VERSION 5.8 ;
BUSBITCHARS "[]" ;
DIVIDERCHAR "/" ;
UNITS
    DATABASE MICRONS 1000 ;
END UNITS

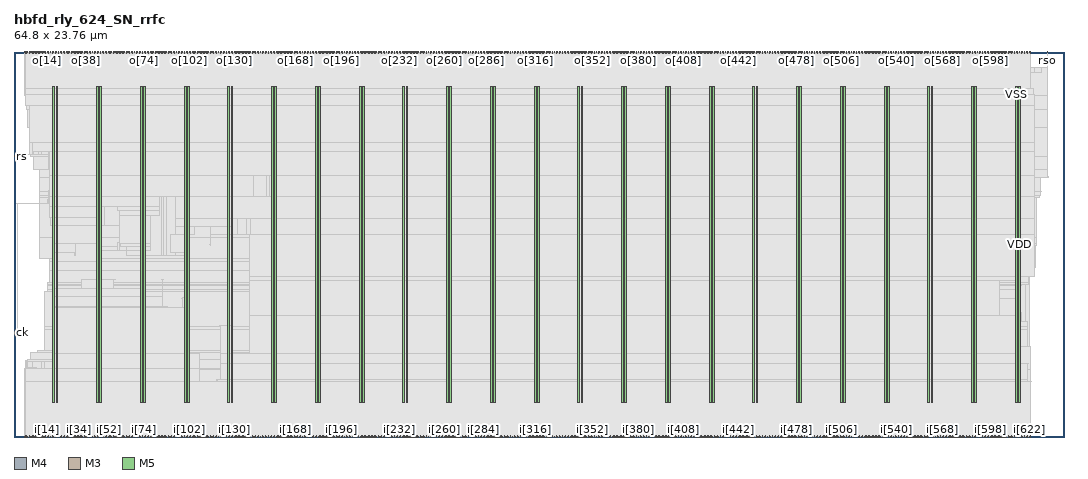
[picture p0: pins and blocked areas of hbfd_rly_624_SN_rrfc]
MACRO hbfd_rly_624_SN_rrfc
  FOREIGN hbfd_rly_624_SN_rrfc 0 0 ;
  CLASS BLOCK ;
  SIZE 64.8 BY 23.76 ;
  PIN ck
    DIRECTION INPUT ;
    USE SIGNAL ;
    PORT
      LAYER M4 ;
        RECT  0 6.432 0.084 6.456 ;
    END
  END ck
  PIN i[0]
    DIRECTION INPUT ;
    USE SIGNAL ;
    PORT
      LAYER M3 ;
        RECT  0.648 0 0.666 0.038 ;
    END
  END i[0]
  PIN i[100]
    DIRECTION INPUT ;
    USE SIGNAL ;
    PORT
      LAYER M3 ;
        RECT  10.62 0 10.638 0.038 ;
    END
  END i[100]
  PIN i[101]
    DIRECTION INPUT ;
    USE SIGNAL ;
    PORT
      LAYER M5 ;
        RECT  10.704 0 10.728 0.084 ;
    END
  END i[101]
  PIN i[102]
    DIRECTION INPUT ;
    USE SIGNAL ;
    PORT
      LAYER M3 ;
        RECT  10.8 0 10.818 0.038 ;
    END
  END i[102]
  PIN i[103]
    DIRECTION INPUT ;
    USE SIGNAL ;
    PORT
      LAYER M5 ;
        RECT  10.896 0 10.92 0.084 ;
    END
  END i[103]
  PIN i[104]
    DIRECTION INPUT ;
    USE SIGNAL ;
    PORT
      LAYER M3 ;
        RECT  11.016 0 11.034 0.038 ;
    END
  END i[104]
  PIN i[105]
    DIRECTION INPUT ;
    USE SIGNAL ;
    PORT
      LAYER M5 ;
        RECT  11.088 0 11.112 0.084 ;
    END
  END i[105]
  PIN i[106]
    DIRECTION INPUT ;
    USE SIGNAL ;
    PORT
      LAYER M3 ;
        RECT  11.196 0 11.214 0.038 ;
    END
  END i[106]
  PIN i[107]
    DIRECTION INPUT ;
    USE SIGNAL ;
    PORT
      LAYER M5 ;
        RECT  11.328 0 11.352 0.084 ;
    END
  END i[107]
  PIN i[108]
    DIRECTION INPUT ;
    USE SIGNAL ;
    PORT
      LAYER M3 ;
        RECT  11.412 0 11.43 0.038 ;
    END
  END i[108]
  PIN i[109]
    DIRECTION INPUT ;
    USE SIGNAL ;
    PORT
      LAYER M5 ;
        RECT  11.52 0 11.544 0.084 ;
    END
  END i[109]
  PIN i[10]
    DIRECTION INPUT ;
    USE SIGNAL ;
    PORT
      LAYER M3 ;
        RECT  1.656 0 1.674 0.038 ;
    END
  END i[10]
  PIN i[110]
    DIRECTION INPUT ;
    USE SIGNAL ;
    PORT
      LAYER M3 ;
        RECT  11.592 0 11.61 0.038 ;
    END
  END i[110]
  PIN i[111]
    DIRECTION INPUT ;
    USE SIGNAL ;
    PORT
      LAYER M5 ;
        RECT  11.712 0 11.736 0.084 ;
    END
  END i[111]
  PIN i[112]
    DIRECTION INPUT ;
    USE SIGNAL ;
    PORT
      LAYER M3 ;
        RECT  11.808 0 11.826 0.038 ;
    END
  END i[112]
  PIN i[113]
    DIRECTION INPUT ;
    USE SIGNAL ;
    PORT
      LAYER M5 ;
        RECT  11.904 0 11.928 0.084 ;
    END
  END i[113]
  PIN i[114]
    DIRECTION INPUT ;
    USE SIGNAL ;
    PORT
      LAYER M3 ;
        RECT  11.988 0 12.006 0.038 ;
    END
  END i[114]
  PIN i[115]
    DIRECTION INPUT ;
    USE SIGNAL ;
    PORT
      LAYER M5 ;
        RECT  12.096 0 12.12 0.084 ;
    END
  END i[115]
  PIN i[116]
    DIRECTION INPUT ;
    USE SIGNAL ;
    PORT
      LAYER M3 ;
        RECT  12.204 0 12.222 0.038 ;
    END
  END i[116]
  PIN i[117]
    DIRECTION INPUT ;
    USE SIGNAL ;
    PORT
      LAYER M5 ;
        RECT  12.288 0 12.312 0.084 ;
    END
  END i[117]
  PIN i[118]
    DIRECTION INPUT ;
    USE SIGNAL ;
    PORT
      LAYER M3 ;
        RECT  12.42 0 12.438 0.038 ;
    END
  END i[118]
  PIN i[119]
    DIRECTION INPUT ;
    USE SIGNAL ;
    PORT
      LAYER M5 ;
        RECT  12.48 0 12.504 0.084 ;
    END
  END i[119]
  PIN i[11]
    DIRECTION INPUT ;
    USE SIGNAL ;
    PORT
      LAYER M5 ;
        RECT  1.728 0 1.752 0.084 ;
    END
  END i[11]
  PIN i[120]
    DIRECTION INPUT ;
    USE SIGNAL ;
    PORT
      LAYER M3 ;
        RECT  12.6 0 12.618 0.038 ;
    END
  END i[120]
  PIN i[121]
    DIRECTION INPUT ;
    USE SIGNAL ;
    PORT
      LAYER M5 ;
        RECT  12.72 0 12.744 0.084 ;
    END
  END i[121]
  PIN i[122]
    DIRECTION INPUT ;
    USE SIGNAL ;
    PORT
      LAYER M3 ;
        RECT  12.816 0 12.834 0.038 ;
    END
  END i[122]
  PIN i[123]
    DIRECTION INPUT ;
    USE SIGNAL ;
    PORT
      LAYER M5 ;
        RECT  12.912 0 12.936 0.084 ;
    END
  END i[123]
  PIN i[124]
    DIRECTION INPUT ;
    USE SIGNAL ;
    PORT
      LAYER M3 ;
        RECT  12.996 0 13.014 0.038 ;
    END
  END i[124]
  PIN i[125]
    DIRECTION INPUT ;
    USE SIGNAL ;
    PORT
      LAYER M5 ;
        RECT  13.104 0 13.128 0.084 ;
    END
  END i[125]
  PIN i[126]
    DIRECTION INPUT ;
    USE SIGNAL ;
    PORT
      LAYER M3 ;
        RECT  13.212 0 13.23 0.038 ;
    END
  END i[126]
  PIN i[127]
    DIRECTION INPUT ;
    USE SIGNAL ;
    PORT
      LAYER M5 ;
        RECT  13.296 0 13.32 0.084 ;
    END
  END i[127]
  PIN i[128]
    DIRECTION INPUT ;
    USE SIGNAL ;
    PORT
      LAYER M3 ;
        RECT  13.392 0 13.41 0.038 ;
    END
  END i[128]
  PIN i[129]
    DIRECTION INPUT ;
    USE SIGNAL ;
    PORT
      LAYER M5 ;
        RECT  13.488 0 13.512 0.084 ;
    END
  END i[129]
  PIN i[12]
    DIRECTION INPUT ;
    USE SIGNAL ;
    PORT
      LAYER M3 ;
        RECT  1.836 0 1.854 0.038 ;
    END
  END i[12]
  PIN i[130]
    DIRECTION INPUT ;
    USE SIGNAL ;
    PORT
      LAYER M3 ;
        RECT  13.608 0 13.626 0.038 ;
    END
  END i[130]
  PIN i[131]
    DIRECTION INPUT ;
    USE SIGNAL ;
    PORT
      LAYER M5 ;
        RECT  13.68 0 13.704 0.084 ;
    END
  END i[131]
  PIN i[132]
    DIRECTION INPUT ;
    USE SIGNAL ;
    PORT
      LAYER M3 ;
        RECT  13.788 0 13.806 0.038 ;
    END
  END i[132]
  PIN i[133]
    DIRECTION INPUT ;
    USE SIGNAL ;
    PORT
      LAYER M5 ;
        RECT  13.872 0 13.896 0.084 ;
    END
  END i[133]
  PIN i[134]
    DIRECTION INPUT ;
    USE SIGNAL ;
    PORT
      LAYER M3 ;
        RECT  14.004 0 14.022 0.038 ;
    END
  END i[134]
  PIN i[135]
    DIRECTION INPUT ;
    USE SIGNAL ;
    PORT
      LAYER M5 ;
        RECT  14.112 0 14.136 0.084 ;
    END
  END i[135]
  PIN i[136]
    DIRECTION INPUT ;
    USE SIGNAL ;
    PORT
      LAYER M3 ;
        RECT  14.184 0 14.202 0.038 ;
    END
  END i[136]
  PIN i[137]
    DIRECTION INPUT ;
    USE SIGNAL ;
    PORT
      LAYER M5 ;
        RECT  14.304 0 14.328 0.084 ;
    END
  END i[137]
  PIN i[138]
    DIRECTION INPUT ;
    USE SIGNAL ;
    PORT
      LAYER M3 ;
        RECT  14.4 0 14.418 0.038 ;
    END
  END i[138]
  PIN i[139]
    DIRECTION INPUT ;
    USE SIGNAL ;
    PORT
      LAYER M5 ;
        RECT  14.496 0 14.52 0.084 ;
    END
  END i[139]
  PIN i[13]
    DIRECTION INPUT ;
    USE SIGNAL ;
    PORT
      LAYER M5 ;
        RECT  1.92 0 1.944 0.084 ;
    END
  END i[13]
  PIN i[140]
    DIRECTION INPUT ;
    USE SIGNAL ;
    PORT
      LAYER M3 ;
        RECT  14.58 0 14.598 0.038 ;
    END
  END i[140]
  PIN i[141]
    DIRECTION INPUT ;
    USE SIGNAL ;
    PORT
      LAYER M5 ;
        RECT  14.688 0 14.712 0.084 ;
    END
  END i[141]
  PIN i[142]
    DIRECTION INPUT ;
    USE SIGNAL ;
    PORT
      LAYER M3 ;
        RECT  14.796 0 14.814 0.038 ;
    END
  END i[142]
  PIN i[143]
    DIRECTION INPUT ;
    USE SIGNAL ;
    PORT
      LAYER M5 ;
        RECT  14.88 0 14.904 0.084 ;
    END
  END i[143]
  PIN i[144]
    DIRECTION INPUT ;
    USE SIGNAL ;
    PORT
      LAYER M3 ;
        RECT  15.012 0 15.03 0.038 ;
    END
  END i[144]
  PIN i[145]
    DIRECTION INPUT ;
    USE SIGNAL ;
    PORT
      LAYER M5 ;
        RECT  15.072 0 15.096 0.084 ;
    END
  END i[145]
  PIN i[146]
    DIRECTION INPUT ;
    USE SIGNAL ;
    PORT
      LAYER M3 ;
        RECT  15.192 0 15.21 0.038 ;
    END
  END i[146]
  PIN i[147]
    DIRECTION INPUT ;
    USE SIGNAL ;
    PORT
      LAYER M5 ;
        RECT  15.312 0 15.336 0.084 ;
    END
  END i[147]
  PIN i[148]
    DIRECTION INPUT ;
    USE SIGNAL ;
    PORT
      LAYER M3 ;
        RECT  15.408 0 15.426 0.038 ;
    END
  END i[148]
  PIN i[149]
    DIRECTION INPUT ;
    USE SIGNAL ;
    PORT
      LAYER M5 ;
        RECT  15.504 0 15.528 0.084 ;
    END
  END i[149]
  PIN i[14]
    DIRECTION INPUT ;
    USE SIGNAL ;
    PORT
      LAYER M3 ;
        RECT  2.052 0 2.07 0.038 ;
    END
  END i[14]
  PIN i[150]
    DIRECTION INPUT ;
    USE SIGNAL ;
    PORT
      LAYER M3 ;
        RECT  15.588 0 15.606 0.038 ;
    END
  END i[150]
  PIN i[151]
    DIRECTION INPUT ;
    USE SIGNAL ;
    PORT
      LAYER M5 ;
        RECT  15.696 0 15.72 0.084 ;
    END
  END i[151]
  PIN i[152]
    DIRECTION INPUT ;
    USE SIGNAL ;
    PORT
      LAYER M3 ;
        RECT  15.804 0 15.822 0.038 ;
    END
  END i[152]
  PIN i[153]
    DIRECTION INPUT ;
    USE SIGNAL ;
    PORT
      LAYER M5 ;
        RECT  15.888 0 15.912 0.084 ;
    END
  END i[153]
  PIN i[154]
    DIRECTION INPUT ;
    USE SIGNAL ;
    PORT
      LAYER M3 ;
        RECT  15.984 0 16.002 0.038 ;
    END
  END i[154]
  PIN i[155]
    DIRECTION INPUT ;
    USE SIGNAL ;
    PORT
      LAYER M5 ;
        RECT  16.08 0 16.104 0.084 ;
    END
  END i[155]
  PIN i[156]
    DIRECTION INPUT ;
    USE SIGNAL ;
    PORT
      LAYER M3 ;
        RECT  16.2 0 16.218 0.038 ;
    END
  END i[156]
  PIN i[157]
    DIRECTION INPUT ;
    USE SIGNAL ;
    PORT
      LAYER M5 ;
        RECT  16.272 0 16.296 0.084 ;
    END
  END i[157]
  PIN i[158]
    DIRECTION INPUT ;
    USE SIGNAL ;
    PORT
      LAYER M3 ;
        RECT  16.38 0 16.398 0.038 ;
    END
  END i[158]
  PIN i[159]
    DIRECTION INPUT ;
    USE SIGNAL ;
    PORT
      LAYER M5 ;
        RECT  16.464 0 16.488 0.084 ;
    END
  END i[159]
  PIN i[15]
    DIRECTION INPUT ;
    USE SIGNAL ;
    PORT
      LAYER M5 ;
        RECT  2.112 0 2.136 0.084 ;
    END
  END i[15]
  PIN i[160]
    DIRECTION INPUT ;
    USE SIGNAL ;
    PORT
      LAYER M3 ;
        RECT  16.596 0 16.614 0.038 ;
    END
  END i[160]
  PIN i[161]
    DIRECTION INPUT ;
    USE SIGNAL ;
    PORT
      LAYER M5 ;
        RECT  16.704 0 16.728 0.084 ;
    END
  END i[161]
  PIN i[162]
    DIRECTION INPUT ;
    USE SIGNAL ;
    PORT
      LAYER M3 ;
        RECT  16.776 0 16.794 0.038 ;
    END
  END i[162]
  PIN i[163]
    DIRECTION INPUT ;
    USE SIGNAL ;
    PORT
      LAYER M5 ;
        RECT  16.896 0 16.92 0.084 ;
    END
  END i[163]
  PIN i[164]
    DIRECTION INPUT ;
    USE SIGNAL ;
    PORT
      LAYER M3 ;
        RECT  16.992 0 17.01 0.038 ;
    END
  END i[164]
  PIN i[165]
    DIRECTION INPUT ;
    USE SIGNAL ;
    PORT
      LAYER M5 ;
        RECT  17.088 0 17.112 0.084 ;
    END
  END i[165]
  PIN i[166]
    DIRECTION INPUT ;
    USE SIGNAL ;
    PORT
      LAYER M3 ;
        RECT  17.172 0 17.19 0.038 ;
    END
  END i[166]
  PIN i[167]
    DIRECTION INPUT ;
    USE SIGNAL ;
    PORT
      LAYER M5 ;
        RECT  17.28 0 17.304 0.084 ;
    END
  END i[167]
  PIN i[168]
    DIRECTION INPUT ;
    USE SIGNAL ;
    PORT
      LAYER M3 ;
        RECT  17.388 0 17.406 0.038 ;
    END
  END i[168]
  PIN i[169]
    DIRECTION INPUT ;
    USE SIGNAL ;
    PORT
      LAYER M5 ;
        RECT  17.472 0 17.496 0.084 ;
    END
  END i[169]
  PIN i[16]
    DIRECTION INPUT ;
    USE SIGNAL ;
    PORT
      LAYER M3 ;
        RECT  2.232 0 2.25 0.038 ;
    END
  END i[16]
  PIN i[170]
    DIRECTION INPUT ;
    USE SIGNAL ;
    PORT
      LAYER M3 ;
        RECT  17.604 0 17.622 0.038 ;
    END
  END i[170]
  PIN i[171]
    DIRECTION INPUT ;
    USE SIGNAL ;
    PORT
      LAYER M5 ;
        RECT  17.664 0 17.688 0.084 ;
    END
  END i[171]
  PIN i[172]
    DIRECTION INPUT ;
    USE SIGNAL ;
    PORT
      LAYER M3 ;
        RECT  17.784 0 17.802 0.038 ;
    END
  END i[172]
  PIN i[173]
    DIRECTION INPUT ;
    USE SIGNAL ;
    PORT
      LAYER M5 ;
        RECT  17.904 0 17.928 0.084 ;
    END
  END i[173]
  PIN i[174]
    DIRECTION INPUT ;
    USE SIGNAL ;
    PORT
      LAYER M3 ;
        RECT  18 0 18.018 0.038 ;
    END
  END i[174]
  PIN i[175]
    DIRECTION INPUT ;
    USE SIGNAL ;
    PORT
      LAYER M5 ;
        RECT  18.096 0 18.12 0.084 ;
    END
  END i[175]
  PIN i[176]
    DIRECTION INPUT ;
    USE SIGNAL ;
    PORT
      LAYER M3 ;
        RECT  18.18 0 18.198 0.038 ;
    END
  END i[176]
  PIN i[177]
    DIRECTION INPUT ;
    USE SIGNAL ;
    PORT
      LAYER M5 ;
        RECT  18.288 0 18.312 0.084 ;
    END
  END i[177]
  PIN i[178]
    DIRECTION INPUT ;
    USE SIGNAL ;
    PORT
      LAYER M3 ;
        RECT  18.396 0 18.414 0.038 ;
    END
  END i[178]
  PIN i[179]
    DIRECTION INPUT ;
    USE SIGNAL ;
    PORT
      LAYER M5 ;
        RECT  18.48 0 18.504 0.084 ;
    END
  END i[179]
  PIN i[17]
    DIRECTION INPUT ;
    USE SIGNAL ;
    PORT
      LAYER M5 ;
        RECT  2.352 0 2.376 0.084 ;
    END
  END i[17]
  PIN i[180]
    DIRECTION INPUT ;
    USE SIGNAL ;
    PORT
      LAYER M3 ;
        RECT  18.576 0 18.594 0.038 ;
    END
  END i[180]
  PIN i[181]
    DIRECTION INPUT ;
    USE SIGNAL ;
    PORT
      LAYER M5 ;
        RECT  18.672 0 18.696 0.084 ;
    END
  END i[181]
  PIN i[182]
    DIRECTION INPUT ;
    USE SIGNAL ;
    PORT
      LAYER M3 ;
        RECT  18.792 0 18.81 0.038 ;
    END
  END i[182]
  PIN i[183]
    DIRECTION INPUT ;
    USE SIGNAL ;
    PORT
      LAYER M5 ;
        RECT  18.864 0 18.888 0.084 ;
    END
  END i[183]
  PIN i[184]
    DIRECTION INPUT ;
    USE SIGNAL ;
    PORT
      LAYER M3 ;
        RECT  18.972 0 18.99 0.038 ;
    END
  END i[184]
  PIN i[185]
    DIRECTION INPUT ;
    USE SIGNAL ;
    PORT
      LAYER M5 ;
        RECT  19.056 0 19.08 0.084 ;
    END
  END i[185]
  PIN i[186]
    DIRECTION INPUT ;
    USE SIGNAL ;
    PORT
      LAYER M3 ;
        RECT  19.188 0 19.206 0.038 ;
    END
  END i[186]
  PIN i[187]
    DIRECTION INPUT ;
    USE SIGNAL ;
    PORT
      LAYER M5 ;
        RECT  19.296 0 19.32 0.084 ;
    END
  END i[187]
  PIN i[188]
    DIRECTION INPUT ;
    USE SIGNAL ;
    PORT
      LAYER M3 ;
        RECT  19.368 0 19.386 0.038 ;
    END
  END i[188]
  PIN i[189]
    DIRECTION INPUT ;
    USE SIGNAL ;
    PORT
      LAYER M5 ;
        RECT  19.488 0 19.512 0.084 ;
    END
  END i[189]
  PIN i[18]
    DIRECTION INPUT ;
    USE SIGNAL ;
    PORT
      LAYER M3 ;
        RECT  2.448 0 2.466 0.038 ;
    END
  END i[18]
  PIN i[190]
    DIRECTION INPUT ;
    USE SIGNAL ;
    PORT
      LAYER M3 ;
        RECT  19.584 0 19.602 0.038 ;
    END
  END i[190]
  PIN i[191]
    DIRECTION INPUT ;
    USE SIGNAL ;
    PORT
      LAYER M5 ;
        RECT  19.68 0 19.704 0.084 ;
    END
  END i[191]
  PIN i[192]
    DIRECTION INPUT ;
    USE SIGNAL ;
    PORT
      LAYER M3 ;
        RECT  19.764 0 19.782 0.038 ;
    END
  END i[192]
  PIN i[193]
    DIRECTION INPUT ;
    USE SIGNAL ;
    PORT
      LAYER M5 ;
        RECT  19.872 0 19.896 0.084 ;
    END
  END i[193]
  PIN i[194]
    DIRECTION INPUT ;
    USE SIGNAL ;
    PORT
      LAYER M3 ;
        RECT  19.98 0 19.998 0.038 ;
    END
  END i[194]
  PIN i[195]
    DIRECTION INPUT ;
    USE SIGNAL ;
    PORT
      LAYER M5 ;
        RECT  20.064 0 20.088 0.084 ;
    END
  END i[195]
  PIN i[196]
    DIRECTION INPUT ;
    USE SIGNAL ;
    PORT
      LAYER M3 ;
        RECT  20.196 0 20.214 0.038 ;
    END
  END i[196]
  PIN i[197]
    DIRECTION INPUT ;
    USE SIGNAL ;
    PORT
      LAYER M5 ;
        RECT  20.256 0 20.28 0.084 ;
    END
  END i[197]
  PIN i[198]
    DIRECTION INPUT ;
    USE SIGNAL ;
    PORT
      LAYER M3 ;
        RECT  20.376 0 20.394 0.038 ;
    END
  END i[198]
  PIN i[199]
    DIRECTION INPUT ;
    USE SIGNAL ;
    PORT
      LAYER M5 ;
        RECT  20.496 0 20.52 0.084 ;
    END
  END i[199]
  PIN i[19]
    DIRECTION INPUT ;
    USE SIGNAL ;
    PORT
      LAYER M5 ;
        RECT  2.544 0 2.568 0.084 ;
    END
  END i[19]
  PIN i[1]
    DIRECTION INPUT ;
    USE SIGNAL ;
    PORT
      LAYER M5 ;
        RECT  0.72 0 0.744 0.084 ;
    END
  END i[1]
  PIN i[200]
    DIRECTION INPUT ;
    USE SIGNAL ;
    PORT
      LAYER M3 ;
        RECT  20.592 0 20.61 0.038 ;
    END
  END i[200]
  PIN i[201]
    DIRECTION INPUT ;
    USE SIGNAL ;
    PORT
      LAYER M5 ;
        RECT  20.688 0 20.712 0.084 ;
    END
  END i[201]
  PIN i[202]
    DIRECTION INPUT ;
    USE SIGNAL ;
    PORT
      LAYER M3 ;
        RECT  20.772 0 20.79 0.038 ;
    END
  END i[202]
  PIN i[203]
    DIRECTION INPUT ;
    USE SIGNAL ;
    PORT
      LAYER M5 ;
        RECT  20.88 0 20.904 0.084 ;
    END
  END i[203]
  PIN i[204]
    DIRECTION INPUT ;
    USE SIGNAL ;
    PORT
      LAYER M3 ;
        RECT  20.988 0 21.006 0.038 ;
    END
  END i[204]
  PIN i[205]
    DIRECTION INPUT ;
    USE SIGNAL ;
    PORT
      LAYER M5 ;
        RECT  21.072 0 21.096 0.084 ;
    END
  END i[205]
  PIN i[206]
    DIRECTION INPUT ;
    USE SIGNAL ;
    PORT
      LAYER M3 ;
        RECT  21.168 0 21.186 0.038 ;
    END
  END i[206]
  PIN i[207]
    DIRECTION INPUT ;
    USE SIGNAL ;
    PORT
      LAYER M5 ;
        RECT  21.264 0 21.288 0.084 ;
    END
  END i[207]
  PIN i[208]
    DIRECTION INPUT ;
    USE SIGNAL ;
    PORT
      LAYER M3 ;
        RECT  21.384 0 21.402 0.038 ;
    END
  END i[208]
  PIN i[209]
    DIRECTION INPUT ;
    USE SIGNAL ;
    PORT
      LAYER M5 ;
        RECT  21.456 0 21.48 0.084 ;
    END
  END i[209]
  PIN i[20]
    DIRECTION INPUT ;
    USE SIGNAL ;
    PORT
      LAYER M3 ;
        RECT  2.628 0 2.646 0.038 ;
    END
  END i[20]
  PIN i[210]
    DIRECTION INPUT ;
    USE SIGNAL ;
    PORT
      LAYER M3 ;
        RECT  21.564 0 21.582 0.038 ;
    END
  END i[210]
  PIN i[211]
    DIRECTION INPUT ;
    USE SIGNAL ;
    PORT
      LAYER M5 ;
        RECT  21.648 0 21.672 0.084 ;
    END
  END i[211]
  PIN i[212]
    DIRECTION INPUT ;
    USE SIGNAL ;
    PORT
      LAYER M3 ;
        RECT  21.78 0 21.798 0.038 ;
    END
  END i[212]
  PIN i[213]
    DIRECTION INPUT ;
    USE SIGNAL ;
    PORT
      LAYER M5 ;
        RECT  21.888 0 21.912 0.084 ;
    END
  END i[213]
  PIN i[214]
    DIRECTION INPUT ;
    USE SIGNAL ;
    PORT
      LAYER M3 ;
        RECT  21.96 0 21.978 0.038 ;
    END
  END i[214]
  PIN i[215]
    DIRECTION INPUT ;
    USE SIGNAL ;
    PORT
      LAYER M5 ;
        RECT  22.08 0 22.104 0.084 ;
    END
  END i[215]
  PIN i[216]
    DIRECTION INPUT ;
    USE SIGNAL ;
    PORT
      LAYER M3 ;
        RECT  22.176 0 22.194 0.038 ;
    END
  END i[216]
  PIN i[217]
    DIRECTION INPUT ;
    USE SIGNAL ;
    PORT
      LAYER M5 ;
        RECT  22.272 0 22.296 0.084 ;
    END
  END i[217]
  PIN i[218]
    DIRECTION INPUT ;
    USE SIGNAL ;
    PORT
      LAYER M3 ;
        RECT  22.356 0 22.374 0.038 ;
    END
  END i[218]
  PIN i[219]
    DIRECTION INPUT ;
    USE SIGNAL ;
    PORT
      LAYER M5 ;
        RECT  22.464 0 22.488 0.084 ;
    END
  END i[219]
  PIN i[21]
    DIRECTION INPUT ;
    USE SIGNAL ;
    PORT
      LAYER M5 ;
        RECT  2.736 0 2.76 0.084 ;
    END
  END i[21]
  PIN i[220]
    DIRECTION INPUT ;
    USE SIGNAL ;
    PORT
      LAYER M3 ;
        RECT  22.572 0 22.59 0.038 ;
    END
  END i[220]
  PIN i[221]
    DIRECTION INPUT ;
    USE SIGNAL ;
    PORT
      LAYER M5 ;
        RECT  22.656 0 22.68 0.084 ;
    END
  END i[221]
  PIN i[222]
    DIRECTION INPUT ;
    USE SIGNAL ;
    PORT
      LAYER M3 ;
        RECT  22.788 0 22.806 0.038 ;
    END
  END i[222]
  PIN i[223]
    DIRECTION INPUT ;
    USE SIGNAL ;
    PORT
      LAYER M5 ;
        RECT  22.848 0 22.872 0.084 ;
    END
  END i[223]
  PIN i[224]
    DIRECTION INPUT ;
    USE SIGNAL ;
    PORT
      LAYER M3 ;
        RECT  22.968 0 22.986 0.038 ;
    END
  END i[224]
  PIN i[225]
    DIRECTION INPUT ;
    USE SIGNAL ;
    PORT
      LAYER M5 ;
        RECT  23.088 0 23.112 0.084 ;
    END
  END i[225]
  PIN i[226]
    DIRECTION INPUT ;
    USE SIGNAL ;
    PORT
      LAYER M3 ;
        RECT  23.184 0 23.202 0.038 ;
    END
  END i[226]
  PIN i[227]
    DIRECTION INPUT ;
    USE SIGNAL ;
    PORT
      LAYER M5 ;
        RECT  23.28 0 23.304 0.084 ;
    END
  END i[227]
  PIN i[228]
    DIRECTION INPUT ;
    USE SIGNAL ;
    PORT
      LAYER M3 ;
        RECT  23.364 0 23.382 0.038 ;
    END
  END i[228]
  PIN i[229]
    DIRECTION INPUT ;
    USE SIGNAL ;
    PORT
      LAYER M5 ;
        RECT  23.472 0 23.496 0.084 ;
    END
  END i[229]
  PIN i[22]
    DIRECTION INPUT ;
    USE SIGNAL ;
    PORT
      LAYER M3 ;
        RECT  2.844 0 2.862 0.038 ;
    END
  END i[22]
  PIN i[230]
    DIRECTION INPUT ;
    USE SIGNAL ;
    PORT
      LAYER M3 ;
        RECT  23.58 0 23.598 0.038 ;
    END
  END i[230]
  PIN i[231]
    DIRECTION INPUT ;
    USE SIGNAL ;
    PORT
      LAYER M5 ;
        RECT  23.664 0 23.688 0.084 ;
    END
  END i[231]
  PIN i[232]
    DIRECTION INPUT ;
    USE SIGNAL ;
    PORT
      LAYER M3 ;
        RECT  23.76 0 23.778 0.038 ;
    END
  END i[232]
  PIN i[233]
    DIRECTION INPUT ;
    USE SIGNAL ;
    PORT
      LAYER M5 ;
        RECT  23.856 0 23.88 0.084 ;
    END
  END i[233]
  PIN i[234]
    DIRECTION INPUT ;
    USE SIGNAL ;
    PORT
      LAYER M3 ;
        RECT  23.976 0 23.994 0.038 ;
    END
  END i[234]
  PIN i[235]
    DIRECTION INPUT ;
    USE SIGNAL ;
    PORT
      LAYER M5 ;
        RECT  24.048 0 24.072 0.084 ;
    END
  END i[235]
  PIN i[236]
    DIRECTION INPUT ;
    USE SIGNAL ;
    PORT
      LAYER M3 ;
        RECT  24.156 0 24.174 0.038 ;
    END
  END i[236]
  PIN i[237]
    DIRECTION INPUT ;
    USE SIGNAL ;
    PORT
      LAYER M5 ;
        RECT  24.24 0 24.264 0.084 ;
    END
  END i[237]
  PIN i[238]
    DIRECTION INPUT ;
    USE SIGNAL ;
    PORT
      LAYER M3 ;
        RECT  24.372 0 24.39 0.038 ;
    END
  END i[238]
  PIN i[239]
    DIRECTION INPUT ;
    USE SIGNAL ;
    PORT
      LAYER M5 ;
        RECT  24.48 0 24.504 0.084 ;
    END
  END i[239]
  PIN i[23]
    DIRECTION INPUT ;
    USE SIGNAL ;
    PORT
      LAYER M5 ;
        RECT  2.928 0 2.952 0.084 ;
    END
  END i[23]
  PIN i[240]
    DIRECTION INPUT ;
    USE SIGNAL ;
    PORT
      LAYER M3 ;
        RECT  24.552 0 24.57 0.038 ;
    END
  END i[240]
  PIN i[241]
    DIRECTION INPUT ;
    USE SIGNAL ;
    PORT
      LAYER M5 ;
        RECT  24.672 0 24.696 0.084 ;
    END
  END i[241]
  PIN i[242]
    DIRECTION INPUT ;
    USE SIGNAL ;
    PORT
      LAYER M3 ;
        RECT  24.768 0 24.786 0.038 ;
    END
  END i[242]
  PIN i[243]
    DIRECTION INPUT ;
    USE SIGNAL ;
    PORT
      LAYER M5 ;
        RECT  24.864 0 24.888 0.084 ;
    END
  END i[243]
  PIN i[244]
    DIRECTION INPUT ;
    USE SIGNAL ;
    PORT
      LAYER M3 ;
        RECT  24.948 0 24.966 0.038 ;
    END
  END i[244]
  PIN i[245]
    DIRECTION INPUT ;
    USE SIGNAL ;
    PORT
      LAYER M5 ;
        RECT  25.056 0 25.08 0.084 ;
    END
  END i[245]
  PIN i[246]
    DIRECTION INPUT ;
    USE SIGNAL ;
    PORT
      LAYER M3 ;
        RECT  25.164 0 25.182 0.038 ;
    END
  END i[246]
  PIN i[247]
    DIRECTION INPUT ;
    USE SIGNAL ;
    PORT
      LAYER M5 ;
        RECT  25.248 0 25.272 0.084 ;
    END
  END i[247]
  PIN i[248]
    DIRECTION INPUT ;
    USE SIGNAL ;
    PORT
      LAYER M3 ;
        RECT  25.344 0 25.362 0.038 ;
    END
  END i[248]
  PIN i[249]
    DIRECTION INPUT ;
    USE SIGNAL ;
    PORT
      LAYER M5 ;
        RECT  25.44 0 25.464 0.084 ;
    END
  END i[249]
  PIN i[24]
    DIRECTION INPUT ;
    USE SIGNAL ;
    PORT
      LAYER M3 ;
        RECT  3.024 0 3.042 0.038 ;
    END
  END i[24]
  PIN i[250]
    DIRECTION INPUT ;
    USE SIGNAL ;
    PORT
      LAYER M3 ;
        RECT  25.56 0 25.578 0.038 ;
    END
  END i[250]
  PIN i[251]
    DIRECTION INPUT ;
    USE SIGNAL ;
    PORT
      LAYER M5 ;
        RECT  25.68 0 25.704 0.084 ;
    END
  END i[251]
  PIN i[252]
    DIRECTION INPUT ;
    USE SIGNAL ;
    PORT
      LAYER M3 ;
        RECT  25.776 0 25.794 0.038 ;
    END
  END i[252]
  PIN i[253]
    DIRECTION INPUT ;
    USE SIGNAL ;
    PORT
      LAYER M5 ;
        RECT  25.872 0 25.896 0.084 ;
    END
  END i[253]
  PIN i[254]
    DIRECTION INPUT ;
    USE SIGNAL ;
    PORT
      LAYER M3 ;
        RECT  25.956 0 25.974 0.038 ;
    END
  END i[254]
  PIN i[255]
    DIRECTION INPUT ;
    USE SIGNAL ;
    PORT
      LAYER M5 ;
        RECT  26.064 0 26.088 0.084 ;
    END
  END i[255]
  PIN i[256]
    DIRECTION INPUT ;
    USE SIGNAL ;
    PORT
      LAYER M3 ;
        RECT  26.172 0 26.19 0.038 ;
    END
  END i[256]
  PIN i[257]
    DIRECTION INPUT ;
    USE SIGNAL ;
    PORT
      LAYER M5 ;
        RECT  26.256 0 26.28 0.084 ;
    END
  END i[257]
  PIN i[258]
    DIRECTION INPUT ;
    USE SIGNAL ;
    PORT
      LAYER M3 ;
        RECT  26.352 0 26.37 0.038 ;
    END
  END i[258]
  PIN i[259]
    DIRECTION INPUT ;
    USE SIGNAL ;
    PORT
      LAYER M5 ;
        RECT  26.448 0 26.472 0.084 ;
    END
  END i[259]
  PIN i[25]
    DIRECTION INPUT ;
    USE SIGNAL ;
    PORT
      LAYER M5 ;
        RECT  3.12 0 3.144 0.084 ;
    END
  END i[25]
  PIN i[260]
    DIRECTION INPUT ;
    USE SIGNAL ;
    PORT
      LAYER M3 ;
        RECT  26.568 0 26.586 0.038 ;
    END
  END i[260]
  PIN i[261]
    DIRECTION INPUT ;
    USE SIGNAL ;
    PORT
      LAYER M5 ;
        RECT  26.64 0 26.664 0.084 ;
    END
  END i[261]
  PIN i[262]
    DIRECTION INPUT ;
    USE SIGNAL ;
    PORT
      LAYER M3 ;
        RECT  26.748 0 26.766 0.038 ;
    END
  END i[262]
  PIN i[263]
    DIRECTION INPUT ;
    USE SIGNAL ;
    PORT
      LAYER M5 ;
        RECT  26.832 0 26.856 0.084 ;
    END
  END i[263]
  PIN i[264]
    DIRECTION INPUT ;
    USE SIGNAL ;
    PORT
      LAYER M3 ;
        RECT  26.964 0 26.982 0.038 ;
    END
  END i[264]
  PIN i[265]
    DIRECTION INPUT ;
    USE SIGNAL ;
    PORT
      LAYER M5 ;
        RECT  27.072 0 27.096 0.084 ;
    END
  END i[265]
  PIN i[266]
    DIRECTION INPUT ;
    USE SIGNAL ;
    PORT
      LAYER M3 ;
        RECT  27.144 0 27.162 0.038 ;
    END
  END i[266]
  PIN i[267]
    DIRECTION INPUT ;
    USE SIGNAL ;
    PORT
      LAYER M5 ;
        RECT  27.264 0 27.288 0.084 ;
    END
  END i[267]
  PIN i[268]
    DIRECTION INPUT ;
    USE SIGNAL ;
    PORT
      LAYER M3 ;
        RECT  27.36 0 27.378 0.038 ;
    END
  END i[268]
  PIN i[269]
    DIRECTION INPUT ;
    USE SIGNAL ;
    PORT
      LAYER M5 ;
        RECT  27.456 0 27.48 0.084 ;
    END
  END i[269]
  PIN i[26]
    DIRECTION INPUT ;
    USE SIGNAL ;
    PORT
      LAYER M3 ;
        RECT  3.24 0 3.258 0.038 ;
    END
  END i[26]
  PIN i[270]
    DIRECTION INPUT ;
    USE SIGNAL ;
    PORT
      LAYER M3 ;
        RECT  27.54 0 27.558 0.038 ;
    END
  END i[270]
  PIN i[271]
    DIRECTION INPUT ;
    USE SIGNAL ;
    PORT
      LAYER M5 ;
        RECT  27.648 0 27.672 0.084 ;
    END
  END i[271]
  PIN i[272]
    DIRECTION INPUT ;
    USE SIGNAL ;
    PORT
      LAYER M3 ;
        RECT  27.756 0 27.774 0.038 ;
    END
  END i[272]
  PIN i[273]
    DIRECTION INPUT ;
    USE SIGNAL ;
    PORT
      LAYER M5 ;
        RECT  27.84 0 27.864 0.084 ;
    END
  END i[273]
  PIN i[274]
    DIRECTION INPUT ;
    USE SIGNAL ;
    PORT
      LAYER M3 ;
        RECT  27.936 0 27.954 0.038 ;
    END
  END i[274]
  PIN i[275]
    DIRECTION INPUT ;
    USE SIGNAL ;
    PORT
      LAYER M5 ;
        RECT  28.032 0 28.056 0.084 ;
    END
  END i[275]
  PIN i[276]
    DIRECTION INPUT ;
    USE SIGNAL ;
    PORT
      LAYER M3 ;
        RECT  28.152 0 28.17 0.038 ;
    END
  END i[276]
  PIN i[277]
    DIRECTION INPUT ;
    USE SIGNAL ;
    PORT
      LAYER M5 ;
        RECT  28.272 0 28.296 0.084 ;
    END
  END i[277]
  PIN i[278]
    DIRECTION INPUT ;
    USE SIGNAL ;
    PORT
      LAYER M3 ;
        RECT  28.368 0 28.386 0.038 ;
    END
  END i[278]
  PIN i[279]
    DIRECTION INPUT ;
    USE SIGNAL ;
    PORT
      LAYER M5 ;
        RECT  28.464 0 28.488 0.084 ;
    END
  END i[279]
  PIN i[27]
    DIRECTION INPUT ;
    USE SIGNAL ;
    PORT
      LAYER M5 ;
        RECT  3.312 0 3.336 0.084 ;
    END
  END i[27]
  PIN i[280]
    DIRECTION INPUT ;
    USE SIGNAL ;
    PORT
      LAYER M3 ;
        RECT  28.548 0 28.566 0.038 ;
    END
  END i[280]
  PIN i[281]
    DIRECTION INPUT ;
    USE SIGNAL ;
    PORT
      LAYER M5 ;
        RECT  28.656 0 28.68 0.084 ;
    END
  END i[281]
  PIN i[282]
    DIRECTION INPUT ;
    USE SIGNAL ;
    PORT
      LAYER M3 ;
        RECT  28.764 0 28.782 0.038 ;
    END
  END i[282]
  PIN i[283]
    DIRECTION INPUT ;
    USE SIGNAL ;
    PORT
      LAYER M5 ;
        RECT  28.848 0 28.872 0.084 ;
    END
  END i[283]
  PIN i[284]
    DIRECTION INPUT ;
    USE SIGNAL ;
    PORT
      LAYER M3 ;
        RECT  28.944 0 28.962 0.038 ;
    END
  END i[284]
  PIN i[285]
    DIRECTION INPUT ;
    USE SIGNAL ;
    PORT
      LAYER M5 ;
        RECT  29.04 0 29.064 0.084 ;
    END
  END i[285]
  PIN i[286]
    DIRECTION INPUT ;
    USE SIGNAL ;
    PORT
      LAYER M3 ;
        RECT  29.16 0 29.178 0.038 ;
    END
  END i[286]
  PIN i[287]
    DIRECTION INPUT ;
    USE SIGNAL ;
    PORT
      LAYER M5 ;
        RECT  29.232 0 29.256 0.084 ;
    END
  END i[287]
  PIN i[288]
    DIRECTION INPUT ;
    USE SIGNAL ;
    PORT
      LAYER M3 ;
        RECT  29.34 0 29.358 0.038 ;
    END
  END i[288]
  PIN i[289]
    DIRECTION INPUT ;
    USE SIGNAL ;
    PORT
      LAYER M5 ;
        RECT  29.424 0 29.448 0.084 ;
    END
  END i[289]
  PIN i[28]
    DIRECTION INPUT ;
    USE SIGNAL ;
    PORT
      LAYER M3 ;
        RECT  3.42 0 3.438 0.038 ;
    END
  END i[28]
  PIN i[290]
    DIRECTION INPUT ;
    USE SIGNAL ;
    PORT
      LAYER M3 ;
        RECT  29.556 0 29.574 0.038 ;
    END
  END i[290]
  PIN i[291]
    DIRECTION INPUT ;
    USE SIGNAL ;
    PORT
      LAYER M5 ;
        RECT  29.664 0 29.688 0.084 ;
    END
  END i[291]
  PIN i[292]
    DIRECTION INPUT ;
    USE SIGNAL ;
    PORT
      LAYER M3 ;
        RECT  29.736 0 29.754 0.038 ;
    END
  END i[292]
  PIN i[293]
    DIRECTION INPUT ;
    USE SIGNAL ;
    PORT
      LAYER M5 ;
        RECT  29.856 0 29.88 0.084 ;
    END
  END i[293]
  PIN i[294]
    DIRECTION INPUT ;
    USE SIGNAL ;
    PORT
      LAYER M3 ;
        RECT  29.952 0 29.97 0.038 ;
    END
  END i[294]
  PIN i[295]
    DIRECTION INPUT ;
    USE SIGNAL ;
    PORT
      LAYER M5 ;
        RECT  30.048 0 30.072 0.084 ;
    END
  END i[295]
  PIN i[296]
    DIRECTION INPUT ;
    USE SIGNAL ;
    PORT
      LAYER M3 ;
        RECT  30.132 0 30.15 0.038 ;
    END
  END i[296]
  PIN i[297]
    DIRECTION INPUT ;
    USE SIGNAL ;
    PORT
      LAYER M5 ;
        RECT  30.24 0 30.264 0.084 ;
    END
  END i[297]
  PIN i[298]
    DIRECTION INPUT ;
    USE SIGNAL ;
    PORT
      LAYER M3 ;
        RECT  30.348 0 30.366 0.038 ;
    END
  END i[298]
  PIN i[299]
    DIRECTION INPUT ;
    USE SIGNAL ;
    PORT
      LAYER M5 ;
        RECT  30.432 0 30.456 0.084 ;
    END
  END i[299]
  PIN i[29]
    DIRECTION INPUT ;
    USE SIGNAL ;
    PORT
      LAYER M5 ;
        RECT  3.552 0 3.576 0.084 ;
    END
  END i[29]
  PIN i[2]
    DIRECTION INPUT ;
    USE SIGNAL ;
    PORT
      LAYER M3 ;
        RECT  0.828 0 0.846 0.038 ;
    END
  END i[2]
  PIN i[300]
    DIRECTION INPUT ;
    USE SIGNAL ;
    PORT
      LAYER M3 ;
        RECT  30.528 0 30.546 0.038 ;
    END
  END i[300]
  PIN i[301]
    DIRECTION INPUT ;
    USE SIGNAL ;
    PORT
      LAYER M5 ;
        RECT  30.624 0 30.648 0.084 ;
    END
  END i[301]
  PIN i[302]
    DIRECTION INPUT ;
    USE SIGNAL ;
    PORT
      LAYER M3 ;
        RECT  30.744 0 30.762 0.038 ;
    END
  END i[302]
  PIN i[303]
    DIRECTION INPUT ;
    USE SIGNAL ;
    PORT
      LAYER M5 ;
        RECT  30.864 0 30.888 0.084 ;
    END
  END i[303]
  PIN i[304]
    DIRECTION INPUT ;
    USE SIGNAL ;
    PORT
      LAYER M3 ;
        RECT  30.96 0 30.978 0.038 ;
    END
  END i[304]
  PIN i[305]
    DIRECTION INPUT ;
    USE SIGNAL ;
    PORT
      LAYER M5 ;
        RECT  31.056 0 31.08 0.084 ;
    END
  END i[305]
  PIN i[306]
    DIRECTION INPUT ;
    USE SIGNAL ;
    PORT
      LAYER M3 ;
        RECT  31.14 0 31.158 0.038 ;
    END
  END i[306]
  PIN i[307]
    DIRECTION INPUT ;
    USE SIGNAL ;
    PORT
      LAYER M5 ;
        RECT  31.248 0 31.272 0.084 ;
    END
  END i[307]
  PIN i[308]
    DIRECTION INPUT ;
    USE SIGNAL ;
    PORT
      LAYER M3 ;
        RECT  31.356 0 31.374 0.038 ;
    END
  END i[308]
  PIN i[309]
    DIRECTION INPUT ;
    USE SIGNAL ;
    PORT
      LAYER M5 ;
        RECT  31.44 0 31.464 0.084 ;
    END
  END i[309]
  PIN i[30]
    DIRECTION INPUT ;
    USE SIGNAL ;
    PORT
      LAYER M3 ;
        RECT  3.636 0 3.654 0.038 ;
    END
  END i[30]
  PIN i[310]
    DIRECTION INPUT ;
    USE SIGNAL ;
    PORT
      LAYER M3 ;
        RECT  31.536 0 31.554 0.038 ;
    END
  END i[310]
  PIN i[311]
    DIRECTION INPUT ;
    USE SIGNAL ;
    PORT
      LAYER M5 ;
        RECT  31.632 0 31.656 0.084 ;
    END
  END i[311]
  PIN i[312]
    DIRECTION INPUT ;
    USE SIGNAL ;
    PORT
      LAYER M3 ;
        RECT  31.752 0 31.77 0.038 ;
    END
  END i[312]
  PIN i[313]
    DIRECTION INPUT ;
    USE SIGNAL ;
    PORT
      LAYER M5 ;
        RECT  31.824 0 31.848 0.084 ;
    END
  END i[313]
  PIN i[314]
    DIRECTION INPUT ;
    USE SIGNAL ;
    PORT
      LAYER M3 ;
        RECT  31.932 0 31.95 0.038 ;
    END
  END i[314]
  PIN i[315]
    DIRECTION INPUT ;
    USE SIGNAL ;
    PORT
      LAYER M5 ;
        RECT  32.016 0 32.04 0.084 ;
    END
  END i[315]
  PIN i[316]
    DIRECTION INPUT ;
    USE SIGNAL ;
    PORT
      LAYER M3 ;
        RECT  32.148 0 32.166 0.038 ;
    END
  END i[316]
  PIN i[317]
    DIRECTION INPUT ;
    USE SIGNAL ;
    PORT
      LAYER M5 ;
        RECT  32.256 0 32.28 0.084 ;
    END
  END i[317]
  PIN i[318]
    DIRECTION INPUT ;
    USE SIGNAL ;
    PORT
      LAYER M3 ;
        RECT  32.328 0 32.346 0.038 ;
    END
  END i[318]
  PIN i[319]
    DIRECTION INPUT ;
    USE SIGNAL ;
    PORT
      LAYER M5 ;
        RECT  32.448 0 32.472 0.084 ;
    END
  END i[319]
  PIN i[31]
    DIRECTION INPUT ;
    USE SIGNAL ;
    PORT
      LAYER M5 ;
        RECT  3.744 0 3.768 0.084 ;
    END
  END i[31]
  PIN i[320]
    DIRECTION INPUT ;
    USE SIGNAL ;
    PORT
      LAYER M3 ;
        RECT  32.544 0 32.562 0.038 ;
    END
  END i[320]
  PIN i[321]
    DIRECTION INPUT ;
    USE SIGNAL ;
    PORT
      LAYER M5 ;
        RECT  32.64 0 32.664 0.084 ;
    END
  END i[321]
  PIN i[322]
    DIRECTION INPUT ;
    USE SIGNAL ;
    PORT
      LAYER M3 ;
        RECT  32.724 0 32.742 0.038 ;
    END
  END i[322]
  PIN i[323]
    DIRECTION INPUT ;
    USE SIGNAL ;
    PORT
      LAYER M5 ;
        RECT  32.832 0 32.856 0.084 ;
    END
  END i[323]
  PIN i[324]
    DIRECTION INPUT ;
    USE SIGNAL ;
    PORT
      LAYER M3 ;
        RECT  32.94 0 32.958 0.038 ;
    END
  END i[324]
  PIN i[325]
    DIRECTION INPUT ;
    USE SIGNAL ;
    PORT
      LAYER M5 ;
        RECT  33.024 0 33.048 0.084 ;
    END
  END i[325]
  PIN i[326]
    DIRECTION INPUT ;
    USE SIGNAL ;
    PORT
      LAYER M3 ;
        RECT  33.12 0 33.138 0.038 ;
    END
  END i[326]
  PIN i[327]
    DIRECTION INPUT ;
    USE SIGNAL ;
    PORT
      LAYER M5 ;
        RECT  33.216 0 33.24 0.084 ;
    END
  END i[327]
  PIN i[328]
    DIRECTION INPUT ;
    USE SIGNAL ;
    PORT
      LAYER M3 ;
        RECT  33.336 0 33.354 0.038 ;
    END
  END i[328]
  PIN i[329]
    DIRECTION INPUT ;
    USE SIGNAL ;
    PORT
      LAYER M5 ;
        RECT  33.456 0 33.48 0.084 ;
    END
  END i[329]
  PIN i[32]
    DIRECTION INPUT ;
    USE SIGNAL ;
    PORT
      LAYER M3 ;
        RECT  3.816 0 3.834 0.038 ;
    END
  END i[32]
  PIN i[330]
    DIRECTION INPUT ;
    USE SIGNAL ;
    PORT
      LAYER M3 ;
        RECT  33.552 0 33.57 0.038 ;
    END
  END i[330]
  PIN i[331]
    DIRECTION INPUT ;
    USE SIGNAL ;
    PORT
      LAYER M5 ;
        RECT  33.648 0 33.672 0.084 ;
    END
  END i[331]
  PIN i[332]
    DIRECTION INPUT ;
    USE SIGNAL ;
    PORT
      LAYER M3 ;
        RECT  33.732 0 33.75 0.038 ;
    END
  END i[332]
  PIN i[333]
    DIRECTION INPUT ;
    USE SIGNAL ;
    PORT
      LAYER M5 ;
        RECT  33.84 0 33.864 0.084 ;
    END
  END i[333]
  PIN i[334]
    DIRECTION INPUT ;
    USE SIGNAL ;
    PORT
      LAYER M3 ;
        RECT  33.948 0 33.966 0.038 ;
    END
  END i[334]
  PIN i[335]
    DIRECTION INPUT ;
    USE SIGNAL ;
    PORT
      LAYER M5 ;
        RECT  34.032 0 34.056 0.084 ;
    END
  END i[335]
  PIN i[336]
    DIRECTION INPUT ;
    USE SIGNAL ;
    PORT
      LAYER M3 ;
        RECT  34.128 0 34.146 0.038 ;
    END
  END i[336]
  PIN i[337]
    DIRECTION INPUT ;
    USE SIGNAL ;
    PORT
      LAYER M5 ;
        RECT  34.224 0 34.248 0.084 ;
    END
  END i[337]
  PIN i[338]
    DIRECTION INPUT ;
    USE SIGNAL ;
    PORT
      LAYER M3 ;
        RECT  34.344 0 34.362 0.038 ;
    END
  END i[338]
  PIN i[339]
    DIRECTION INPUT ;
    USE SIGNAL ;
    PORT
      LAYER M5 ;
        RECT  34.416 0 34.44 0.084 ;
    END
  END i[339]
  PIN i[33]
    DIRECTION INPUT ;
    USE SIGNAL ;
    PORT
      LAYER M5 ;
        RECT  3.936 0 3.96 0.084 ;
    END
  END i[33]
  PIN i[340]
    DIRECTION INPUT ;
    USE SIGNAL ;
    PORT
      LAYER M3 ;
        RECT  34.524 0 34.542 0.038 ;
    END
  END i[340]
  PIN i[341]
    DIRECTION INPUT ;
    USE SIGNAL ;
    PORT
      LAYER M5 ;
        RECT  34.608 0 34.632 0.084 ;
    END
  END i[341]
  PIN i[342]
    DIRECTION INPUT ;
    USE SIGNAL ;
    PORT
      LAYER M3 ;
        RECT  34.74 0 34.758 0.038 ;
    END
  END i[342]
  PIN i[343]
    DIRECTION INPUT ;
    USE SIGNAL ;
    PORT
      LAYER M5 ;
        RECT  34.848 0 34.872 0.084 ;
    END
  END i[343]
  PIN i[344]
    DIRECTION INPUT ;
    USE SIGNAL ;
    PORT
      LAYER M3 ;
        RECT  34.92 0 34.938 0.038 ;
    END
  END i[344]
  PIN i[345]
    DIRECTION INPUT ;
    USE SIGNAL ;
    PORT
      LAYER M5 ;
        RECT  35.04 0 35.064 0.084 ;
    END
  END i[345]
  PIN i[346]
    DIRECTION INPUT ;
    USE SIGNAL ;
    PORT
      LAYER M3 ;
        RECT  35.136 0 35.154 0.038 ;
    END
  END i[346]
  PIN i[347]
    DIRECTION INPUT ;
    USE SIGNAL ;
    PORT
      LAYER M5 ;
        RECT  35.232 0 35.256 0.084 ;
    END
  END i[347]
  PIN i[348]
    DIRECTION INPUT ;
    USE SIGNAL ;
    PORT
      LAYER M3 ;
        RECT  35.316 0 35.334 0.038 ;
    END
  END i[348]
  PIN i[349]
    DIRECTION INPUT ;
    USE SIGNAL ;
    PORT
      LAYER M5 ;
        RECT  35.424 0 35.448 0.084 ;
    END
  END i[349]
  PIN i[34]
    DIRECTION INPUT ;
    USE SIGNAL ;
    PORT
      LAYER M3 ;
        RECT  4.032 0 4.05 0.038 ;
    END
  END i[34]
  PIN i[350]
    DIRECTION INPUT ;
    USE SIGNAL ;
    PORT
      LAYER M3 ;
        RECT  35.532 0 35.55 0.038 ;
    END
  END i[350]
  PIN i[351]
    DIRECTION INPUT ;
    USE SIGNAL ;
    PORT
      LAYER M5 ;
        RECT  35.616 0 35.64 0.084 ;
    END
  END i[351]
  PIN i[352]
    DIRECTION INPUT ;
    USE SIGNAL ;
    PORT
      LAYER M3 ;
        RECT  35.712 0 35.73 0.038 ;
    END
  END i[352]
  PIN i[353]
    DIRECTION INPUT ;
    USE SIGNAL ;
    PORT
      LAYER M5 ;
        RECT  35.808 0 35.832 0.084 ;
    END
  END i[353]
  PIN i[354]
    DIRECTION INPUT ;
    USE SIGNAL ;
    PORT
      LAYER M3 ;
        RECT  35.928 0 35.946 0.038 ;
    END
  END i[354]
  PIN i[355]
    DIRECTION INPUT ;
    USE SIGNAL ;
    PORT
      LAYER M5 ;
        RECT  36.048 0 36.072 0.084 ;
    END
  END i[355]
  PIN i[356]
    DIRECTION INPUT ;
    USE SIGNAL ;
    PORT
      LAYER M3 ;
        RECT  36.144 0 36.162 0.038 ;
    END
  END i[356]
  PIN i[357]
    DIRECTION INPUT ;
    USE SIGNAL ;
    PORT
      LAYER M5 ;
        RECT  36.24 0 36.264 0.084 ;
    END
  END i[357]
  PIN i[358]
    DIRECTION INPUT ;
    USE SIGNAL ;
    PORT
      LAYER M3 ;
        RECT  36.324 0 36.342 0.038 ;
    END
  END i[358]
  PIN i[359]
    DIRECTION INPUT ;
    USE SIGNAL ;
    PORT
      LAYER M5 ;
        RECT  36.432 0 36.456 0.084 ;
    END
  END i[359]
  PIN i[35]
    DIRECTION INPUT ;
    USE SIGNAL ;
    PORT
      LAYER M5 ;
        RECT  4.128 0 4.152 0.084 ;
    END
  END i[35]
  PIN i[360]
    DIRECTION INPUT ;
    USE SIGNAL ;
    PORT
      LAYER M3 ;
        RECT  36.54 0 36.558 0.038 ;
    END
  END i[360]
  PIN i[361]
    DIRECTION INPUT ;
    USE SIGNAL ;
    PORT
      LAYER M5 ;
        RECT  36.624 0 36.648 0.084 ;
    END
  END i[361]
  PIN i[362]
    DIRECTION INPUT ;
    USE SIGNAL ;
    PORT
      LAYER M3 ;
        RECT  36.72 0 36.738 0.038 ;
    END
  END i[362]
  PIN i[363]
    DIRECTION INPUT ;
    USE SIGNAL ;
    PORT
      LAYER M5 ;
        RECT  36.816 0 36.84 0.084 ;
    END
  END i[363]
  PIN i[364]
    DIRECTION INPUT ;
    USE SIGNAL ;
    PORT
      LAYER M3 ;
        RECT  36.936 0 36.954 0.038 ;
    END
  END i[364]
  PIN i[365]
    DIRECTION INPUT ;
    USE SIGNAL ;
    PORT
      LAYER M5 ;
        RECT  37.008 0 37.032 0.084 ;
    END
  END i[365]
  PIN i[366]
    DIRECTION INPUT ;
    USE SIGNAL ;
    PORT
      LAYER M3 ;
        RECT  37.116 0 37.134 0.038 ;
    END
  END i[366]
  PIN i[367]
    DIRECTION INPUT ;
    USE SIGNAL ;
    PORT
      LAYER M5 ;
        RECT  37.2 0 37.224 0.084 ;
    END
  END i[367]
  PIN i[368]
    DIRECTION INPUT ;
    USE SIGNAL ;
    PORT
      LAYER M3 ;
        RECT  37.332 0 37.35 0.038 ;
    END
  END i[368]
  PIN i[369]
    DIRECTION INPUT ;
    USE SIGNAL ;
    PORT
      LAYER M5 ;
        RECT  37.44 0 37.464 0.084 ;
    END
  END i[369]
  PIN i[36]
    DIRECTION INPUT ;
    USE SIGNAL ;
    PORT
      LAYER M3 ;
        RECT  4.212 0 4.23 0.038 ;
    END
  END i[36]
  PIN i[370]
    DIRECTION INPUT ;
    USE SIGNAL ;
    PORT
      LAYER M3 ;
        RECT  37.512 0 37.53 0.038 ;
    END
  END i[370]
  PIN i[371]
    DIRECTION INPUT ;
    USE SIGNAL ;
    PORT
      LAYER M5 ;
        RECT  37.632 0 37.656 0.084 ;
    END
  END i[371]
  PIN i[372]
    DIRECTION INPUT ;
    USE SIGNAL ;
    PORT
      LAYER M3 ;
        RECT  37.728 0 37.746 0.038 ;
    END
  END i[372]
  PIN i[373]
    DIRECTION INPUT ;
    USE SIGNAL ;
    PORT
      LAYER M5 ;
        RECT  37.824 0 37.848 0.084 ;
    END
  END i[373]
  PIN i[374]
    DIRECTION INPUT ;
    USE SIGNAL ;
    PORT
      LAYER M3 ;
        RECT  37.908 0 37.926 0.038 ;
    END
  END i[374]
  PIN i[375]
    DIRECTION INPUT ;
    USE SIGNAL ;
    PORT
      LAYER M5 ;
        RECT  38.016 0 38.04 0.084 ;
    END
  END i[375]
  PIN i[376]
    DIRECTION INPUT ;
    USE SIGNAL ;
    PORT
      LAYER M3 ;
        RECT  38.124 0 38.142 0.038 ;
    END
  END i[376]
  PIN i[377]
    DIRECTION INPUT ;
    USE SIGNAL ;
    PORT
      LAYER M5 ;
        RECT  38.208 0 38.232 0.084 ;
    END
  END i[377]
  PIN i[378]
    DIRECTION INPUT ;
    USE SIGNAL ;
    PORT
      LAYER M3 ;
        RECT  38.304 0 38.322 0.038 ;
    END
  END i[378]
  PIN i[379]
    DIRECTION INPUT ;
    USE SIGNAL ;
    PORT
      LAYER M5 ;
        RECT  38.4 0 38.424 0.084 ;
    END
  END i[379]
  PIN i[37]
    DIRECTION INPUT ;
    USE SIGNAL ;
    PORT
      LAYER M5 ;
        RECT  4.32 0 4.344 0.084 ;
    END
  END i[37]
  PIN i[380]
    DIRECTION INPUT ;
    USE SIGNAL ;
    PORT
      LAYER M3 ;
        RECT  38.52 0 38.538 0.038 ;
    END
  END i[380]
  PIN i[381]
    DIRECTION INPUT ;
    USE SIGNAL ;
    PORT
      LAYER M5 ;
        RECT  38.64 0 38.664 0.084 ;
    END
  END i[381]
  PIN i[382]
    DIRECTION INPUT ;
    USE SIGNAL ;
    PORT
      LAYER M3 ;
        RECT  38.736 0 38.754 0.038 ;
    END
  END i[382]
  PIN i[383]
    DIRECTION INPUT ;
    USE SIGNAL ;
    PORT
      LAYER M5 ;
        RECT  38.832 0 38.856 0.084 ;
    END
  END i[383]
  PIN i[384]
    DIRECTION INPUT ;
    USE SIGNAL ;
    PORT
      LAYER M3 ;
        RECT  38.916 0 38.934 0.038 ;
    END
  END i[384]
  PIN i[385]
    DIRECTION INPUT ;
    USE SIGNAL ;
    PORT
      LAYER M5 ;
        RECT  39.024 0 39.048 0.084 ;
    END
  END i[385]
  PIN i[386]
    DIRECTION INPUT ;
    USE SIGNAL ;
    PORT
      LAYER M3 ;
        RECT  39.132 0 39.15 0.038 ;
    END
  END i[386]
  PIN i[387]
    DIRECTION INPUT ;
    USE SIGNAL ;
    PORT
      LAYER M5 ;
        RECT  39.216 0 39.24 0.084 ;
    END
  END i[387]
  PIN i[388]
    DIRECTION INPUT ;
    USE SIGNAL ;
    PORT
      LAYER M3 ;
        RECT  39.312 0 39.33 0.038 ;
    END
  END i[388]
  PIN i[389]
    DIRECTION INPUT ;
    USE SIGNAL ;
    PORT
      LAYER M5 ;
        RECT  39.408 0 39.432 0.084 ;
    END
  END i[389]
  PIN i[38]
    DIRECTION INPUT ;
    USE SIGNAL ;
    PORT
      LAYER M3 ;
        RECT  4.428 0 4.446 0.038 ;
    END
  END i[38]
  PIN i[390]
    DIRECTION INPUT ;
    USE SIGNAL ;
    PORT
      LAYER M3 ;
        RECT  39.528 0 39.546 0.038 ;
    END
  END i[390]
  PIN i[391]
    DIRECTION INPUT ;
    USE SIGNAL ;
    PORT
      LAYER M5 ;
        RECT  39.6 0 39.624 0.084 ;
    END
  END i[391]
  PIN i[392]
    DIRECTION INPUT ;
    USE SIGNAL ;
    PORT
      LAYER M3 ;
        RECT  39.708 0 39.726 0.038 ;
    END
  END i[392]
  PIN i[393]
    DIRECTION INPUT ;
    USE SIGNAL ;
    PORT
      LAYER M5 ;
        RECT  39.792 0 39.816 0.084 ;
    END
  END i[393]
  PIN i[394]
    DIRECTION INPUT ;
    USE SIGNAL ;
    PORT
      LAYER M3 ;
        RECT  39.924 0 39.942 0.038 ;
    END
  END i[394]
  PIN i[395]
    DIRECTION INPUT ;
    USE SIGNAL ;
    PORT
      LAYER M5 ;
        RECT  40.032 0 40.056 0.084 ;
    END
  END i[395]
  PIN i[396]
    DIRECTION INPUT ;
    USE SIGNAL ;
    PORT
      LAYER M3 ;
        RECT  40.104 0 40.122 0.038 ;
    END
  END i[396]
  PIN i[397]
    DIRECTION INPUT ;
    USE SIGNAL ;
    PORT
      LAYER M5 ;
        RECT  40.224 0 40.248 0.084 ;
    END
  END i[397]
  PIN i[398]
    DIRECTION INPUT ;
    USE SIGNAL ;
    PORT
      LAYER M3 ;
        RECT  40.32 0 40.338 0.038 ;
    END
  END i[398]
  PIN i[399]
    DIRECTION INPUT ;
    USE SIGNAL ;
    PORT
      LAYER M5 ;
        RECT  40.416 0 40.44 0.084 ;
    END
  END i[399]
  PIN i[39]
    DIRECTION INPUT ;
    USE SIGNAL ;
    PORT
      LAYER M5 ;
        RECT  4.512 0 4.536 0.084 ;
    END
  END i[39]
  PIN i[3]
    DIRECTION INPUT ;
    USE SIGNAL ;
    PORT
      LAYER M5 ;
        RECT  0.96 0 0.984 0.084 ;
    END
  END i[3]
  PIN i[400]
    DIRECTION INPUT ;
    USE SIGNAL ;
    PORT
      LAYER M3 ;
        RECT  40.5 0 40.518 0.038 ;
    END
  END i[400]
  PIN i[401]
    DIRECTION INPUT ;
    USE SIGNAL ;
    PORT
      LAYER M5 ;
        RECT  40.608 0 40.632 0.084 ;
    END
  END i[401]
  PIN i[402]
    DIRECTION INPUT ;
    USE SIGNAL ;
    PORT
      LAYER M3 ;
        RECT  40.716 0 40.734 0.038 ;
    END
  END i[402]
  PIN i[403]
    DIRECTION INPUT ;
    USE SIGNAL ;
    PORT
      LAYER M5 ;
        RECT  40.8 0 40.824 0.084 ;
    END
  END i[403]
  PIN i[404]
    DIRECTION INPUT ;
    USE SIGNAL ;
    PORT
      LAYER M3 ;
        RECT  40.896 0 40.914 0.038 ;
    END
  END i[404]
  PIN i[405]
    DIRECTION INPUT ;
    USE SIGNAL ;
    PORT
      LAYER M5 ;
        RECT  40.992 0 41.016 0.084 ;
    END
  END i[405]
  PIN i[406]
    DIRECTION INPUT ;
    USE SIGNAL ;
    PORT
      LAYER M3 ;
        RECT  41.112 0 41.13 0.038 ;
    END
  END i[406]
  PIN i[407]
    DIRECTION INPUT ;
    USE SIGNAL ;
    PORT
      LAYER M5 ;
        RECT  41.184 0 41.208 0.084 ;
    END
  END i[407]
  PIN i[408]
    DIRECTION INPUT ;
    USE SIGNAL ;
    PORT
      LAYER M3 ;
        RECT  41.328 0 41.346 0.038 ;
    END
  END i[408]
  PIN i[409]
    DIRECTION INPUT ;
    USE SIGNAL ;
    PORT
      LAYER M5 ;
        RECT  41.424 0 41.448 0.084 ;
    END
  END i[409]
  PIN i[40]
    DIRECTION INPUT ;
    USE SIGNAL ;
    PORT
      LAYER M3 ;
        RECT  4.644 0 4.662 0.038 ;
    END
  END i[40]
  PIN i[410]
    DIRECTION INPUT ;
    USE SIGNAL ;
    PORT
      LAYER M3 ;
        RECT  41.508 0 41.526 0.038 ;
    END
  END i[410]
  PIN i[411]
    DIRECTION INPUT ;
    USE SIGNAL ;
    PORT
      LAYER M5 ;
        RECT  41.616 0 41.64 0.084 ;
    END
  END i[411]
  PIN i[412]
    DIRECTION INPUT ;
    USE SIGNAL ;
    PORT
      LAYER M3 ;
        RECT  41.724 0 41.742 0.038 ;
    END
  END i[412]
  PIN i[413]
    DIRECTION INPUT ;
    USE SIGNAL ;
    PORT
      LAYER M5 ;
        RECT  41.808 0 41.832 0.084 ;
    END
  END i[413]
  PIN i[414]
    DIRECTION INPUT ;
    USE SIGNAL ;
    PORT
      LAYER M3 ;
        RECT  41.904 0 41.922 0.038 ;
    END
  END i[414]
  PIN i[415]
    DIRECTION INPUT ;
    USE SIGNAL ;
    PORT
      LAYER M5 ;
        RECT  42 0 42.024 0.084 ;
    END
  END i[415]
  PIN i[416]
    DIRECTION INPUT ;
    USE SIGNAL ;
    PORT
      LAYER M3 ;
        RECT  42.12 0 42.138 0.038 ;
    END
  END i[416]
  PIN i[417]
    DIRECTION INPUT ;
    USE SIGNAL ;
    PORT
      LAYER M5 ;
        RECT  42.192 0 42.216 0.084 ;
    END
  END i[417]
  PIN i[418]
    DIRECTION INPUT ;
    USE SIGNAL ;
    PORT
      LAYER M3 ;
        RECT  42.3 0 42.318 0.038 ;
    END
  END i[418]
  PIN i[419]
    DIRECTION INPUT ;
    USE SIGNAL ;
    PORT
      LAYER M5 ;
        RECT  42.384 0 42.408 0.084 ;
    END
  END i[419]
  PIN i[41]
    DIRECTION INPUT ;
    USE SIGNAL ;
    PORT
      LAYER M5 ;
        RECT  4.704 0 4.728 0.084 ;
    END
  END i[41]
  PIN i[420]
    DIRECTION INPUT ;
    USE SIGNAL ;
    PORT
      LAYER M3 ;
        RECT  42.516 0 42.534 0.038 ;
    END
  END i[420]
  PIN i[421]
    DIRECTION INPUT ;
    USE SIGNAL ;
    PORT
      LAYER M5 ;
        RECT  42.624 0 42.648 0.084 ;
    END
  END i[421]
  PIN i[422]
    DIRECTION INPUT ;
    USE SIGNAL ;
    PORT
      LAYER M3 ;
        RECT  42.696 0 42.714 0.038 ;
    END
  END i[422]
  PIN i[423]
    DIRECTION INPUT ;
    USE SIGNAL ;
    PORT
      LAYER M5 ;
        RECT  42.816 0 42.84 0.084 ;
    END
  END i[423]
  PIN i[424]
    DIRECTION INPUT ;
    USE SIGNAL ;
    PORT
      LAYER M3 ;
        RECT  42.912 0 42.93 0.038 ;
    END
  END i[424]
  PIN i[425]
    DIRECTION INPUT ;
    USE SIGNAL ;
    PORT
      LAYER M5 ;
        RECT  43.008 0 43.032 0.084 ;
    END
  END i[425]
  PIN i[426]
    DIRECTION INPUT ;
    USE SIGNAL ;
    PORT
      LAYER M3 ;
        RECT  43.092 0 43.11 0.038 ;
    END
  END i[426]
  PIN i[427]
    DIRECTION INPUT ;
    USE SIGNAL ;
    PORT
      LAYER M5 ;
        RECT  43.2 0 43.224 0.084 ;
    END
  END i[427]
  PIN i[428]
    DIRECTION INPUT ;
    USE SIGNAL ;
    PORT
      LAYER M3 ;
        RECT  43.308 0 43.326 0.038 ;
    END
  END i[428]
  PIN i[429]
    DIRECTION INPUT ;
    USE SIGNAL ;
    PORT
      LAYER M5 ;
        RECT  43.392 0 43.416 0.084 ;
    END
  END i[429]
  PIN i[42]
    DIRECTION INPUT ;
    USE SIGNAL ;
    PORT
      LAYER M3 ;
        RECT  4.824 0 4.842 0.038 ;
    END
  END i[42]
  PIN i[430]
    DIRECTION INPUT ;
    USE SIGNAL ;
    PORT
      LAYER M3 ;
        RECT  43.488 0 43.506 0.038 ;
    END
  END i[430]
  PIN i[431]
    DIRECTION INPUT ;
    USE SIGNAL ;
    PORT
      LAYER M5 ;
        RECT  43.584 0 43.608 0.084 ;
    END
  END i[431]
  PIN i[432]
    DIRECTION INPUT ;
    USE SIGNAL ;
    PORT
      LAYER M3 ;
        RECT  43.704 0 43.722 0.038 ;
    END
  END i[432]
  PIN i[433]
    DIRECTION INPUT ;
    USE SIGNAL ;
    PORT
      LAYER M5 ;
        RECT  43.776 0 43.8 0.084 ;
    END
  END i[433]
  PIN i[434]
    DIRECTION INPUT ;
    USE SIGNAL ;
    PORT
      LAYER M3 ;
        RECT  43.92 0 43.938 0.038 ;
    END
  END i[434]
  PIN i[435]
    DIRECTION INPUT ;
    USE SIGNAL ;
    PORT
      LAYER M5 ;
        RECT  44.016 0 44.04 0.084 ;
    END
  END i[435]
  PIN i[436]
    DIRECTION INPUT ;
    USE SIGNAL ;
    PORT
      LAYER M3 ;
        RECT  44.1 0 44.118 0.038 ;
    END
  END i[436]
  PIN i[437]
    DIRECTION INPUT ;
    USE SIGNAL ;
    PORT
      LAYER M5 ;
        RECT  44.208 0 44.232 0.084 ;
    END
  END i[437]
  PIN i[438]
    DIRECTION INPUT ;
    USE SIGNAL ;
    PORT
      LAYER M3 ;
        RECT  44.316 0 44.334 0.038 ;
    END
  END i[438]
  PIN i[439]
    DIRECTION INPUT ;
    USE SIGNAL ;
    PORT
      LAYER M5 ;
        RECT  44.4 0 44.424 0.084 ;
    END
  END i[439]
  PIN i[43]
    DIRECTION INPUT ;
    USE SIGNAL ;
    PORT
      LAYER M5 ;
        RECT  4.944 0 4.968 0.084 ;
    END
  END i[43]
  PIN i[440]
    DIRECTION INPUT ;
    USE SIGNAL ;
    PORT
      LAYER M3 ;
        RECT  44.496 0 44.514 0.038 ;
    END
  END i[440]
  PIN i[441]
    DIRECTION INPUT ;
    USE SIGNAL ;
    PORT
      LAYER M5 ;
        RECT  44.592 0 44.616 0.084 ;
    END
  END i[441]
  PIN i[442]
    DIRECTION INPUT ;
    USE SIGNAL ;
    PORT
      LAYER M3 ;
        RECT  44.712 0 44.73 0.038 ;
    END
  END i[442]
  PIN i[443]
    DIRECTION INPUT ;
    USE SIGNAL ;
    PORT
      LAYER M5 ;
        RECT  44.784 0 44.808 0.084 ;
    END
  END i[443]
  PIN i[444]
    DIRECTION INPUT ;
    USE SIGNAL ;
    PORT
      LAYER M3 ;
        RECT  44.892 0 44.91 0.038 ;
    END
  END i[444]
  PIN i[445]
    DIRECTION INPUT ;
    USE SIGNAL ;
    PORT
      LAYER M5 ;
        RECT  44.976 0 45 0.084 ;
    END
  END i[445]
  PIN i[446]
    DIRECTION INPUT ;
    USE SIGNAL ;
    PORT
      LAYER M3 ;
        RECT  45.108 0 45.126 0.038 ;
    END
  END i[446]
  PIN i[447]
    DIRECTION INPUT ;
    USE SIGNAL ;
    PORT
      LAYER M5 ;
        RECT  45.216 0 45.24 0.084 ;
    END
  END i[447]
  PIN i[448]
    DIRECTION INPUT ;
    USE SIGNAL ;
    PORT
      LAYER M3 ;
        RECT  45.288 0 45.306 0.038 ;
    END
  END i[448]
  PIN i[449]
    DIRECTION INPUT ;
    USE SIGNAL ;
    PORT
      LAYER M5 ;
        RECT  45.408 0 45.432 0.084 ;
    END
  END i[449]
  PIN i[44]
    DIRECTION INPUT ;
    USE SIGNAL ;
    PORT
      LAYER M3 ;
        RECT  5.04 0 5.058 0.038 ;
    END
  END i[44]
  PIN i[450]
    DIRECTION INPUT ;
    USE SIGNAL ;
    PORT
      LAYER M3 ;
        RECT  45.504 0 45.522 0.038 ;
    END
  END i[450]
  PIN i[451]
    DIRECTION INPUT ;
    USE SIGNAL ;
    PORT
      LAYER M5 ;
        RECT  45.6 0 45.624 0.084 ;
    END
  END i[451]
  PIN i[452]
    DIRECTION INPUT ;
    USE SIGNAL ;
    PORT
      LAYER M3 ;
        RECT  45.684 0 45.702 0.038 ;
    END
  END i[452]
  PIN i[453]
    DIRECTION INPUT ;
    USE SIGNAL ;
    PORT
      LAYER M5 ;
        RECT  45.792 0 45.816 0.084 ;
    END
  END i[453]
  PIN i[454]
    DIRECTION INPUT ;
    USE SIGNAL ;
    PORT
      LAYER M3 ;
        RECT  45.9 0 45.918 0.038 ;
    END
  END i[454]
  PIN i[455]
    DIRECTION INPUT ;
    USE SIGNAL ;
    PORT
      LAYER M5 ;
        RECT  45.984 0 46.008 0.084 ;
    END
  END i[455]
  PIN i[456]
    DIRECTION INPUT ;
    USE SIGNAL ;
    PORT
      LAYER M3 ;
        RECT  46.08 0 46.098 0.038 ;
    END
  END i[456]
  PIN i[457]
    DIRECTION INPUT ;
    USE SIGNAL ;
    PORT
      LAYER M5 ;
        RECT  46.176 0 46.2 0.084 ;
    END
  END i[457]
  PIN i[458]
    DIRECTION INPUT ;
    USE SIGNAL ;
    PORT
      LAYER M3 ;
        RECT  46.296 0 46.314 0.038 ;
    END
  END i[458]
  PIN i[459]
    DIRECTION INPUT ;
    USE SIGNAL ;
    PORT
      LAYER M5 ;
        RECT  46.368 0 46.392 0.084 ;
    END
  END i[459]
  PIN i[45]
    DIRECTION INPUT ;
    USE SIGNAL ;
    PORT
      LAYER M5 ;
        RECT  5.136 0 5.16 0.084 ;
    END
  END i[45]
  PIN i[460]
    DIRECTION INPUT ;
    USE SIGNAL ;
    PORT
      LAYER M3 ;
        RECT  46.476 0 46.494 0.038 ;
    END
  END i[460]
  PIN i[461]
    DIRECTION INPUT ;
    USE SIGNAL ;
    PORT
      LAYER M5 ;
        RECT  46.608 0 46.632 0.084 ;
    END
  END i[461]
  PIN i[462]
    DIRECTION INPUT ;
    USE SIGNAL ;
    PORT
      LAYER M3 ;
        RECT  46.692 0 46.71 0.038 ;
    END
  END i[462]
  PIN i[463]
    DIRECTION INPUT ;
    USE SIGNAL ;
    PORT
      LAYER M5 ;
        RECT  46.8 0 46.824 0.084 ;
    END
  END i[463]
  PIN i[464]
    DIRECTION INPUT ;
    USE SIGNAL ;
    PORT
      LAYER M3 ;
        RECT  46.908 0 46.926 0.038 ;
    END
  END i[464]
  PIN i[465]
    DIRECTION INPUT ;
    USE SIGNAL ;
    PORT
      LAYER M5 ;
        RECT  46.992 0 47.016 0.084 ;
    END
  END i[465]
  PIN i[466]
    DIRECTION INPUT ;
    USE SIGNAL ;
    PORT
      LAYER M3 ;
        RECT  47.088 0 47.106 0.038 ;
    END
  END i[466]
  PIN i[467]
    DIRECTION INPUT ;
    USE SIGNAL ;
    PORT
      LAYER M5 ;
        RECT  47.184 0 47.208 0.084 ;
    END
  END i[467]
  PIN i[468]
    DIRECTION INPUT ;
    USE SIGNAL ;
    PORT
      LAYER M3 ;
        RECT  47.304 0 47.322 0.038 ;
    END
  END i[468]
  PIN i[469]
    DIRECTION INPUT ;
    USE SIGNAL ;
    PORT
      LAYER M5 ;
        RECT  47.376 0 47.4 0.084 ;
    END
  END i[469]
  PIN i[46]
    DIRECTION INPUT ;
    USE SIGNAL ;
    PORT
      LAYER M3 ;
        RECT  5.22 0 5.238 0.038 ;
    END
  END i[46]
  PIN i[470]
    DIRECTION INPUT ;
    USE SIGNAL ;
    PORT
      LAYER M3 ;
        RECT  47.484 0 47.502 0.038 ;
    END
  END i[470]
  PIN i[471]
    DIRECTION INPUT ;
    USE SIGNAL ;
    PORT
      LAYER M5 ;
        RECT  47.568 0 47.592 0.084 ;
    END
  END i[471]
  PIN i[472]
    DIRECTION INPUT ;
    USE SIGNAL ;
    PORT
      LAYER M3 ;
        RECT  47.7 0 47.718 0.038 ;
    END
  END i[472]
  PIN i[473]
    DIRECTION INPUT ;
    USE SIGNAL ;
    PORT
      LAYER M5 ;
        RECT  47.808 0 47.832 0.084 ;
    END
  END i[473]
  PIN i[474]
    DIRECTION INPUT ;
    USE SIGNAL ;
    PORT
      LAYER M3 ;
        RECT  47.88 0 47.898 0.038 ;
    END
  END i[474]
  PIN i[475]
    DIRECTION INPUT ;
    USE SIGNAL ;
    PORT
      LAYER M5 ;
        RECT  48 0 48.024 0.084 ;
    END
  END i[475]
  PIN i[476]
    DIRECTION INPUT ;
    USE SIGNAL ;
    PORT
      LAYER M3 ;
        RECT  48.096 0 48.114 0.038 ;
    END
  END i[476]
  PIN i[477]
    DIRECTION INPUT ;
    USE SIGNAL ;
    PORT
      LAYER M5 ;
        RECT  48.192 0 48.216 0.084 ;
    END
  END i[477]
  PIN i[478]
    DIRECTION INPUT ;
    USE SIGNAL ;
    PORT
      LAYER M3 ;
        RECT  48.276 0 48.294 0.038 ;
    END
  END i[478]
  PIN i[479]
    DIRECTION INPUT ;
    USE SIGNAL ;
    PORT
      LAYER M5 ;
        RECT  48.384 0 48.408 0.084 ;
    END
  END i[479]
  PIN i[47]
    DIRECTION INPUT ;
    USE SIGNAL ;
    PORT
      LAYER M5 ;
        RECT  5.328 0 5.352 0.084 ;
    END
  END i[47]
  PIN i[480]
    DIRECTION INPUT ;
    USE SIGNAL ;
    PORT
      LAYER M3 ;
        RECT  48.492 0 48.51 0.038 ;
    END
  END i[480]
  PIN i[481]
    DIRECTION INPUT ;
    USE SIGNAL ;
    PORT
      LAYER M5 ;
        RECT  48.576 0 48.6 0.084 ;
    END
  END i[481]
  PIN i[482]
    DIRECTION INPUT ;
    USE SIGNAL ;
    PORT
      LAYER M3 ;
        RECT  48.672 0 48.69 0.038 ;
    END
  END i[482]
  PIN i[483]
    DIRECTION INPUT ;
    USE SIGNAL ;
    PORT
      LAYER M5 ;
        RECT  48.768 0 48.792 0.084 ;
    END
  END i[483]
  PIN i[484]
    DIRECTION INPUT ;
    USE SIGNAL ;
    PORT
      LAYER M3 ;
        RECT  48.888 0 48.906 0.038 ;
    END
  END i[484]
  PIN i[485]
    DIRECTION INPUT ;
    USE SIGNAL ;
    PORT
      LAYER M5 ;
        RECT  48.96 0 48.984 0.084 ;
    END
  END i[485]
  PIN i[486]
    DIRECTION INPUT ;
    USE SIGNAL ;
    PORT
      LAYER M3 ;
        RECT  49.068 0 49.086 0.038 ;
    END
  END i[486]
  PIN i[487]
    DIRECTION INPUT ;
    USE SIGNAL ;
    PORT
      LAYER M5 ;
        RECT  49.2 0 49.224 0.084 ;
    END
  END i[487]
  PIN i[488]
    DIRECTION INPUT ;
    USE SIGNAL ;
    PORT
      LAYER M3 ;
        RECT  49.284 0 49.302 0.038 ;
    END
  END i[488]
  PIN i[489]
    DIRECTION INPUT ;
    USE SIGNAL ;
    PORT
      LAYER M5 ;
        RECT  49.392 0 49.416 0.084 ;
    END
  END i[489]
  PIN i[48]
    DIRECTION INPUT ;
    USE SIGNAL ;
    PORT
      LAYER M3 ;
        RECT  5.436 0 5.454 0.038 ;
    END
  END i[48]
  PIN i[490]
    DIRECTION INPUT ;
    USE SIGNAL ;
    PORT
      LAYER M3 ;
        RECT  49.5 0 49.518 0.038 ;
    END
  END i[490]
  PIN i[491]
    DIRECTION INPUT ;
    USE SIGNAL ;
    PORT
      LAYER M5 ;
        RECT  49.584 0 49.608 0.084 ;
    END
  END i[491]
  PIN i[492]
    DIRECTION INPUT ;
    USE SIGNAL ;
    PORT
      LAYER M3 ;
        RECT  49.68 0 49.698 0.038 ;
    END
  END i[492]
  PIN i[493]
    DIRECTION INPUT ;
    USE SIGNAL ;
    PORT
      LAYER M5 ;
        RECT  49.776 0 49.8 0.084 ;
    END
  END i[493]
  PIN i[494]
    DIRECTION INPUT ;
    USE SIGNAL ;
    PORT
      LAYER M3 ;
        RECT  49.896 0 49.914 0.038 ;
    END
  END i[494]
  PIN i[495]
    DIRECTION INPUT ;
    USE SIGNAL ;
    PORT
      LAYER M5 ;
        RECT  49.968 0 49.992 0.084 ;
    END
  END i[495]
  PIN i[496]
    DIRECTION INPUT ;
    USE SIGNAL ;
    PORT
      LAYER M3 ;
        RECT  50.076 0 50.094 0.038 ;
    END
  END i[496]
  PIN i[497]
    DIRECTION INPUT ;
    USE SIGNAL ;
    PORT
      LAYER M5 ;
        RECT  50.16 0 50.184 0.084 ;
    END
  END i[497]
  PIN i[498]
    DIRECTION INPUT ;
    USE SIGNAL ;
    PORT
      LAYER M3 ;
        RECT  50.292 0 50.31 0.038 ;
    END
  END i[498]
  PIN i[499]
    DIRECTION INPUT ;
    USE SIGNAL ;
    PORT
      LAYER M5 ;
        RECT  50.4 0 50.424 0.084 ;
    END
  END i[499]
  PIN i[49]
    DIRECTION INPUT ;
    USE SIGNAL ;
    PORT
      LAYER M5 ;
        RECT  5.52 0 5.544 0.084 ;
    END
  END i[49]
  PIN i[4]
    DIRECTION INPUT ;
    USE SIGNAL ;
    PORT
      LAYER M3 ;
        RECT  1.044 0 1.062 0.038 ;
    END
  END i[4]
  PIN i[500]
    DIRECTION INPUT ;
    USE SIGNAL ;
    PORT
      LAYER M3 ;
        RECT  50.472 0 50.49 0.038 ;
    END
  END i[500]
  PIN i[501]
    DIRECTION INPUT ;
    USE SIGNAL ;
    PORT
      LAYER M5 ;
        RECT  50.592 0 50.616 0.084 ;
    END
  END i[501]
  PIN i[502]
    DIRECTION INPUT ;
    USE SIGNAL ;
    PORT
      LAYER M3 ;
        RECT  50.688 0 50.706 0.038 ;
    END
  END i[502]
  PIN i[503]
    DIRECTION INPUT ;
    USE SIGNAL ;
    PORT
      LAYER M5 ;
        RECT  50.784 0 50.808 0.084 ;
    END
  END i[503]
  PIN i[504]
    DIRECTION INPUT ;
    USE SIGNAL ;
    PORT
      LAYER M3 ;
        RECT  50.868 0 50.886 0.038 ;
    END
  END i[504]
  PIN i[505]
    DIRECTION INPUT ;
    USE SIGNAL ;
    PORT
      LAYER M5 ;
        RECT  50.976 0 51 0.084 ;
    END
  END i[505]
  PIN i[506]
    DIRECTION INPUT ;
    USE SIGNAL ;
    PORT
      LAYER M3 ;
        RECT  51.084 0 51.102 0.038 ;
    END
  END i[506]
  PIN i[507]
    DIRECTION INPUT ;
    USE SIGNAL ;
    PORT
      LAYER M5 ;
        RECT  51.168 0 51.192 0.084 ;
    END
  END i[507]
  PIN i[508]
    DIRECTION INPUT ;
    USE SIGNAL ;
    PORT
      LAYER M3 ;
        RECT  51.264 0 51.282 0.038 ;
    END
  END i[508]
  PIN i[509]
    DIRECTION INPUT ;
    USE SIGNAL ;
    PORT
      LAYER M5 ;
        RECT  51.36 0 51.384 0.084 ;
    END
  END i[509]
  PIN i[50]
    DIRECTION INPUT ;
    USE SIGNAL ;
    PORT
      LAYER M3 ;
        RECT  5.616 0 5.634 0.038 ;
    END
  END i[50]
  PIN i[510]
    DIRECTION INPUT ;
    USE SIGNAL ;
    PORT
      LAYER M3 ;
        RECT  51.48 0 51.498 0.038 ;
    END
  END i[510]
  PIN i[511]
    DIRECTION INPUT ;
    USE SIGNAL ;
    PORT
      LAYER M5 ;
        RECT  51.552 0 51.576 0.084 ;
    END
  END i[511]
  PIN i[512]
    DIRECTION INPUT ;
    USE SIGNAL ;
    PORT
      LAYER M3 ;
        RECT  51.66 0 51.678 0.038 ;
    END
  END i[512]
  PIN i[513]
    DIRECTION INPUT ;
    USE SIGNAL ;
    PORT
      LAYER M5 ;
        RECT  51.792 0 51.816 0.084 ;
    END
  END i[513]
  PIN i[514]
    DIRECTION INPUT ;
    USE SIGNAL ;
    PORT
      LAYER M3 ;
        RECT  51.876 0 51.894 0.038 ;
    END
  END i[514]
  PIN i[515]
    DIRECTION INPUT ;
    USE SIGNAL ;
    PORT
      LAYER M5 ;
        RECT  51.984 0 52.008 0.084 ;
    END
  END i[515]
  PIN i[516]
    DIRECTION INPUT ;
    USE SIGNAL ;
    PORT
      LAYER M3 ;
        RECT  52.092 0 52.11 0.038 ;
    END
  END i[516]
  PIN i[517]
    DIRECTION INPUT ;
    USE SIGNAL ;
    PORT
      LAYER M5 ;
        RECT  52.176 0 52.2 0.084 ;
    END
  END i[517]
  PIN i[518]
    DIRECTION INPUT ;
    USE SIGNAL ;
    PORT
      LAYER M3 ;
        RECT  52.272 0 52.29 0.038 ;
    END
  END i[518]
  PIN i[519]
    DIRECTION INPUT ;
    USE SIGNAL ;
    PORT
      LAYER M5 ;
        RECT  52.368 0 52.392 0.084 ;
    END
  END i[519]
  PIN i[51]
    DIRECTION INPUT ;
    USE SIGNAL ;
    PORT
      LAYER M5 ;
        RECT  5.712 0 5.736 0.084 ;
    END
  END i[51]
  PIN i[520]
    DIRECTION INPUT ;
    USE SIGNAL ;
    PORT
      LAYER M3 ;
        RECT  52.488 0 52.506 0.038 ;
    END
  END i[520]
  PIN i[521]
    DIRECTION INPUT ;
    USE SIGNAL ;
    PORT
      LAYER M5 ;
        RECT  52.56 0 52.584 0.084 ;
    END
  END i[521]
  PIN i[522]
    DIRECTION INPUT ;
    USE SIGNAL ;
    PORT
      LAYER M3 ;
        RECT  52.668 0 52.686 0.038 ;
    END
  END i[522]
  PIN i[523]
    DIRECTION INPUT ;
    USE SIGNAL ;
    PORT
      LAYER M5 ;
        RECT  52.752 0 52.776 0.084 ;
    END
  END i[523]
  PIN i[524]
    DIRECTION INPUT ;
    USE SIGNAL ;
    PORT
      LAYER M3 ;
        RECT  52.884 0 52.902 0.038 ;
    END
  END i[524]
  PIN i[525]
    DIRECTION INPUT ;
    USE SIGNAL ;
    PORT
      LAYER M5 ;
        RECT  52.992 0 53.016 0.084 ;
    END
  END i[525]
  PIN i[526]
    DIRECTION INPUT ;
    USE SIGNAL ;
    PORT
      LAYER M3 ;
        RECT  53.064 0 53.082 0.038 ;
    END
  END i[526]
  PIN i[527]
    DIRECTION INPUT ;
    USE SIGNAL ;
    PORT
      LAYER M5 ;
        RECT  53.184 0 53.208 0.084 ;
    END
  END i[527]
  PIN i[528]
    DIRECTION INPUT ;
    USE SIGNAL ;
    PORT
      LAYER M3 ;
        RECT  53.28 0 53.298 0.038 ;
    END
  END i[528]
  PIN i[529]
    DIRECTION INPUT ;
    USE SIGNAL ;
    PORT
      LAYER M5 ;
        RECT  53.376 0 53.4 0.084 ;
    END
  END i[529]
  PIN i[52]
    DIRECTION INPUT ;
    USE SIGNAL ;
    PORT
      LAYER M3 ;
        RECT  5.832 0 5.85 0.038 ;
    END
  END i[52]
  PIN i[530]
    DIRECTION INPUT ;
    USE SIGNAL ;
    PORT
      LAYER M3 ;
        RECT  53.46 0 53.478 0.038 ;
    END
  END i[530]
  PIN i[531]
    DIRECTION INPUT ;
    USE SIGNAL ;
    PORT
      LAYER M5 ;
        RECT  53.568 0 53.592 0.084 ;
    END
  END i[531]
  PIN i[532]
    DIRECTION INPUT ;
    USE SIGNAL ;
    PORT
      LAYER M3 ;
        RECT  53.676 0 53.694 0.038 ;
    END
  END i[532]
  PIN i[533]
    DIRECTION INPUT ;
    USE SIGNAL ;
    PORT
      LAYER M5 ;
        RECT  53.76 0 53.784 0.084 ;
    END
  END i[533]
  PIN i[534]
    DIRECTION INPUT ;
    USE SIGNAL ;
    PORT
      LAYER M3 ;
        RECT  53.856 0 53.874 0.038 ;
    END
  END i[534]
  PIN i[535]
    DIRECTION INPUT ;
    USE SIGNAL ;
    PORT
      LAYER M5 ;
        RECT  53.952 0 53.976 0.084 ;
    END
  END i[535]
  PIN i[536]
    DIRECTION INPUT ;
    USE SIGNAL ;
    PORT
      LAYER M3 ;
        RECT  54.072 0 54.09 0.038 ;
    END
  END i[536]
  PIN i[537]
    DIRECTION INPUT ;
    USE SIGNAL ;
    PORT
      LAYER M5 ;
        RECT  54.144 0 54.168 0.084 ;
    END
  END i[537]
  PIN i[538]
    DIRECTION INPUT ;
    USE SIGNAL ;
    PORT
      LAYER M3 ;
        RECT  54.252 0 54.27 0.038 ;
    END
  END i[538]
  PIN i[539]
    DIRECTION INPUT ;
    USE SIGNAL ;
    PORT
      LAYER M5 ;
        RECT  54.384 0 54.408 0.084 ;
    END
  END i[539]
  PIN i[53]
    DIRECTION INPUT ;
    USE SIGNAL ;
    PORT
      LAYER M5 ;
        RECT  5.904 0 5.928 0.084 ;
    END
  END i[53]
  PIN i[540]
    DIRECTION INPUT ;
    USE SIGNAL ;
    PORT
      LAYER M3 ;
        RECT  54.468 0 54.486 0.038 ;
    END
  END i[540]
  PIN i[541]
    DIRECTION INPUT ;
    USE SIGNAL ;
    PORT
      LAYER M5 ;
        RECT  54.576 0 54.6 0.084 ;
    END
  END i[541]
  PIN i[542]
    DIRECTION INPUT ;
    USE SIGNAL ;
    PORT
      LAYER M3 ;
        RECT  54.684 0 54.702 0.038 ;
    END
  END i[542]
  PIN i[543]
    DIRECTION INPUT ;
    USE SIGNAL ;
    PORT
      LAYER M5 ;
        RECT  54.768 0 54.792 0.084 ;
    END
  END i[543]
  PIN i[544]
    DIRECTION INPUT ;
    USE SIGNAL ;
    PORT
      LAYER M3 ;
        RECT  54.864 0 54.882 0.038 ;
    END
  END i[544]
  PIN i[545]
    DIRECTION INPUT ;
    USE SIGNAL ;
    PORT
      LAYER M5 ;
        RECT  54.96 0 54.984 0.084 ;
    END
  END i[545]
  PIN i[546]
    DIRECTION INPUT ;
    USE SIGNAL ;
    PORT
      LAYER M3 ;
        RECT  55.08 0 55.098 0.038 ;
    END
  END i[546]
  PIN i[547]
    DIRECTION INPUT ;
    USE SIGNAL ;
    PORT
      LAYER M5 ;
        RECT  55.152 0 55.176 0.084 ;
    END
  END i[547]
  PIN i[548]
    DIRECTION INPUT ;
    USE SIGNAL ;
    PORT
      LAYER M3 ;
        RECT  55.26 0 55.278 0.038 ;
    END
  END i[548]
  PIN i[549]
    DIRECTION INPUT ;
    USE SIGNAL ;
    PORT
      LAYER M5 ;
        RECT  55.344 0 55.368 0.084 ;
    END
  END i[549]
  PIN i[54]
    DIRECTION INPUT ;
    USE SIGNAL ;
    PORT
      LAYER M3 ;
        RECT  6.012 0 6.03 0.038 ;
    END
  END i[54]
  PIN i[550]
    DIRECTION INPUT ;
    USE SIGNAL ;
    PORT
      LAYER M3 ;
        RECT  55.476 0 55.494 0.038 ;
    END
  END i[550]
  PIN i[551]
    DIRECTION INPUT ;
    USE SIGNAL ;
    PORT
      LAYER M5 ;
        RECT  55.584 0 55.608 0.084 ;
    END
  END i[551]
  PIN i[552]
    DIRECTION INPUT ;
    USE SIGNAL ;
    PORT
      LAYER M3 ;
        RECT  55.656 0 55.674 0.038 ;
    END
  END i[552]
  PIN i[553]
    DIRECTION INPUT ;
    USE SIGNAL ;
    PORT
      LAYER M5 ;
        RECT  55.776 0 55.8 0.084 ;
    END
  END i[553]
  PIN i[554]
    DIRECTION INPUT ;
    USE SIGNAL ;
    PORT
      LAYER M3 ;
        RECT  55.872 0 55.89 0.038 ;
    END
  END i[554]
  PIN i[555]
    DIRECTION INPUT ;
    USE SIGNAL ;
    PORT
      LAYER M5 ;
        RECT  55.968 0 55.992 0.084 ;
    END
  END i[555]
  PIN i[556]
    DIRECTION INPUT ;
    USE SIGNAL ;
    PORT
      LAYER M3 ;
        RECT  56.052 0 56.07 0.038 ;
    END
  END i[556]
  PIN i[557]
    DIRECTION INPUT ;
    USE SIGNAL ;
    PORT
      LAYER M5 ;
        RECT  56.16 0 56.184 0.084 ;
    END
  END i[557]
  PIN i[558]
    DIRECTION INPUT ;
    USE SIGNAL ;
    PORT
      LAYER M3 ;
        RECT  56.268 0 56.286 0.038 ;
    END
  END i[558]
  PIN i[559]
    DIRECTION INPUT ;
    USE SIGNAL ;
    PORT
      LAYER M5 ;
        RECT  56.352 0 56.376 0.084 ;
    END
  END i[559]
  PIN i[55]
    DIRECTION INPUT ;
    USE SIGNAL ;
    PORT
      LAYER M5 ;
        RECT  6.144 0 6.168 0.084 ;
    END
  END i[55]
  PIN i[560]
    DIRECTION INPUT ;
    USE SIGNAL ;
    PORT
      LAYER M3 ;
        RECT  56.448 0 56.466 0.038 ;
    END
  END i[560]
  PIN i[561]
    DIRECTION INPUT ;
    USE SIGNAL ;
    PORT
      LAYER M5 ;
        RECT  56.544 0 56.568 0.084 ;
    END
  END i[561]
  PIN i[562]
    DIRECTION INPUT ;
    USE SIGNAL ;
    PORT
      LAYER M3 ;
        RECT  56.664 0 56.682 0.038 ;
    END
  END i[562]
  PIN i[563]
    DIRECTION INPUT ;
    USE SIGNAL ;
    PORT
      LAYER M5 ;
        RECT  56.736 0 56.76 0.084 ;
    END
  END i[563]
  PIN i[564]
    DIRECTION INPUT ;
    USE SIGNAL ;
    PORT
      LAYER M3 ;
        RECT  56.844 0 56.862 0.038 ;
    END
  END i[564]
  PIN i[565]
    DIRECTION INPUT ;
    USE SIGNAL ;
    PORT
      LAYER M5 ;
        RECT  56.976 0 57 0.084 ;
    END
  END i[565]
  PIN i[566]
    DIRECTION INPUT ;
    USE SIGNAL ;
    PORT
      LAYER M3 ;
        RECT  57.06 0 57.078 0.038 ;
    END
  END i[566]
  PIN i[567]
    DIRECTION INPUT ;
    USE SIGNAL ;
    PORT
      LAYER M5 ;
        RECT  57.168 0 57.192 0.084 ;
    END
  END i[567]
  PIN i[568]
    DIRECTION INPUT ;
    USE SIGNAL ;
    PORT
      LAYER M3 ;
        RECT  57.276 0 57.294 0.038 ;
    END
  END i[568]
  PIN i[569]
    DIRECTION INPUT ;
    USE SIGNAL ;
    PORT
      LAYER M5 ;
        RECT  57.36 0 57.384 0.084 ;
    END
  END i[569]
  PIN i[56]
    DIRECTION INPUT ;
    USE SIGNAL ;
    PORT
      LAYER M3 ;
        RECT  6.228 0 6.246 0.038 ;
    END
  END i[56]
  PIN i[570]
    DIRECTION INPUT ;
    USE SIGNAL ;
    PORT
      LAYER M3 ;
        RECT  57.456 0 57.474 0.038 ;
    END
  END i[570]
  PIN i[571]
    DIRECTION INPUT ;
    USE SIGNAL ;
    PORT
      LAYER M5 ;
        RECT  57.552 0 57.576 0.084 ;
    END
  END i[571]
  PIN i[572]
    DIRECTION INPUT ;
    USE SIGNAL ;
    PORT
      LAYER M3 ;
        RECT  57.672 0 57.69 0.038 ;
    END
  END i[572]
  PIN i[573]
    DIRECTION INPUT ;
    USE SIGNAL ;
    PORT
      LAYER M5 ;
        RECT  57.744 0 57.768 0.084 ;
    END
  END i[573]
  PIN i[574]
    DIRECTION INPUT ;
    USE SIGNAL ;
    PORT
      LAYER M3 ;
        RECT  57.852 0 57.87 0.038 ;
    END
  END i[574]
  PIN i[575]
    DIRECTION INPUT ;
    USE SIGNAL ;
    PORT
      LAYER M5 ;
        RECT  57.936 0 57.96 0.084 ;
    END
  END i[575]
  PIN i[576]
    DIRECTION INPUT ;
    USE SIGNAL ;
    PORT
      LAYER M3 ;
        RECT  58.068 0 58.086 0.038 ;
    END
  END i[576]
  PIN i[577]
    DIRECTION INPUT ;
    USE SIGNAL ;
    PORT
      LAYER M5 ;
        RECT  58.176 0 58.2 0.084 ;
    END
  END i[577]
  PIN i[578]
    DIRECTION INPUT ;
    USE SIGNAL ;
    PORT
      LAYER M3 ;
        RECT  58.248 0 58.266 0.038 ;
    END
  END i[578]
  PIN i[579]
    DIRECTION INPUT ;
    USE SIGNAL ;
    PORT
      LAYER M5 ;
        RECT  58.368 0 58.392 0.084 ;
    END
  END i[579]
  PIN i[57]
    DIRECTION INPUT ;
    USE SIGNAL ;
    PORT
      LAYER M5 ;
        RECT  6.336 0 6.36 0.084 ;
    END
  END i[57]
  PIN i[580]
    DIRECTION INPUT ;
    USE SIGNAL ;
    PORT
      LAYER M3 ;
        RECT  58.464 0 58.482 0.038 ;
    END
  END i[580]
  PIN i[581]
    DIRECTION INPUT ;
    USE SIGNAL ;
    PORT
      LAYER M5 ;
        RECT  58.56 0 58.584 0.084 ;
    END
  END i[581]
  PIN i[582]
    DIRECTION INPUT ;
    USE SIGNAL ;
    PORT
      LAYER M3 ;
        RECT  58.644 0 58.662 0.038 ;
    END
  END i[582]
  PIN i[583]
    DIRECTION INPUT ;
    USE SIGNAL ;
    PORT
      LAYER M5 ;
        RECT  58.752 0 58.776 0.084 ;
    END
  END i[583]
  PIN i[584]
    DIRECTION INPUT ;
    USE SIGNAL ;
    PORT
      LAYER M3 ;
        RECT  58.86 0 58.878 0.038 ;
    END
  END i[584]
  PIN i[585]
    DIRECTION INPUT ;
    USE SIGNAL ;
    PORT
      LAYER M5 ;
        RECT  58.944 0 58.968 0.084 ;
    END
  END i[585]
  PIN i[586]
    DIRECTION INPUT ;
    USE SIGNAL ;
    PORT
      LAYER M3 ;
        RECT  59.04 0 59.058 0.038 ;
    END
  END i[586]
  PIN i[587]
    DIRECTION INPUT ;
    USE SIGNAL ;
    PORT
      LAYER M5 ;
        RECT  59.136 0 59.16 0.084 ;
    END
  END i[587]
  PIN i[588]
    DIRECTION INPUT ;
    USE SIGNAL ;
    PORT
      LAYER M3 ;
        RECT  59.256 0 59.274 0.038 ;
    END
  END i[588]
  PIN i[589]
    DIRECTION INPUT ;
    USE SIGNAL ;
    PORT
      LAYER M5 ;
        RECT  59.328 0 59.352 0.084 ;
    END
  END i[589]
  PIN i[58]
    DIRECTION INPUT ;
    USE SIGNAL ;
    PORT
      LAYER M3 ;
        RECT  6.408 0 6.426 0.038 ;
    END
  END i[58]
  PIN i[590]
    DIRECTION INPUT ;
    USE SIGNAL ;
    PORT
      LAYER M3 ;
        RECT  59.436 0 59.454 0.038 ;
    END
  END i[590]
  PIN i[591]
    DIRECTION INPUT ;
    USE SIGNAL ;
    PORT
      LAYER M5 ;
        RECT  59.568 0 59.592 0.084 ;
    END
  END i[591]
  PIN i[592]
    DIRECTION INPUT ;
    USE SIGNAL ;
    PORT
      LAYER M3 ;
        RECT  59.652 0 59.67 0.038 ;
    END
  END i[592]
  PIN i[593]
    DIRECTION INPUT ;
    USE SIGNAL ;
    PORT
      LAYER M5 ;
        RECT  59.76 0 59.784 0.084 ;
    END
  END i[593]
  PIN i[594]
    DIRECTION INPUT ;
    USE SIGNAL ;
    PORT
      LAYER M3 ;
        RECT  59.868 0 59.886 0.038 ;
    END
  END i[594]
  PIN i[595]
    DIRECTION INPUT ;
    USE SIGNAL ;
    PORT
      LAYER M5 ;
        RECT  59.952 0 59.976 0.084 ;
    END
  END i[595]
  PIN i[596]
    DIRECTION INPUT ;
    USE SIGNAL ;
    PORT
      LAYER M3 ;
        RECT  60.048 0 60.066 0.038 ;
    END
  END i[596]
  PIN i[597]
    DIRECTION INPUT ;
    USE SIGNAL ;
    PORT
      LAYER M5 ;
        RECT  60.144 0 60.168 0.084 ;
    END
  END i[597]
  PIN i[598]
    DIRECTION INPUT ;
    USE SIGNAL ;
    PORT
      LAYER M3 ;
        RECT  60.264 0 60.282 0.038 ;
    END
  END i[598]
  PIN i[599]
    DIRECTION INPUT ;
    USE SIGNAL ;
    PORT
      LAYER M5 ;
        RECT  60.336 0 60.36 0.084 ;
    END
  END i[599]
  PIN i[59]
    DIRECTION INPUT ;
    USE SIGNAL ;
    PORT
      LAYER M5 ;
        RECT  6.528 0 6.552 0.084 ;
    END
  END i[59]
  PIN i[5]
    DIRECTION INPUT ;
    USE SIGNAL ;
    PORT
      LAYER M5 ;
        RECT  1.152 0 1.176 0.084 ;
    END
  END i[5]
  PIN i[600]
    DIRECTION INPUT ;
    USE SIGNAL ;
    PORT
      LAYER M3 ;
        RECT  60.444 0 60.462 0.038 ;
    END
  END i[600]
  PIN i[601]
    DIRECTION INPUT ;
    USE SIGNAL ;
    PORT
      LAYER M5 ;
        RECT  60.528 0 60.552 0.084 ;
    END
  END i[601]
  PIN i[602]
    DIRECTION INPUT ;
    USE SIGNAL ;
    PORT
      LAYER M3 ;
        RECT  60.66 0 60.678 0.038 ;
    END
  END i[602]
  PIN i[603]
    DIRECTION INPUT ;
    USE SIGNAL ;
    PORT
      LAYER M5 ;
        RECT  60.768 0 60.792 0.084 ;
    END
  END i[603]
  PIN i[604]
    DIRECTION INPUT ;
    USE SIGNAL ;
    PORT
      LAYER M3 ;
        RECT  60.84 0 60.858 0.038 ;
    END
  END i[604]
  PIN i[605]
    DIRECTION INPUT ;
    USE SIGNAL ;
    PORT
      LAYER M5 ;
        RECT  60.96 0 60.984 0.084 ;
    END
  END i[605]
  PIN i[606]
    DIRECTION INPUT ;
    USE SIGNAL ;
    PORT
      LAYER M3 ;
        RECT  61.056 0 61.074 0.038 ;
    END
  END i[606]
  PIN i[607]
    DIRECTION INPUT ;
    USE SIGNAL ;
    PORT
      LAYER M5 ;
        RECT  61.152 0 61.176 0.084 ;
    END
  END i[607]
  PIN i[608]
    DIRECTION INPUT ;
    USE SIGNAL ;
    PORT
      LAYER M3 ;
        RECT  61.236 0 61.254 0.038 ;
    END
  END i[608]
  PIN i[609]
    DIRECTION INPUT ;
    USE SIGNAL ;
    PORT
      LAYER M5 ;
        RECT  61.344 0 61.368 0.084 ;
    END
  END i[609]
  PIN i[60]
    DIRECTION INPUT ;
    USE SIGNAL ;
    PORT
      LAYER M3 ;
        RECT  6.624 0 6.642 0.038 ;
    END
  END i[60]
  PIN i[610]
    DIRECTION INPUT ;
    USE SIGNAL ;
    PORT
      LAYER M3 ;
        RECT  61.452 0 61.47 0.038 ;
    END
  END i[610]
  PIN i[611]
    DIRECTION INPUT ;
    USE SIGNAL ;
    PORT
      LAYER M5 ;
        RECT  61.536 0 61.56 0.084 ;
    END
  END i[611]
  PIN i[612]
    DIRECTION INPUT ;
    USE SIGNAL ;
    PORT
      LAYER M3 ;
        RECT  61.632 0 61.65 0.038 ;
    END
  END i[612]
  PIN i[613]
    DIRECTION INPUT ;
    USE SIGNAL ;
    PORT
      LAYER M5 ;
        RECT  61.728 0 61.752 0.084 ;
    END
  END i[613]
  PIN i[614]
    DIRECTION INPUT ;
    USE SIGNAL ;
    PORT
      LAYER M3 ;
        RECT  61.848 0 61.866 0.038 ;
    END
  END i[614]
  PIN i[615]
    DIRECTION INPUT ;
    USE SIGNAL ;
    PORT
      LAYER M5 ;
        RECT  61.92 0 61.944 0.084 ;
    END
  END i[615]
  PIN i[616]
    DIRECTION INPUT ;
    USE SIGNAL ;
    PORT
      LAYER M3 ;
        RECT  62.028 0 62.046 0.038 ;
    END
  END i[616]
  PIN i[617]
    DIRECTION INPUT ;
    USE SIGNAL ;
    PORT
      LAYER M5 ;
        RECT  62.16 0 62.184 0.084 ;
    END
  END i[617]
  PIN i[618]
    DIRECTION INPUT ;
    USE SIGNAL ;
    PORT
      LAYER M3 ;
        RECT  62.244 0 62.262 0.038 ;
    END
  END i[618]
  PIN i[619]
    DIRECTION INPUT ;
    USE SIGNAL ;
    PORT
      LAYER M5 ;
        RECT  62.352 0 62.376 0.084 ;
    END
  END i[619]
  PIN i[61]
    DIRECTION INPUT ;
    USE SIGNAL ;
    PORT
      LAYER M5 ;
        RECT  6.72 0 6.744 0.084 ;
    END
  END i[61]
  PIN i[620]
    DIRECTION INPUT ;
    USE SIGNAL ;
    PORT
      LAYER M3 ;
        RECT  62.46 0 62.478 0.038 ;
    END
  END i[620]
  PIN i[621]
    DIRECTION INPUT ;
    USE SIGNAL ;
    PORT
      LAYER M5 ;
        RECT  62.544 0 62.568 0.084 ;
    END
  END i[621]
  PIN i[622]
    DIRECTION INPUT ;
    USE SIGNAL ;
    PORT
      LAYER M3 ;
        RECT  62.64 0 62.658 0.038 ;
    END
  END i[622]
  PIN i[623]
    DIRECTION INPUT ;
    USE SIGNAL ;
    PORT
      LAYER M5 ;
        RECT  62.736 0 62.76 0.084 ;
    END
  END i[623]
  PIN i[62]
    DIRECTION INPUT ;
    USE SIGNAL ;
    PORT
      LAYER M3 ;
        RECT  6.804 0 6.822 0.038 ;
    END
  END i[62]
  PIN i[63]
    DIRECTION INPUT ;
    USE SIGNAL ;
    PORT
      LAYER M5 ;
        RECT  6.912 0 6.936 0.084 ;
    END
  END i[63]
  PIN i[64]
    DIRECTION INPUT ;
    USE SIGNAL ;
    PORT
      LAYER M3 ;
        RECT  7.02 0 7.038 0.038 ;
    END
  END i[64]
  PIN i[65]
    DIRECTION INPUT ;
    USE SIGNAL ;
    PORT
      LAYER M5 ;
        RECT  7.104 0 7.128 0.084 ;
    END
  END i[65]
  PIN i[66]
    DIRECTION INPUT ;
    USE SIGNAL ;
    PORT
      LAYER M3 ;
        RECT  7.236 0 7.254 0.038 ;
    END
  END i[66]
  PIN i[67]
    DIRECTION INPUT ;
    USE SIGNAL ;
    PORT
      LAYER M5 ;
        RECT  7.296 0 7.32 0.084 ;
    END
  END i[67]
  PIN i[68]
    DIRECTION INPUT ;
    USE SIGNAL ;
    PORT
      LAYER M3 ;
        RECT  7.416 0 7.434 0.038 ;
    END
  END i[68]
  PIN i[69]
    DIRECTION INPUT ;
    USE SIGNAL ;
    PORT
      LAYER M5 ;
        RECT  7.536 0 7.56 0.084 ;
    END
  END i[69]
  PIN i[6]
    DIRECTION INPUT ;
    USE SIGNAL ;
    PORT
      LAYER M3 ;
        RECT  1.224 0 1.242 0.038 ;
    END
  END i[6]
  PIN i[70]
    DIRECTION INPUT ;
    USE SIGNAL ;
    PORT
      LAYER M3 ;
        RECT  7.632 0 7.65 0.038 ;
    END
  END i[70]
  PIN i[71]
    DIRECTION INPUT ;
    USE SIGNAL ;
    PORT
      LAYER M5 ;
        RECT  7.728 0 7.752 0.084 ;
    END
  END i[71]
  PIN i[72]
    DIRECTION INPUT ;
    USE SIGNAL ;
    PORT
      LAYER M3 ;
        RECT  7.812 0 7.83 0.038 ;
    END
  END i[72]
  PIN i[73]
    DIRECTION INPUT ;
    USE SIGNAL ;
    PORT
      LAYER M5 ;
        RECT  7.92 0 7.944 0.084 ;
    END
  END i[73]
  PIN i[74]
    DIRECTION INPUT ;
    USE SIGNAL ;
    PORT
      LAYER M3 ;
        RECT  8.028 0 8.046 0.038 ;
    END
  END i[74]
  PIN i[75]
    DIRECTION INPUT ;
    USE SIGNAL ;
    PORT
      LAYER M5 ;
        RECT  8.112 0 8.136 0.084 ;
    END
  END i[75]
  PIN i[76]
    DIRECTION INPUT ;
    USE SIGNAL ;
    PORT
      LAYER M3 ;
        RECT  8.208 0 8.226 0.038 ;
    END
  END i[76]
  PIN i[77]
    DIRECTION INPUT ;
    USE SIGNAL ;
    PORT
      LAYER M5 ;
        RECT  8.304 0 8.328 0.084 ;
    END
  END i[77]
  PIN i[78]
    DIRECTION INPUT ;
    USE SIGNAL ;
    PORT
      LAYER M3 ;
        RECT  8.424 0 8.442 0.038 ;
    END
  END i[78]
  PIN i[79]
    DIRECTION INPUT ;
    USE SIGNAL ;
    PORT
      LAYER M5 ;
        RECT  8.496 0 8.52 0.084 ;
    END
  END i[79]
  PIN i[7]
    DIRECTION INPUT ;
    USE SIGNAL ;
    PORT
      LAYER M5 ;
        RECT  1.344 0 1.368 0.084 ;
    END
  END i[7]
  PIN i[80]
    DIRECTION INPUT ;
    USE SIGNAL ;
    PORT
      LAYER M3 ;
        RECT  8.604 0 8.622 0.038 ;
    END
  END i[80]
  PIN i[81]
    DIRECTION INPUT ;
    USE SIGNAL ;
    PORT
      LAYER M5 ;
        RECT  8.736 0 8.76 0.084 ;
    END
  END i[81]
  PIN i[82]
    DIRECTION INPUT ;
    USE SIGNAL ;
    PORT
      LAYER M3 ;
        RECT  8.82 0 8.838 0.038 ;
    END
  END i[82]
  PIN i[83]
    DIRECTION INPUT ;
    USE SIGNAL ;
    PORT
      LAYER M5 ;
        RECT  8.928 0 8.952 0.084 ;
    END
  END i[83]
  PIN i[84]
    DIRECTION INPUT ;
    USE SIGNAL ;
    PORT
      LAYER M3 ;
        RECT  9 0 9.018 0.038 ;
    END
  END i[84]
  PIN i[85]
    DIRECTION INPUT ;
    USE SIGNAL ;
    PORT
      LAYER M5 ;
        RECT  9.12 0 9.144 0.084 ;
    END
  END i[85]
  PIN i[86]
    DIRECTION INPUT ;
    USE SIGNAL ;
    PORT
      LAYER M3 ;
        RECT  9.216 0 9.234 0.038 ;
    END
  END i[86]
  PIN i[87]
    DIRECTION INPUT ;
    USE SIGNAL ;
    PORT
      LAYER M5 ;
        RECT  9.312 0 9.336 0.084 ;
    END
  END i[87]
  PIN i[88]
    DIRECTION INPUT ;
    USE SIGNAL ;
    PORT
      LAYER M3 ;
        RECT  9.396 0 9.414 0.038 ;
    END
  END i[88]
  PIN i[89]
    DIRECTION INPUT ;
    USE SIGNAL ;
    PORT
      LAYER M5 ;
        RECT  9.504 0 9.528 0.084 ;
    END
  END i[89]
  PIN i[8]
    DIRECTION INPUT ;
    USE SIGNAL ;
    PORT
      LAYER M3 ;
        RECT  1.44 0 1.458 0.038 ;
    END
  END i[8]
  PIN i[90]
    DIRECTION INPUT ;
    USE SIGNAL ;
    PORT
      LAYER M3 ;
        RECT  9.612 0 9.63 0.038 ;
    END
  END i[90]
  PIN i[91]
    DIRECTION INPUT ;
    USE SIGNAL ;
    PORT
      LAYER M5 ;
        RECT  9.696 0 9.72 0.084 ;
    END
  END i[91]
  PIN i[92]
    DIRECTION INPUT ;
    USE SIGNAL ;
    PORT
      LAYER M3 ;
        RECT  9.828 0 9.846 0.038 ;
    END
  END i[92]
  PIN i[93]
    DIRECTION INPUT ;
    USE SIGNAL ;
    PORT
      LAYER M5 ;
        RECT  9.888 0 9.912 0.084 ;
    END
  END i[93]
  PIN i[94]
    DIRECTION INPUT ;
    USE SIGNAL ;
    PORT
      LAYER M3 ;
        RECT  10.008 0 10.026 0.038 ;
    END
  END i[94]
  PIN i[95]
    DIRECTION INPUT ;
    USE SIGNAL ;
    PORT
      LAYER M5 ;
        RECT  10.128 0 10.152 0.084 ;
    END
  END i[95]
  PIN i[96]
    DIRECTION INPUT ;
    USE SIGNAL ;
    PORT
      LAYER M3 ;
        RECT  10.224 0 10.242 0.038 ;
    END
  END i[96]
  PIN i[97]
    DIRECTION INPUT ;
    USE SIGNAL ;
    PORT
      LAYER M5 ;
        RECT  10.32 0 10.344 0.084 ;
    END
  END i[97]
  PIN i[98]
    DIRECTION INPUT ;
    USE SIGNAL ;
    PORT
      LAYER M3 ;
        RECT  10.404 0 10.422 0.038 ;
    END
  END i[98]
  PIN i[99]
    DIRECTION INPUT ;
    USE SIGNAL ;
    PORT
      LAYER M5 ;
        RECT  10.512 0 10.536 0.084 ;
    END
  END i[99]
  PIN i[9]
    DIRECTION INPUT ;
    USE SIGNAL ;
    PORT
      LAYER M5 ;
        RECT  1.536 0 1.56 0.084 ;
    END
  END i[9]
  PIN o[0]
    DIRECTION OUTPUT ;
    USE SIGNAL ;
    PORT
      LAYER M3 ;
        RECT  0.648 23.722 0.666 23.76 ;
    END
  END o[0]
  PIN o[100]
    DIRECTION OUTPUT ;
    USE SIGNAL ;
    PORT
      LAYER M3 ;
        RECT  10.62 23.722 10.638 23.76 ;
    END
  END o[100]
  PIN o[101]
    DIRECTION OUTPUT ;
    USE SIGNAL ;
    PORT
      LAYER M5 ;
        RECT  10.704 23.676 10.728 23.76 ;
    END
  END o[101]
  PIN o[102]
    DIRECTION OUTPUT ;
    USE SIGNAL ;
    PORT
      LAYER M3 ;
        RECT  10.8 23.722 10.818 23.76 ;
    END
  END o[102]
  PIN o[103]
    DIRECTION OUTPUT ;
    USE SIGNAL ;
    PORT
      LAYER M5 ;
        RECT  10.896 23.676 10.92 23.76 ;
    END
  END o[103]
  PIN o[104]
    DIRECTION OUTPUT ;
    USE SIGNAL ;
    PORT
      LAYER M3 ;
        RECT  11.016 23.722 11.034 23.76 ;
    END
  END o[104]
  PIN o[105]
    DIRECTION OUTPUT ;
    USE SIGNAL ;
    PORT
      LAYER M5 ;
        RECT  11.088 23.676 11.112 23.76 ;
    END
  END o[105]
  PIN o[106]
    DIRECTION OUTPUT ;
    USE SIGNAL ;
    PORT
      LAYER M3 ;
        RECT  11.196 23.722 11.214 23.76 ;
    END
  END o[106]
  PIN o[107]
    DIRECTION OUTPUT ;
    USE SIGNAL ;
    PORT
      LAYER M5 ;
        RECT  11.328 23.676 11.352 23.76 ;
    END
  END o[107]
  PIN o[108]
    DIRECTION OUTPUT ;
    USE SIGNAL ;
    PORT
      LAYER M3 ;
        RECT  11.412 23.722 11.43 23.76 ;
    END
  END o[108]
  PIN o[109]
    DIRECTION OUTPUT ;
    USE SIGNAL ;
    PORT
      LAYER M5 ;
        RECT  11.52 23.676 11.544 23.76 ;
    END
  END o[109]
  PIN o[10]
    DIRECTION OUTPUT ;
    USE SIGNAL ;
    PORT
      LAYER M3 ;
        RECT  1.656 23.722 1.674 23.76 ;
    END
  END o[10]
  PIN o[110]
    DIRECTION OUTPUT ;
    USE SIGNAL ;
    PORT
      LAYER M3 ;
        RECT  11.592 23.722 11.61 23.76 ;
    END
  END o[110]
  PIN o[111]
    DIRECTION OUTPUT ;
    USE SIGNAL ;
    PORT
      LAYER M5 ;
        RECT  11.712 23.676 11.736 23.76 ;
    END
  END o[111]
  PIN o[112]
    DIRECTION OUTPUT ;
    USE SIGNAL ;
    PORT
      LAYER M3 ;
        RECT  11.808 23.722 11.826 23.76 ;
    END
  END o[112]
  PIN o[113]
    DIRECTION OUTPUT ;
    USE SIGNAL ;
    PORT
      LAYER M5 ;
        RECT  11.904 23.676 11.928 23.76 ;
    END
  END o[113]
  PIN o[114]
    DIRECTION OUTPUT ;
    USE SIGNAL ;
    PORT
      LAYER M3 ;
        RECT  11.988 23.722 12.006 23.76 ;
    END
  END o[114]
  PIN o[115]
    DIRECTION OUTPUT ;
    USE SIGNAL ;
    PORT
      LAYER M5 ;
        RECT  12.096 23.676 12.12 23.76 ;
    END
  END o[115]
  PIN o[116]
    DIRECTION OUTPUT ;
    USE SIGNAL ;
    PORT
      LAYER M3 ;
        RECT  12.204 23.722 12.222 23.76 ;
    END
  END o[116]
  PIN o[117]
    DIRECTION OUTPUT ;
    USE SIGNAL ;
    PORT
      LAYER M5 ;
        RECT  12.288 23.676 12.312 23.76 ;
    END
  END o[117]
  PIN o[118]
    DIRECTION OUTPUT ;
    USE SIGNAL ;
    PORT
      LAYER M3 ;
        RECT  12.42 23.722 12.438 23.76 ;
    END
  END o[118]
  PIN o[119]
    DIRECTION OUTPUT ;
    USE SIGNAL ;
    PORT
      LAYER M5 ;
        RECT  12.48 23.676 12.504 23.76 ;
    END
  END o[119]
  PIN o[11]
    DIRECTION OUTPUT ;
    USE SIGNAL ;
    PORT
      LAYER M5 ;
        RECT  1.728 23.676 1.752 23.76 ;
    END
  END o[11]
  PIN o[120]
    DIRECTION OUTPUT ;
    USE SIGNAL ;
    PORT
      LAYER M3 ;
        RECT  12.6 23.722 12.618 23.76 ;
    END
  END o[120]
  PIN o[121]
    DIRECTION OUTPUT ;
    USE SIGNAL ;
    PORT
      LAYER M5 ;
        RECT  12.72 23.676 12.744 23.76 ;
    END
  END o[121]
  PIN o[122]
    DIRECTION OUTPUT ;
    USE SIGNAL ;
    PORT
      LAYER M3 ;
        RECT  12.816 23.722 12.834 23.76 ;
    END
  END o[122]
  PIN o[123]
    DIRECTION OUTPUT ;
    USE SIGNAL ;
    PORT
      LAYER M5 ;
        RECT  12.912 23.676 12.936 23.76 ;
    END
  END o[123]
  PIN o[124]
    DIRECTION OUTPUT ;
    USE SIGNAL ;
    PORT
      LAYER M3 ;
        RECT  12.996 23.722 13.014 23.76 ;
    END
  END o[124]
  PIN o[125]
    DIRECTION OUTPUT ;
    USE SIGNAL ;
    PORT
      LAYER M5 ;
        RECT  13.104 23.676 13.128 23.76 ;
    END
  END o[125]
  PIN o[126]
    DIRECTION OUTPUT ;
    USE SIGNAL ;
    PORT
      LAYER M3 ;
        RECT  13.212 23.722 13.23 23.76 ;
    END
  END o[126]
  PIN o[127]
    DIRECTION OUTPUT ;
    USE SIGNAL ;
    PORT
      LAYER M5 ;
        RECT  13.296 23.676 13.32 23.76 ;
    END
  END o[127]
  PIN o[128]
    DIRECTION OUTPUT ;
    USE SIGNAL ;
    PORT
      LAYER M3 ;
        RECT  13.392 23.722 13.41 23.76 ;
    END
  END o[128]
  PIN o[129]
    DIRECTION OUTPUT ;
    USE SIGNAL ;
    PORT
      LAYER M5 ;
        RECT  13.488 23.676 13.512 23.76 ;
    END
  END o[129]
  PIN o[12]
    DIRECTION OUTPUT ;
    USE SIGNAL ;
    PORT
      LAYER M3 ;
        RECT  1.836 23.722 1.854 23.76 ;
    END
  END o[12]
  PIN o[130]
    DIRECTION OUTPUT ;
    USE SIGNAL ;
    PORT
      LAYER M3 ;
        RECT  13.608 23.722 13.626 23.76 ;
    END
  END o[130]
  PIN o[131]
    DIRECTION OUTPUT ;
    USE SIGNAL ;
    PORT
      LAYER M5 ;
        RECT  13.68 23.676 13.704 23.76 ;
    END
  END o[131]
  PIN o[132]
    DIRECTION OUTPUT ;
    USE SIGNAL ;
    PORT
      LAYER M3 ;
        RECT  13.788 23.722 13.806 23.76 ;
    END
  END o[132]
  PIN o[133]
    DIRECTION OUTPUT ;
    USE SIGNAL ;
    PORT
      LAYER M5 ;
        RECT  13.872 23.676 13.896 23.76 ;
    END
  END o[133]
  PIN o[134]
    DIRECTION OUTPUT ;
    USE SIGNAL ;
    PORT
      LAYER M3 ;
        RECT  14.004 23.722 14.022 23.76 ;
    END
  END o[134]
  PIN o[135]
    DIRECTION OUTPUT ;
    USE SIGNAL ;
    PORT
      LAYER M5 ;
        RECT  14.112 23.676 14.136 23.76 ;
    END
  END o[135]
  PIN o[136]
    DIRECTION OUTPUT ;
    USE SIGNAL ;
    PORT
      LAYER M3 ;
        RECT  14.184 23.722 14.202 23.76 ;
    END
  END o[136]
  PIN o[137]
    DIRECTION OUTPUT ;
    USE SIGNAL ;
    PORT
      LAYER M5 ;
        RECT  14.304 23.676 14.328 23.76 ;
    END
  END o[137]
  PIN o[138]
    DIRECTION OUTPUT ;
    USE SIGNAL ;
    PORT
      LAYER M3 ;
        RECT  14.4 23.722 14.418 23.76 ;
    END
  END o[138]
  PIN o[139]
    DIRECTION OUTPUT ;
    USE SIGNAL ;
    PORT
      LAYER M5 ;
        RECT  14.496 23.676 14.52 23.76 ;
    END
  END o[139]
  PIN o[13]
    DIRECTION OUTPUT ;
    USE SIGNAL ;
    PORT
      LAYER M5 ;
        RECT  1.92 23.676 1.944 23.76 ;
    END
  END o[13]
  PIN o[140]
    DIRECTION OUTPUT ;
    USE SIGNAL ;
    PORT
      LAYER M3 ;
        RECT  14.58 23.722 14.598 23.76 ;
    END
  END o[140]
  PIN o[141]
    DIRECTION OUTPUT ;
    USE SIGNAL ;
    PORT
      LAYER M5 ;
        RECT  14.688 23.676 14.712 23.76 ;
    END
  END o[141]
  PIN o[142]
    DIRECTION OUTPUT ;
    USE SIGNAL ;
    PORT
      LAYER M3 ;
        RECT  14.796 23.722 14.814 23.76 ;
    END
  END o[142]
  PIN o[143]
    DIRECTION OUTPUT ;
    USE SIGNAL ;
    PORT
      LAYER M5 ;
        RECT  14.88 23.676 14.904 23.76 ;
    END
  END o[143]
  PIN o[144]
    DIRECTION OUTPUT ;
    USE SIGNAL ;
    PORT
      LAYER M3 ;
        RECT  15.012 23.722 15.03 23.76 ;
    END
  END o[144]
  PIN o[145]
    DIRECTION OUTPUT ;
    USE SIGNAL ;
    PORT
      LAYER M5 ;
        RECT  15.072 23.676 15.096 23.76 ;
    END
  END o[145]
  PIN o[146]
    DIRECTION OUTPUT ;
    USE SIGNAL ;
    PORT
      LAYER M3 ;
        RECT  15.192 23.722 15.21 23.76 ;
    END
  END o[146]
  PIN o[147]
    DIRECTION OUTPUT ;
    USE SIGNAL ;
    PORT
      LAYER M5 ;
        RECT  15.312 23.676 15.336 23.76 ;
    END
  END o[147]
  PIN o[148]
    DIRECTION OUTPUT ;
    USE SIGNAL ;
    PORT
      LAYER M3 ;
        RECT  15.408 23.722 15.426 23.76 ;
    END
  END o[148]
  PIN o[149]
    DIRECTION OUTPUT ;
    USE SIGNAL ;
    PORT
      LAYER M5 ;
        RECT  15.504 23.676 15.528 23.76 ;
    END
  END o[149]
  PIN o[14]
    DIRECTION OUTPUT ;
    USE SIGNAL ;
    PORT
      LAYER M3 ;
        RECT  2.052 23.722 2.07 23.76 ;
    END
  END o[14]
  PIN o[150]
    DIRECTION OUTPUT ;
    USE SIGNAL ;
    PORT
      LAYER M3 ;
        RECT  15.588 23.722 15.606 23.76 ;
    END
  END o[150]
  PIN o[151]
    DIRECTION OUTPUT ;
    USE SIGNAL ;
    PORT
      LAYER M5 ;
        RECT  15.696 23.676 15.72 23.76 ;
    END
  END o[151]
  PIN o[152]
    DIRECTION OUTPUT ;
    USE SIGNAL ;
    PORT
      LAYER M3 ;
        RECT  15.804 23.722 15.822 23.76 ;
    END
  END o[152]
  PIN o[153]
    DIRECTION OUTPUT ;
    USE SIGNAL ;
    PORT
      LAYER M5 ;
        RECT  15.888 23.676 15.912 23.76 ;
    END
  END o[153]
  PIN o[154]
    DIRECTION OUTPUT ;
    USE SIGNAL ;
    PORT
      LAYER M3 ;
        RECT  15.984 23.722 16.002 23.76 ;
    END
  END o[154]
  PIN o[155]
    DIRECTION OUTPUT ;
    USE SIGNAL ;
    PORT
      LAYER M5 ;
        RECT  16.08 23.676 16.104 23.76 ;
    END
  END o[155]
  PIN o[156]
    DIRECTION OUTPUT ;
    USE SIGNAL ;
    PORT
      LAYER M3 ;
        RECT  16.2 23.722 16.218 23.76 ;
    END
  END o[156]
  PIN o[157]
    DIRECTION OUTPUT ;
    USE SIGNAL ;
    PORT
      LAYER M5 ;
        RECT  16.272 23.676 16.296 23.76 ;
    END
  END o[157]
  PIN o[158]
    DIRECTION OUTPUT ;
    USE SIGNAL ;
    PORT
      LAYER M3 ;
        RECT  16.38 23.722 16.398 23.76 ;
    END
  END o[158]
  PIN o[159]
    DIRECTION OUTPUT ;
    USE SIGNAL ;
    PORT
      LAYER M5 ;
        RECT  16.464 23.676 16.488 23.76 ;
    END
  END o[159]
  PIN o[15]
    DIRECTION OUTPUT ;
    USE SIGNAL ;
    PORT
      LAYER M5 ;
        RECT  2.112 23.676 2.136 23.76 ;
    END
  END o[15]
  PIN o[160]
    DIRECTION OUTPUT ;
    USE SIGNAL ;
    PORT
      LAYER M3 ;
        RECT  16.596 23.722 16.614 23.76 ;
    END
  END o[160]
  PIN o[161]
    DIRECTION OUTPUT ;
    USE SIGNAL ;
    PORT
      LAYER M5 ;
        RECT  16.704 23.676 16.728 23.76 ;
    END
  END o[161]
  PIN o[162]
    DIRECTION OUTPUT ;
    USE SIGNAL ;
    PORT
      LAYER M3 ;
        RECT  16.776 23.722 16.794 23.76 ;
    END
  END o[162]
  PIN o[163]
    DIRECTION OUTPUT ;
    USE SIGNAL ;
    PORT
      LAYER M5 ;
        RECT  16.896 23.676 16.92 23.76 ;
    END
  END o[163]
  PIN o[164]
    DIRECTION OUTPUT ;
    USE SIGNAL ;
    PORT
      LAYER M3 ;
        RECT  16.992 23.722 17.01 23.76 ;
    END
  END o[164]
  PIN o[165]
    DIRECTION OUTPUT ;
    USE SIGNAL ;
    PORT
      LAYER M5 ;
        RECT  17.088 23.676 17.112 23.76 ;
    END
  END o[165]
  PIN o[166]
    DIRECTION OUTPUT ;
    USE SIGNAL ;
    PORT
      LAYER M3 ;
        RECT  17.172 23.722 17.19 23.76 ;
    END
  END o[166]
  PIN o[167]
    DIRECTION OUTPUT ;
    USE SIGNAL ;
    PORT
      LAYER M5 ;
        RECT  17.28 23.676 17.304 23.76 ;
    END
  END o[167]
  PIN o[168]
    DIRECTION OUTPUT ;
    USE SIGNAL ;
    PORT
      LAYER M3 ;
        RECT  17.388 23.722 17.406 23.76 ;
    END
  END o[168]
  PIN o[169]
    DIRECTION OUTPUT ;
    USE SIGNAL ;
    PORT
      LAYER M5 ;
        RECT  17.472 23.676 17.496 23.76 ;
    END
  END o[169]
  PIN o[16]
    DIRECTION OUTPUT ;
    USE SIGNAL ;
    PORT
      LAYER M3 ;
        RECT  2.232 23.722 2.25 23.76 ;
    END
  END o[16]
  PIN o[170]
    DIRECTION OUTPUT ;
    USE SIGNAL ;
    PORT
      LAYER M3 ;
        RECT  17.604 23.722 17.622 23.76 ;
    END
  END o[170]
  PIN o[171]
    DIRECTION OUTPUT ;
    USE SIGNAL ;
    PORT
      LAYER M5 ;
        RECT  17.664 23.676 17.688 23.76 ;
    END
  END o[171]
  PIN o[172]
    DIRECTION OUTPUT ;
    USE SIGNAL ;
    PORT
      LAYER M3 ;
        RECT  17.784 23.722 17.802 23.76 ;
    END
  END o[172]
  PIN o[173]
    DIRECTION OUTPUT ;
    USE SIGNAL ;
    PORT
      LAYER M5 ;
        RECT  17.904 23.676 17.928 23.76 ;
    END
  END o[173]
  PIN o[174]
    DIRECTION OUTPUT ;
    USE SIGNAL ;
    PORT
      LAYER M3 ;
        RECT  18 23.722 18.018 23.76 ;
    END
  END o[174]
  PIN o[175]
    DIRECTION OUTPUT ;
    USE SIGNAL ;
    PORT
      LAYER M5 ;
        RECT  18.096 23.676 18.12 23.76 ;
    END
  END o[175]
  PIN o[176]
    DIRECTION OUTPUT ;
    USE SIGNAL ;
    PORT
      LAYER M3 ;
        RECT  18.18 23.722 18.198 23.76 ;
    END
  END o[176]
  PIN o[177]
    DIRECTION OUTPUT ;
    USE SIGNAL ;
    PORT
      LAYER M5 ;
        RECT  18.288 23.676 18.312 23.76 ;
    END
  END o[177]
  PIN o[178]
    DIRECTION OUTPUT ;
    USE SIGNAL ;
    PORT
      LAYER M3 ;
        RECT  18.396 23.722 18.414 23.76 ;
    END
  END o[178]
  PIN o[179]
    DIRECTION OUTPUT ;
    USE SIGNAL ;
    PORT
      LAYER M5 ;
        RECT  18.48 23.676 18.504 23.76 ;
    END
  END o[179]
  PIN o[17]
    DIRECTION OUTPUT ;
    USE SIGNAL ;
    PORT
      LAYER M5 ;
        RECT  2.352 23.676 2.376 23.76 ;
    END
  END o[17]
  PIN o[180]
    DIRECTION OUTPUT ;
    USE SIGNAL ;
    PORT
      LAYER M3 ;
        RECT  18.576 23.722 18.594 23.76 ;
    END
  END o[180]
  PIN o[181]
    DIRECTION OUTPUT ;
    USE SIGNAL ;
    PORT
      LAYER M5 ;
        RECT  18.672 23.676 18.696 23.76 ;
    END
  END o[181]
  PIN o[182]
    DIRECTION OUTPUT ;
    USE SIGNAL ;
    PORT
      LAYER M3 ;
        RECT  18.792 23.722 18.81 23.76 ;
    END
  END o[182]
  PIN o[183]
    DIRECTION OUTPUT ;
    USE SIGNAL ;
    PORT
      LAYER M5 ;
        RECT  18.864 23.676 18.888 23.76 ;
    END
  END o[183]
  PIN o[184]
    DIRECTION OUTPUT ;
    USE SIGNAL ;
    PORT
      LAYER M3 ;
        RECT  18.972 23.722 18.99 23.76 ;
    END
  END o[184]
  PIN o[185]
    DIRECTION OUTPUT ;
    USE SIGNAL ;
    PORT
      LAYER M5 ;
        RECT  19.056 23.676 19.08 23.76 ;
    END
  END o[185]
  PIN o[186]
    DIRECTION OUTPUT ;
    USE SIGNAL ;
    PORT
      LAYER M3 ;
        RECT  19.188 23.722 19.206 23.76 ;
    END
  END o[186]
  PIN o[187]
    DIRECTION OUTPUT ;
    USE SIGNAL ;
    PORT
      LAYER M5 ;
        RECT  19.296 23.676 19.32 23.76 ;
    END
  END o[187]
  PIN o[188]
    DIRECTION OUTPUT ;
    USE SIGNAL ;
    PORT
      LAYER M3 ;
        RECT  19.368 23.722 19.386 23.76 ;
    END
  END o[188]
  PIN o[189]
    DIRECTION OUTPUT ;
    USE SIGNAL ;
    PORT
      LAYER M5 ;
        RECT  19.488 23.676 19.512 23.76 ;
    END
  END o[189]
  PIN o[18]
    DIRECTION OUTPUT ;
    USE SIGNAL ;
    PORT
      LAYER M3 ;
        RECT  2.448 23.722 2.466 23.76 ;
    END
  END o[18]
  PIN o[190]
    DIRECTION OUTPUT ;
    USE SIGNAL ;
    PORT
      LAYER M3 ;
        RECT  19.584 23.722 19.602 23.76 ;
    END
  END o[190]
  PIN o[191]
    DIRECTION OUTPUT ;
    USE SIGNAL ;
    PORT
      LAYER M5 ;
        RECT  19.68 23.676 19.704 23.76 ;
    END
  END o[191]
  PIN o[192]
    DIRECTION OUTPUT ;
    USE SIGNAL ;
    PORT
      LAYER M3 ;
        RECT  19.764 23.722 19.782 23.76 ;
    END
  END o[192]
  PIN o[193]
    DIRECTION OUTPUT ;
    USE SIGNAL ;
    PORT
      LAYER M5 ;
        RECT  19.872 23.676 19.896 23.76 ;
    END
  END o[193]
  PIN o[194]
    DIRECTION OUTPUT ;
    USE SIGNAL ;
    PORT
      LAYER M3 ;
        RECT  19.98 23.722 19.998 23.76 ;
    END
  END o[194]
  PIN o[195]
    DIRECTION OUTPUT ;
    USE SIGNAL ;
    PORT
      LAYER M5 ;
        RECT  20.064 23.676 20.088 23.76 ;
    END
  END o[195]
  PIN o[196]
    DIRECTION OUTPUT ;
    USE SIGNAL ;
    PORT
      LAYER M3 ;
        RECT  20.196 23.722 20.214 23.76 ;
    END
  END o[196]
  PIN o[197]
    DIRECTION OUTPUT ;
    USE SIGNAL ;
    PORT
      LAYER M5 ;
        RECT  20.256 23.676 20.28 23.76 ;
    END
  END o[197]
  PIN o[198]
    DIRECTION OUTPUT ;
    USE SIGNAL ;
    PORT
      LAYER M3 ;
        RECT  20.376 23.722 20.394 23.76 ;
    END
  END o[198]
  PIN o[199]
    DIRECTION OUTPUT ;
    USE SIGNAL ;
    PORT
      LAYER M5 ;
        RECT  20.496 23.676 20.52 23.76 ;
    END
  END o[199]
  PIN o[19]
    DIRECTION OUTPUT ;
    USE SIGNAL ;
    PORT
      LAYER M5 ;
        RECT  2.544 23.676 2.568 23.76 ;
    END
  END o[19]
  PIN o[1]
    DIRECTION OUTPUT ;
    USE SIGNAL ;
    PORT
      LAYER M5 ;
        RECT  0.72 23.676 0.744 23.76 ;
    END
  END o[1]
  PIN o[200]
    DIRECTION OUTPUT ;
    USE SIGNAL ;
    PORT
      LAYER M3 ;
        RECT  20.592 23.722 20.61 23.76 ;
    END
  END o[200]
  PIN o[201]
    DIRECTION OUTPUT ;
    USE SIGNAL ;
    PORT
      LAYER M5 ;
        RECT  20.688 23.676 20.712 23.76 ;
    END
  END o[201]
  PIN o[202]
    DIRECTION OUTPUT ;
    USE SIGNAL ;
    PORT
      LAYER M3 ;
        RECT  20.772 23.722 20.79 23.76 ;
    END
  END o[202]
  PIN o[203]
    DIRECTION OUTPUT ;
    USE SIGNAL ;
    PORT
      LAYER M5 ;
        RECT  20.88 23.676 20.904 23.76 ;
    END
  END o[203]
  PIN o[204]
    DIRECTION OUTPUT ;
    USE SIGNAL ;
    PORT
      LAYER M3 ;
        RECT  20.988 23.722 21.006 23.76 ;
    END
  END o[204]
  PIN o[205]
    DIRECTION OUTPUT ;
    USE SIGNAL ;
    PORT
      LAYER M5 ;
        RECT  21.072 23.676 21.096 23.76 ;
    END
  END o[205]
  PIN o[206]
    DIRECTION OUTPUT ;
    USE SIGNAL ;
    PORT
      LAYER M3 ;
        RECT  21.168 23.722 21.186 23.76 ;
    END
  END o[206]
  PIN o[207]
    DIRECTION OUTPUT ;
    USE SIGNAL ;
    PORT
      LAYER M5 ;
        RECT  21.264 23.676 21.288 23.76 ;
    END
  END o[207]
  PIN o[208]
    DIRECTION OUTPUT ;
    USE SIGNAL ;
    PORT
      LAYER M3 ;
        RECT  21.384 23.722 21.402 23.76 ;
    END
  END o[208]
  PIN o[209]
    DIRECTION OUTPUT ;
    USE SIGNAL ;
    PORT
      LAYER M5 ;
        RECT  21.456 23.676 21.48 23.76 ;
    END
  END o[209]
  PIN o[20]
    DIRECTION OUTPUT ;
    USE SIGNAL ;
    PORT
      LAYER M3 ;
        RECT  2.628 23.722 2.646 23.76 ;
    END
  END o[20]
  PIN o[210]
    DIRECTION OUTPUT ;
    USE SIGNAL ;
    PORT
      LAYER M3 ;
        RECT  21.564 23.722 21.582 23.76 ;
    END
  END o[210]
  PIN o[211]
    DIRECTION OUTPUT ;
    USE SIGNAL ;
    PORT
      LAYER M5 ;
        RECT  21.648 23.676 21.672 23.76 ;
    END
  END o[211]
  PIN o[212]
    DIRECTION OUTPUT ;
    USE SIGNAL ;
    PORT
      LAYER M3 ;
        RECT  21.78 23.722 21.798 23.76 ;
    END
  END o[212]
  PIN o[213]
    DIRECTION OUTPUT ;
    USE SIGNAL ;
    PORT
      LAYER M5 ;
        RECT  21.888 23.676 21.912 23.76 ;
    END
  END o[213]
  PIN o[214]
    DIRECTION OUTPUT ;
    USE SIGNAL ;
    PORT
      LAYER M3 ;
        RECT  21.96 23.722 21.978 23.76 ;
    END
  END o[214]
  PIN o[215]
    DIRECTION OUTPUT ;
    USE SIGNAL ;
    PORT
      LAYER M5 ;
        RECT  22.08 23.676 22.104 23.76 ;
    END
  END o[215]
  PIN o[216]
    DIRECTION OUTPUT ;
    USE SIGNAL ;
    PORT
      LAYER M3 ;
        RECT  22.176 23.722 22.194 23.76 ;
    END
  END o[216]
  PIN o[217]
    DIRECTION OUTPUT ;
    USE SIGNAL ;
    PORT
      LAYER M5 ;
        RECT  22.272 23.676 22.296 23.76 ;
    END
  END o[217]
  PIN o[218]
    DIRECTION OUTPUT ;
    USE SIGNAL ;
    PORT
      LAYER M3 ;
        RECT  22.356 23.722 22.374 23.76 ;
    END
  END o[218]
  PIN o[219]
    DIRECTION OUTPUT ;
    USE SIGNAL ;
    PORT
      LAYER M5 ;
        RECT  22.464 23.676 22.488 23.76 ;
    END
  END o[219]
  PIN o[21]
    DIRECTION OUTPUT ;
    USE SIGNAL ;
    PORT
      LAYER M5 ;
        RECT  2.736 23.676 2.76 23.76 ;
    END
  END o[21]
  PIN o[220]
    DIRECTION OUTPUT ;
    USE SIGNAL ;
    PORT
      LAYER M3 ;
        RECT  22.572 23.722 22.59 23.76 ;
    END
  END o[220]
  PIN o[221]
    DIRECTION OUTPUT ;
    USE SIGNAL ;
    PORT
      LAYER M5 ;
        RECT  22.656 23.676 22.68 23.76 ;
    END
  END o[221]
  PIN o[222]
    DIRECTION OUTPUT ;
    USE SIGNAL ;
    PORT
      LAYER M3 ;
        RECT  22.788 23.722 22.806 23.76 ;
    END
  END o[222]
  PIN o[223]
    DIRECTION OUTPUT ;
    USE SIGNAL ;
    PORT
      LAYER M5 ;
        RECT  22.848 23.676 22.872 23.76 ;
    END
  END o[223]
  PIN o[224]
    DIRECTION OUTPUT ;
    USE SIGNAL ;
    PORT
      LAYER M3 ;
        RECT  22.968 23.722 22.986 23.76 ;
    END
  END o[224]
  PIN o[225]
    DIRECTION OUTPUT ;
    USE SIGNAL ;
    PORT
      LAYER M5 ;
        RECT  23.088 23.676 23.112 23.76 ;
    END
  END o[225]
  PIN o[226]
    DIRECTION OUTPUT ;
    USE SIGNAL ;
    PORT
      LAYER M3 ;
        RECT  23.184 23.722 23.202 23.76 ;
    END
  END o[226]
  PIN o[227]
    DIRECTION OUTPUT ;
    USE SIGNAL ;
    PORT
      LAYER M5 ;
        RECT  23.28 23.676 23.304 23.76 ;
    END
  END o[227]
  PIN o[228]
    DIRECTION OUTPUT ;
    USE SIGNAL ;
    PORT
      LAYER M3 ;
        RECT  23.364 23.722 23.382 23.76 ;
    END
  END o[228]
  PIN o[229]
    DIRECTION OUTPUT ;
    USE SIGNAL ;
    PORT
      LAYER M5 ;
        RECT  23.472 23.676 23.496 23.76 ;
    END
  END o[229]
  PIN o[22]
    DIRECTION OUTPUT ;
    USE SIGNAL ;
    PORT
      LAYER M3 ;
        RECT  2.844 23.722 2.862 23.76 ;
    END
  END o[22]
  PIN o[230]
    DIRECTION OUTPUT ;
    USE SIGNAL ;
    PORT
      LAYER M3 ;
        RECT  23.58 23.722 23.598 23.76 ;
    END
  END o[230]
  PIN o[231]
    DIRECTION OUTPUT ;
    USE SIGNAL ;
    PORT
      LAYER M5 ;
        RECT  23.664 23.676 23.688 23.76 ;
    END
  END o[231]
  PIN o[232]
    DIRECTION OUTPUT ;
    USE SIGNAL ;
    PORT
      LAYER M3 ;
        RECT  23.76 23.722 23.778 23.76 ;
    END
  END o[232]
  PIN o[233]
    DIRECTION OUTPUT ;
    USE SIGNAL ;
    PORT
      LAYER M5 ;
        RECT  23.856 23.676 23.88 23.76 ;
    END
  END o[233]
  PIN o[234]
    DIRECTION OUTPUT ;
    USE SIGNAL ;
    PORT
      LAYER M3 ;
        RECT  23.976 23.722 23.994 23.76 ;
    END
  END o[234]
  PIN o[235]
    DIRECTION OUTPUT ;
    USE SIGNAL ;
    PORT
      LAYER M5 ;
        RECT  24.048 23.676 24.072 23.76 ;
    END
  END o[235]
  PIN o[236]
    DIRECTION OUTPUT ;
    USE SIGNAL ;
    PORT
      LAYER M3 ;
        RECT  24.156 23.722 24.174 23.76 ;
    END
  END o[236]
  PIN o[237]
    DIRECTION OUTPUT ;
    USE SIGNAL ;
    PORT
      LAYER M5 ;
        RECT  24.24 23.676 24.264 23.76 ;
    END
  END o[237]
  PIN o[238]
    DIRECTION OUTPUT ;
    USE SIGNAL ;
    PORT
      LAYER M3 ;
        RECT  24.372 23.722 24.39 23.76 ;
    END
  END o[238]
  PIN o[239]
    DIRECTION OUTPUT ;
    USE SIGNAL ;
    PORT
      LAYER M5 ;
        RECT  24.48 23.676 24.504 23.76 ;
    END
  END o[239]
  PIN o[23]
    DIRECTION OUTPUT ;
    USE SIGNAL ;
    PORT
      LAYER M5 ;
        RECT  2.928 23.676 2.952 23.76 ;
    END
  END o[23]
  PIN o[240]
    DIRECTION OUTPUT ;
    USE SIGNAL ;
    PORT
      LAYER M3 ;
        RECT  24.552 23.722 24.57 23.76 ;
    END
  END o[240]
  PIN o[241]
    DIRECTION OUTPUT ;
    USE SIGNAL ;
    PORT
      LAYER M5 ;
        RECT  24.672 23.676 24.696 23.76 ;
    END
  END o[241]
  PIN o[242]
    DIRECTION OUTPUT ;
    USE SIGNAL ;
    PORT
      LAYER M3 ;
        RECT  24.768 23.722 24.786 23.76 ;
    END
  END o[242]
  PIN o[243]
    DIRECTION OUTPUT ;
    USE SIGNAL ;
    PORT
      LAYER M5 ;
        RECT  24.864 23.676 24.888 23.76 ;
    END
  END o[243]
  PIN o[244]
    DIRECTION OUTPUT ;
    USE SIGNAL ;
    PORT
      LAYER M3 ;
        RECT  24.948 23.722 24.966 23.76 ;
    END
  END o[244]
  PIN o[245]
    DIRECTION OUTPUT ;
    USE SIGNAL ;
    PORT
      LAYER M5 ;
        RECT  25.056 23.676 25.08 23.76 ;
    END
  END o[245]
  PIN o[246]
    DIRECTION OUTPUT ;
    USE SIGNAL ;
    PORT
      LAYER M3 ;
        RECT  25.164 23.722 25.182 23.76 ;
    END
  END o[246]
  PIN o[247]
    DIRECTION OUTPUT ;
    USE SIGNAL ;
    PORT
      LAYER M5 ;
        RECT  25.248 23.676 25.272 23.76 ;
    END
  END o[247]
  PIN o[248]
    DIRECTION OUTPUT ;
    USE SIGNAL ;
    PORT
      LAYER M3 ;
        RECT  25.344 23.722 25.362 23.76 ;
    END
  END o[248]
  PIN o[249]
    DIRECTION OUTPUT ;
    USE SIGNAL ;
    PORT
      LAYER M5 ;
        RECT  25.44 23.676 25.464 23.76 ;
    END
  END o[249]
  PIN o[24]
    DIRECTION OUTPUT ;
    USE SIGNAL ;
    PORT
      LAYER M3 ;
        RECT  3.024 23.722 3.042 23.76 ;
    END
  END o[24]
  PIN o[250]
    DIRECTION OUTPUT ;
    USE SIGNAL ;
    PORT
      LAYER M3 ;
        RECT  25.56 23.722 25.578 23.76 ;
    END
  END o[250]
  PIN o[251]
    DIRECTION OUTPUT ;
    USE SIGNAL ;
    PORT
      LAYER M5 ;
        RECT  25.68 23.676 25.704 23.76 ;
    END
  END o[251]
  PIN o[252]
    DIRECTION OUTPUT ;
    USE SIGNAL ;
    PORT
      LAYER M3 ;
        RECT  25.776 23.722 25.794 23.76 ;
    END
  END o[252]
  PIN o[253]
    DIRECTION OUTPUT ;
    USE SIGNAL ;
    PORT
      LAYER M5 ;
        RECT  25.872 23.676 25.896 23.76 ;
    END
  END o[253]
  PIN o[254]
    DIRECTION OUTPUT ;
    USE SIGNAL ;
    PORT
      LAYER M3 ;
        RECT  25.956 23.722 25.974 23.76 ;
    END
  END o[254]
  PIN o[255]
    DIRECTION OUTPUT ;
    USE SIGNAL ;
    PORT
      LAYER M5 ;
        RECT  26.064 23.676 26.088 23.76 ;
    END
  END o[255]
  PIN o[256]
    DIRECTION OUTPUT ;
    USE SIGNAL ;
    PORT
      LAYER M3 ;
        RECT  26.172 23.722 26.19 23.76 ;
    END
  END o[256]
  PIN o[257]
    DIRECTION OUTPUT ;
    USE SIGNAL ;
    PORT
      LAYER M5 ;
        RECT  26.256 23.676 26.28 23.76 ;
    END
  END o[257]
  PIN o[258]
    DIRECTION OUTPUT ;
    USE SIGNAL ;
    PORT
      LAYER M3 ;
        RECT  26.352 23.722 26.37 23.76 ;
    END
  END o[258]
  PIN o[259]
    DIRECTION OUTPUT ;
    USE SIGNAL ;
    PORT
      LAYER M5 ;
        RECT  26.448 23.676 26.472 23.76 ;
    END
  END o[259]
  PIN o[25]
    DIRECTION OUTPUT ;
    USE SIGNAL ;
    PORT
      LAYER M5 ;
        RECT  3.12 23.676 3.144 23.76 ;
    END
  END o[25]
  PIN o[260]
    DIRECTION OUTPUT ;
    USE SIGNAL ;
    PORT
      LAYER M3 ;
        RECT  26.568 23.722 26.586 23.76 ;
    END
  END o[260]
  PIN o[261]
    DIRECTION OUTPUT ;
    USE SIGNAL ;
    PORT
      LAYER M5 ;
        RECT  26.64 23.676 26.664 23.76 ;
    END
  END o[261]
  PIN o[262]
    DIRECTION OUTPUT ;
    USE SIGNAL ;
    PORT
      LAYER M3 ;
        RECT  26.748 23.722 26.766 23.76 ;
    END
  END o[262]
  PIN o[263]
    DIRECTION OUTPUT ;
    USE SIGNAL ;
    PORT
      LAYER M5 ;
        RECT  26.832 23.676 26.856 23.76 ;
    END
  END o[263]
  PIN o[264]
    DIRECTION OUTPUT ;
    USE SIGNAL ;
    PORT
      LAYER M3 ;
        RECT  26.964 23.722 26.982 23.76 ;
    END
  END o[264]
  PIN o[265]
    DIRECTION OUTPUT ;
    USE SIGNAL ;
    PORT
      LAYER M5 ;
        RECT  27.072 23.676 27.096 23.76 ;
    END
  END o[265]
  PIN o[266]
    DIRECTION OUTPUT ;
    USE SIGNAL ;
    PORT
      LAYER M3 ;
        RECT  27.144 23.722 27.162 23.76 ;
    END
  END o[266]
  PIN o[267]
    DIRECTION OUTPUT ;
    USE SIGNAL ;
    PORT
      LAYER M5 ;
        RECT  27.264 23.676 27.288 23.76 ;
    END
  END o[267]
  PIN o[268]
    DIRECTION OUTPUT ;
    USE SIGNAL ;
    PORT
      LAYER M3 ;
        RECT  27.36 23.722 27.378 23.76 ;
    END
  END o[268]
  PIN o[269]
    DIRECTION OUTPUT ;
    USE SIGNAL ;
    PORT
      LAYER M5 ;
        RECT  27.456 23.676 27.48 23.76 ;
    END
  END o[269]
  PIN o[26]
    DIRECTION OUTPUT ;
    USE SIGNAL ;
    PORT
      LAYER M3 ;
        RECT  3.24 23.722 3.258 23.76 ;
    END
  END o[26]
  PIN o[270]
    DIRECTION OUTPUT ;
    USE SIGNAL ;
    PORT
      LAYER M3 ;
        RECT  27.54 23.722 27.558 23.76 ;
    END
  END o[270]
  PIN o[271]
    DIRECTION OUTPUT ;
    USE SIGNAL ;
    PORT
      LAYER M5 ;
        RECT  27.648 23.676 27.672 23.76 ;
    END
  END o[271]
  PIN o[272]
    DIRECTION OUTPUT ;
    USE SIGNAL ;
    PORT
      LAYER M3 ;
        RECT  27.756 23.722 27.774 23.76 ;
    END
  END o[272]
  PIN o[273]
    DIRECTION OUTPUT ;
    USE SIGNAL ;
    PORT
      LAYER M5 ;
        RECT  27.84 23.676 27.864 23.76 ;
    END
  END o[273]
  PIN o[274]
    DIRECTION OUTPUT ;
    USE SIGNAL ;
    PORT
      LAYER M3 ;
        RECT  27.936 23.722 27.954 23.76 ;
    END
  END o[274]
  PIN o[275]
    DIRECTION OUTPUT ;
    USE SIGNAL ;
    PORT
      LAYER M5 ;
        RECT  28.032 23.676 28.056 23.76 ;
    END
  END o[275]
  PIN o[276]
    DIRECTION OUTPUT ;
    USE SIGNAL ;
    PORT
      LAYER M3 ;
        RECT  28.152 23.722 28.17 23.76 ;
    END
  END o[276]
  PIN o[277]
    DIRECTION OUTPUT ;
    USE SIGNAL ;
    PORT
      LAYER M5 ;
        RECT  28.272 23.676 28.296 23.76 ;
    END
  END o[277]
  PIN o[278]
    DIRECTION OUTPUT ;
    USE SIGNAL ;
    PORT
      LAYER M3 ;
        RECT  28.368 23.722 28.386 23.76 ;
    END
  END o[278]
  PIN o[279]
    DIRECTION OUTPUT ;
    USE SIGNAL ;
    PORT
      LAYER M5 ;
        RECT  28.464 23.676 28.488 23.76 ;
    END
  END o[279]
  PIN o[27]
    DIRECTION OUTPUT ;
    USE SIGNAL ;
    PORT
      LAYER M5 ;
        RECT  3.312 23.676 3.336 23.76 ;
    END
  END o[27]
  PIN o[280]
    DIRECTION OUTPUT ;
    USE SIGNAL ;
    PORT
      LAYER M3 ;
        RECT  28.548 23.722 28.566 23.76 ;
    END
  END o[280]
  PIN o[281]
    DIRECTION OUTPUT ;
    USE SIGNAL ;
    PORT
      LAYER M5 ;
        RECT  28.656 23.676 28.68 23.76 ;
    END
  END o[281]
  PIN o[282]
    DIRECTION OUTPUT ;
    USE SIGNAL ;
    PORT
      LAYER M3 ;
        RECT  28.764 23.722 28.782 23.76 ;
    END
  END o[282]
  PIN o[283]
    DIRECTION OUTPUT ;
    USE SIGNAL ;
    PORT
      LAYER M5 ;
        RECT  28.848 23.676 28.872 23.76 ;
    END
  END o[283]
  PIN o[284]
    DIRECTION OUTPUT ;
    USE SIGNAL ;
    PORT
      LAYER M3 ;
        RECT  28.944 23.722 28.962 23.76 ;
    END
  END o[284]
  PIN o[285]
    DIRECTION OUTPUT ;
    USE SIGNAL ;
    PORT
      LAYER M5 ;
        RECT  29.04 23.676 29.064 23.76 ;
    END
  END o[285]
  PIN o[286]
    DIRECTION OUTPUT ;
    USE SIGNAL ;
    PORT
      LAYER M3 ;
        RECT  29.16 23.722 29.178 23.76 ;
    END
  END o[286]
  PIN o[287]
    DIRECTION OUTPUT ;
    USE SIGNAL ;
    PORT
      LAYER M5 ;
        RECT  29.232 23.676 29.256 23.76 ;
    END
  END o[287]
  PIN o[288]
    DIRECTION OUTPUT ;
    USE SIGNAL ;
    PORT
      LAYER M3 ;
        RECT  29.34 23.722 29.358 23.76 ;
    END
  END o[288]
  PIN o[289]
    DIRECTION OUTPUT ;
    USE SIGNAL ;
    PORT
      LAYER M5 ;
        RECT  29.424 23.676 29.448 23.76 ;
    END
  END o[289]
  PIN o[28]
    DIRECTION OUTPUT ;
    USE SIGNAL ;
    PORT
      LAYER M3 ;
        RECT  3.42 23.722 3.438 23.76 ;
    END
  END o[28]
  PIN o[290]
    DIRECTION OUTPUT ;
    USE SIGNAL ;
    PORT
      LAYER M3 ;
        RECT  29.556 23.722 29.574 23.76 ;
    END
  END o[290]
  PIN o[291]
    DIRECTION OUTPUT ;
    USE SIGNAL ;
    PORT
      LAYER M5 ;
        RECT  29.664 23.676 29.688 23.76 ;
    END
  END o[291]
  PIN o[292]
    DIRECTION OUTPUT ;
    USE SIGNAL ;
    PORT
      LAYER M3 ;
        RECT  29.736 23.722 29.754 23.76 ;
    END
  END o[292]
  PIN o[293]
    DIRECTION OUTPUT ;
    USE SIGNAL ;
    PORT
      LAYER M5 ;
        RECT  29.856 23.676 29.88 23.76 ;
    END
  END o[293]
  PIN o[294]
    DIRECTION OUTPUT ;
    USE SIGNAL ;
    PORT
      LAYER M3 ;
        RECT  29.952 23.722 29.97 23.76 ;
    END
  END o[294]
  PIN o[295]
    DIRECTION OUTPUT ;
    USE SIGNAL ;
    PORT
      LAYER M5 ;
        RECT  30.048 23.676 30.072 23.76 ;
    END
  END o[295]
  PIN o[296]
    DIRECTION OUTPUT ;
    USE SIGNAL ;
    PORT
      LAYER M3 ;
        RECT  30.132 23.722 30.15 23.76 ;
    END
  END o[296]
  PIN o[297]
    DIRECTION OUTPUT ;
    USE SIGNAL ;
    PORT
      LAYER M5 ;
        RECT  30.24 23.676 30.264 23.76 ;
    END
  END o[297]
  PIN o[298]
    DIRECTION OUTPUT ;
    USE SIGNAL ;
    PORT
      LAYER M3 ;
        RECT  30.348 23.722 30.366 23.76 ;
    END
  END o[298]
  PIN o[299]
    DIRECTION OUTPUT ;
    USE SIGNAL ;
    PORT
      LAYER M5 ;
        RECT  30.432 23.676 30.456 23.76 ;
    END
  END o[299]
  PIN o[29]
    DIRECTION OUTPUT ;
    USE SIGNAL ;
    PORT
      LAYER M5 ;
        RECT  3.552 23.676 3.576 23.76 ;
    END
  END o[29]
  PIN o[2]
    DIRECTION OUTPUT ;
    USE SIGNAL ;
    PORT
      LAYER M3 ;
        RECT  0.828 23.722 0.846 23.76 ;
    END
  END o[2]
  PIN o[300]
    DIRECTION OUTPUT ;
    USE SIGNAL ;
    PORT
      LAYER M3 ;
        RECT  30.528 23.722 30.546 23.76 ;
    END
  END o[300]
  PIN o[301]
    DIRECTION OUTPUT ;
    USE SIGNAL ;
    PORT
      LAYER M5 ;
        RECT  30.624 23.676 30.648 23.76 ;
    END
  END o[301]
  PIN o[302]
    DIRECTION OUTPUT ;
    USE SIGNAL ;
    PORT
      LAYER M3 ;
        RECT  30.744 23.722 30.762 23.76 ;
    END
  END o[302]
  PIN o[303]
    DIRECTION OUTPUT ;
    USE SIGNAL ;
    PORT
      LAYER M5 ;
        RECT  30.864 23.676 30.888 23.76 ;
    END
  END o[303]
  PIN o[304]
    DIRECTION OUTPUT ;
    USE SIGNAL ;
    PORT
      LAYER M3 ;
        RECT  30.96 23.722 30.978 23.76 ;
    END
  END o[304]
  PIN o[305]
    DIRECTION OUTPUT ;
    USE SIGNAL ;
    PORT
      LAYER M5 ;
        RECT  31.056 23.676 31.08 23.76 ;
    END
  END o[305]
  PIN o[306]
    DIRECTION OUTPUT ;
    USE SIGNAL ;
    PORT
      LAYER M3 ;
        RECT  31.14 23.722 31.158 23.76 ;
    END
  END o[306]
  PIN o[307]
    DIRECTION OUTPUT ;
    USE SIGNAL ;
    PORT
      LAYER M5 ;
        RECT  31.248 23.676 31.272 23.76 ;
    END
  END o[307]
  PIN o[308]
    DIRECTION OUTPUT ;
    USE SIGNAL ;
    PORT
      LAYER M3 ;
        RECT  31.356 23.722 31.374 23.76 ;
    END
  END o[308]
  PIN o[309]
    DIRECTION OUTPUT ;
    USE SIGNAL ;
    PORT
      LAYER M5 ;
        RECT  31.44 23.676 31.464 23.76 ;
    END
  END o[309]
  PIN o[30]
    DIRECTION OUTPUT ;
    USE SIGNAL ;
    PORT
      LAYER M3 ;
        RECT  3.636 23.722 3.654 23.76 ;
    END
  END o[30]
  PIN o[310]
    DIRECTION OUTPUT ;
    USE SIGNAL ;
    PORT
      LAYER M3 ;
        RECT  31.536 23.722 31.554 23.76 ;
    END
  END o[310]
  PIN o[311]
    DIRECTION OUTPUT ;
    USE SIGNAL ;
    PORT
      LAYER M5 ;
        RECT  31.632 23.676 31.656 23.76 ;
    END
  END o[311]
  PIN o[312]
    DIRECTION OUTPUT ;
    USE SIGNAL ;
    PORT
      LAYER M3 ;
        RECT  31.752 23.722 31.77 23.76 ;
    END
  END o[312]
  PIN o[313]
    DIRECTION OUTPUT ;
    USE SIGNAL ;
    PORT
      LAYER M5 ;
        RECT  31.824 23.676 31.848 23.76 ;
    END
  END o[313]
  PIN o[314]
    DIRECTION OUTPUT ;
    USE SIGNAL ;
    PORT
      LAYER M3 ;
        RECT  31.932 23.722 31.95 23.76 ;
    END
  END o[314]
  PIN o[315]
    DIRECTION OUTPUT ;
    USE SIGNAL ;
    PORT
      LAYER M5 ;
        RECT  32.016 23.676 32.04 23.76 ;
    END
  END o[315]
  PIN o[316]
    DIRECTION OUTPUT ;
    USE SIGNAL ;
    PORT
      LAYER M3 ;
        RECT  32.148 23.722 32.166 23.76 ;
    END
  END o[316]
  PIN o[317]
    DIRECTION OUTPUT ;
    USE SIGNAL ;
    PORT
      LAYER M5 ;
        RECT  32.256 23.676 32.28 23.76 ;
    END
  END o[317]
  PIN o[318]
    DIRECTION OUTPUT ;
    USE SIGNAL ;
    PORT
      LAYER M3 ;
        RECT  32.328 23.722 32.346 23.76 ;
    END
  END o[318]
  PIN o[319]
    DIRECTION OUTPUT ;
    USE SIGNAL ;
    PORT
      LAYER M5 ;
        RECT  32.448 23.676 32.472 23.76 ;
    END
  END o[319]
  PIN o[31]
    DIRECTION OUTPUT ;
    USE SIGNAL ;
    PORT
      LAYER M5 ;
        RECT  3.744 23.676 3.768 23.76 ;
    END
  END o[31]
  PIN o[320]
    DIRECTION OUTPUT ;
    USE SIGNAL ;
    PORT
      LAYER M3 ;
        RECT  32.544 23.722 32.562 23.76 ;
    END
  END o[320]
  PIN o[321]
    DIRECTION OUTPUT ;
    USE SIGNAL ;
    PORT
      LAYER M5 ;
        RECT  32.64 23.676 32.664 23.76 ;
    END
  END o[321]
  PIN o[322]
    DIRECTION OUTPUT ;
    USE SIGNAL ;
    PORT
      LAYER M3 ;
        RECT  32.724 23.722 32.742 23.76 ;
    END
  END o[322]
  PIN o[323]
    DIRECTION OUTPUT ;
    USE SIGNAL ;
    PORT
      LAYER M5 ;
        RECT  32.832 23.676 32.856 23.76 ;
    END
  END o[323]
  PIN o[324]
    DIRECTION OUTPUT ;
    USE SIGNAL ;
    PORT
      LAYER M3 ;
        RECT  32.94 23.722 32.958 23.76 ;
    END
  END o[324]
  PIN o[325]
    DIRECTION OUTPUT ;
    USE SIGNAL ;
    PORT
      LAYER M5 ;
        RECT  33.024 23.676 33.048 23.76 ;
    END
  END o[325]
  PIN o[326]
    DIRECTION OUTPUT ;
    USE SIGNAL ;
    PORT
      LAYER M3 ;
        RECT  33.12 23.722 33.138 23.76 ;
    END
  END o[326]
  PIN o[327]
    DIRECTION OUTPUT ;
    USE SIGNAL ;
    PORT
      LAYER M5 ;
        RECT  33.216 23.676 33.24 23.76 ;
    END
  END o[327]
  PIN o[328]
    DIRECTION OUTPUT ;
    USE SIGNAL ;
    PORT
      LAYER M3 ;
        RECT  33.336 23.722 33.354 23.76 ;
    END
  END o[328]
  PIN o[329]
    DIRECTION OUTPUT ;
    USE SIGNAL ;
    PORT
      LAYER M5 ;
        RECT  33.456 23.676 33.48 23.76 ;
    END
  END o[329]
  PIN o[32]
    DIRECTION OUTPUT ;
    USE SIGNAL ;
    PORT
      LAYER M3 ;
        RECT  3.816 23.722 3.834 23.76 ;
    END
  END o[32]
  PIN o[330]
    DIRECTION OUTPUT ;
    USE SIGNAL ;
    PORT
      LAYER M3 ;
        RECT  33.552 23.722 33.57 23.76 ;
    END
  END o[330]
  PIN o[331]
    DIRECTION OUTPUT ;
    USE SIGNAL ;
    PORT
      LAYER M5 ;
        RECT  33.648 23.676 33.672 23.76 ;
    END
  END o[331]
  PIN o[332]
    DIRECTION OUTPUT ;
    USE SIGNAL ;
    PORT
      LAYER M3 ;
        RECT  33.732 23.722 33.75 23.76 ;
    END
  END o[332]
  PIN o[333]
    DIRECTION OUTPUT ;
    USE SIGNAL ;
    PORT
      LAYER M5 ;
        RECT  33.84 23.676 33.864 23.76 ;
    END
  END o[333]
  PIN o[334]
    DIRECTION OUTPUT ;
    USE SIGNAL ;
    PORT
      LAYER M3 ;
        RECT  33.948 23.722 33.966 23.76 ;
    END
  END o[334]
  PIN o[335]
    DIRECTION OUTPUT ;
    USE SIGNAL ;
    PORT
      LAYER M5 ;
        RECT  34.032 23.676 34.056 23.76 ;
    END
  END o[335]
  PIN o[336]
    DIRECTION OUTPUT ;
    USE SIGNAL ;
    PORT
      LAYER M3 ;
        RECT  34.128 23.722 34.146 23.76 ;
    END
  END o[336]
  PIN o[337]
    DIRECTION OUTPUT ;
    USE SIGNAL ;
    PORT
      LAYER M5 ;
        RECT  34.224 23.676 34.248 23.76 ;
    END
  END o[337]
  PIN o[338]
    DIRECTION OUTPUT ;
    USE SIGNAL ;
    PORT
      LAYER M3 ;
        RECT  34.344 23.722 34.362 23.76 ;
    END
  END o[338]
  PIN o[339]
    DIRECTION OUTPUT ;
    USE SIGNAL ;
    PORT
      LAYER M5 ;
        RECT  34.416 23.676 34.44 23.76 ;
    END
  END o[339]
  PIN o[33]
    DIRECTION OUTPUT ;
    USE SIGNAL ;
    PORT
      LAYER M5 ;
        RECT  3.936 23.676 3.96 23.76 ;
    END
  END o[33]
  PIN o[340]
    DIRECTION OUTPUT ;
    USE SIGNAL ;
    PORT
      LAYER M3 ;
        RECT  34.524 23.722 34.542 23.76 ;
    END
  END o[340]
  PIN o[341]
    DIRECTION OUTPUT ;
    USE SIGNAL ;
    PORT
      LAYER M5 ;
        RECT  34.608 23.676 34.632 23.76 ;
    END
  END o[341]
  PIN o[342]
    DIRECTION OUTPUT ;
    USE SIGNAL ;
    PORT
      LAYER M3 ;
        RECT  34.74 23.722 34.758 23.76 ;
    END
  END o[342]
  PIN o[343]
    DIRECTION OUTPUT ;
    USE SIGNAL ;
    PORT
      LAYER M5 ;
        RECT  34.848 23.676 34.872 23.76 ;
    END
  END o[343]
  PIN o[344]
    DIRECTION OUTPUT ;
    USE SIGNAL ;
    PORT
      LAYER M3 ;
        RECT  34.92 23.722 34.938 23.76 ;
    END
  END o[344]
  PIN o[345]
    DIRECTION OUTPUT ;
    USE SIGNAL ;
    PORT
      LAYER M5 ;
        RECT  35.04 23.676 35.064 23.76 ;
    END
  END o[345]
  PIN o[346]
    DIRECTION OUTPUT ;
    USE SIGNAL ;
    PORT
      LAYER M3 ;
        RECT  35.136 23.722 35.154 23.76 ;
    END
  END o[346]
  PIN o[347]
    DIRECTION OUTPUT ;
    USE SIGNAL ;
    PORT
      LAYER M5 ;
        RECT  35.232 23.676 35.256 23.76 ;
    END
  END o[347]
  PIN o[348]
    DIRECTION OUTPUT ;
    USE SIGNAL ;
    PORT
      LAYER M3 ;
        RECT  35.316 23.722 35.334 23.76 ;
    END
  END o[348]
  PIN o[349]
    DIRECTION OUTPUT ;
    USE SIGNAL ;
    PORT
      LAYER M5 ;
        RECT  35.424 23.676 35.448 23.76 ;
    END
  END o[349]
  PIN o[34]
    DIRECTION OUTPUT ;
    USE SIGNAL ;
    PORT
      LAYER M3 ;
        RECT  4.032 23.722 4.05 23.76 ;
    END
  END o[34]
  PIN o[350]
    DIRECTION OUTPUT ;
    USE SIGNAL ;
    PORT
      LAYER M3 ;
        RECT  35.532 23.722 35.55 23.76 ;
    END
  END o[350]
  PIN o[351]
    DIRECTION OUTPUT ;
    USE SIGNAL ;
    PORT
      LAYER M5 ;
        RECT  35.616 23.676 35.64 23.76 ;
    END
  END o[351]
  PIN o[352]
    DIRECTION OUTPUT ;
    USE SIGNAL ;
    PORT
      LAYER M3 ;
        RECT  35.712 23.722 35.73 23.76 ;
    END
  END o[352]
  PIN o[353]
    DIRECTION OUTPUT ;
    USE SIGNAL ;
    PORT
      LAYER M5 ;
        RECT  35.808 23.676 35.832 23.76 ;
    END
  END o[353]
  PIN o[354]
    DIRECTION OUTPUT ;
    USE SIGNAL ;
    PORT
      LAYER M3 ;
        RECT  35.928 23.722 35.946 23.76 ;
    END
  END o[354]
  PIN o[355]
    DIRECTION OUTPUT ;
    USE SIGNAL ;
    PORT
      LAYER M5 ;
        RECT  36.048 23.676 36.072 23.76 ;
    END
  END o[355]
  PIN o[356]
    DIRECTION OUTPUT ;
    USE SIGNAL ;
    PORT
      LAYER M3 ;
        RECT  36.144 23.722 36.162 23.76 ;
    END
  END o[356]
  PIN o[357]
    DIRECTION OUTPUT ;
    USE SIGNAL ;
    PORT
      LAYER M5 ;
        RECT  36.24 23.676 36.264 23.76 ;
    END
  END o[357]
  PIN o[358]
    DIRECTION OUTPUT ;
    USE SIGNAL ;
    PORT
      LAYER M3 ;
        RECT  36.324 23.722 36.342 23.76 ;
    END
  END o[358]
  PIN o[359]
    DIRECTION OUTPUT ;
    USE SIGNAL ;
    PORT
      LAYER M5 ;
        RECT  36.432 23.676 36.456 23.76 ;
    END
  END o[359]
  PIN o[35]
    DIRECTION OUTPUT ;
    USE SIGNAL ;
    PORT
      LAYER M5 ;
        RECT  4.128 23.676 4.152 23.76 ;
    END
  END o[35]
  PIN o[360]
    DIRECTION OUTPUT ;
    USE SIGNAL ;
    PORT
      LAYER M3 ;
        RECT  36.54 23.722 36.558 23.76 ;
    END
  END o[360]
  PIN o[361]
    DIRECTION OUTPUT ;
    USE SIGNAL ;
    PORT
      LAYER M5 ;
        RECT  36.624 23.676 36.648 23.76 ;
    END
  END o[361]
  PIN o[362]
    DIRECTION OUTPUT ;
    USE SIGNAL ;
    PORT
      LAYER M3 ;
        RECT  36.72 23.722 36.738 23.76 ;
    END
  END o[362]
  PIN o[363]
    DIRECTION OUTPUT ;
    USE SIGNAL ;
    PORT
      LAYER M5 ;
        RECT  36.816 23.676 36.84 23.76 ;
    END
  END o[363]
  PIN o[364]
    DIRECTION OUTPUT ;
    USE SIGNAL ;
    PORT
      LAYER M3 ;
        RECT  36.936 23.722 36.954 23.76 ;
    END
  END o[364]
  PIN o[365]
    DIRECTION OUTPUT ;
    USE SIGNAL ;
    PORT
      LAYER M5 ;
        RECT  37.008 23.676 37.032 23.76 ;
    END
  END o[365]
  PIN o[366]
    DIRECTION OUTPUT ;
    USE SIGNAL ;
    PORT
      LAYER M3 ;
        RECT  37.116 23.722 37.134 23.76 ;
    END
  END o[366]
  PIN o[367]
    DIRECTION OUTPUT ;
    USE SIGNAL ;
    PORT
      LAYER M5 ;
        RECT  37.2 23.676 37.224 23.76 ;
    END
  END o[367]
  PIN o[368]
    DIRECTION OUTPUT ;
    USE SIGNAL ;
    PORT
      LAYER M3 ;
        RECT  37.332 23.722 37.35 23.76 ;
    END
  END o[368]
  PIN o[369]
    DIRECTION OUTPUT ;
    USE SIGNAL ;
    PORT
      LAYER M5 ;
        RECT  37.44 23.676 37.464 23.76 ;
    END
  END o[369]
  PIN o[36]
    DIRECTION OUTPUT ;
    USE SIGNAL ;
    PORT
      LAYER M3 ;
        RECT  4.212 23.722 4.23 23.76 ;
    END
  END o[36]
  PIN o[370]
    DIRECTION OUTPUT ;
    USE SIGNAL ;
    PORT
      LAYER M3 ;
        RECT  37.512 23.722 37.53 23.76 ;
    END
  END o[370]
  PIN o[371]
    DIRECTION OUTPUT ;
    USE SIGNAL ;
    PORT
      LAYER M5 ;
        RECT  37.632 23.676 37.656 23.76 ;
    END
  END o[371]
  PIN o[372]
    DIRECTION OUTPUT ;
    USE SIGNAL ;
    PORT
      LAYER M3 ;
        RECT  37.728 23.722 37.746 23.76 ;
    END
  END o[372]
  PIN o[373]
    DIRECTION OUTPUT ;
    USE SIGNAL ;
    PORT
      LAYER M5 ;
        RECT  37.824 23.676 37.848 23.76 ;
    END
  END o[373]
  PIN o[374]
    DIRECTION OUTPUT ;
    USE SIGNAL ;
    PORT
      LAYER M3 ;
        RECT  37.908 23.722 37.926 23.76 ;
    END
  END o[374]
  PIN o[375]
    DIRECTION OUTPUT ;
    USE SIGNAL ;
    PORT
      LAYER M5 ;
        RECT  38.016 23.676 38.04 23.76 ;
    END
  END o[375]
  PIN o[376]
    DIRECTION OUTPUT ;
    USE SIGNAL ;
    PORT
      LAYER M3 ;
        RECT  38.124 23.722 38.142 23.76 ;
    END
  END o[376]
  PIN o[377]
    DIRECTION OUTPUT ;
    USE SIGNAL ;
    PORT
      LAYER M5 ;
        RECT  38.208 23.676 38.232 23.76 ;
    END
  END o[377]
  PIN o[378]
    DIRECTION OUTPUT ;
    USE SIGNAL ;
    PORT
      LAYER M3 ;
        RECT  38.304 23.722 38.322 23.76 ;
    END
  END o[378]
  PIN o[379]
    DIRECTION OUTPUT ;
    USE SIGNAL ;
    PORT
      LAYER M5 ;
        RECT  38.4 23.676 38.424 23.76 ;
    END
  END o[379]
  PIN o[37]
    DIRECTION OUTPUT ;
    USE SIGNAL ;
    PORT
      LAYER M5 ;
        RECT  4.32 23.676 4.344 23.76 ;
    END
  END o[37]
  PIN o[380]
    DIRECTION OUTPUT ;
    USE SIGNAL ;
    PORT
      LAYER M3 ;
        RECT  38.52 23.722 38.538 23.76 ;
    END
  END o[380]
  PIN o[381]
    DIRECTION OUTPUT ;
    USE SIGNAL ;
    PORT
      LAYER M5 ;
        RECT  38.64 23.676 38.664 23.76 ;
    END
  END o[381]
  PIN o[382]
    DIRECTION OUTPUT ;
    USE SIGNAL ;
    PORT
      LAYER M3 ;
        RECT  38.736 23.722 38.754 23.76 ;
    END
  END o[382]
  PIN o[383]
    DIRECTION OUTPUT ;
    USE SIGNAL ;
    PORT
      LAYER M5 ;
        RECT  38.832 23.676 38.856 23.76 ;
    END
  END o[383]
  PIN o[384]
    DIRECTION OUTPUT ;
    USE SIGNAL ;
    PORT
      LAYER M3 ;
        RECT  38.916 23.722 38.934 23.76 ;
    END
  END o[384]
  PIN o[385]
    DIRECTION OUTPUT ;
    USE SIGNAL ;
    PORT
      LAYER M5 ;
        RECT  39.024 23.676 39.048 23.76 ;
    END
  END o[385]
  PIN o[386]
    DIRECTION OUTPUT ;
    USE SIGNAL ;
    PORT
      LAYER M3 ;
        RECT  39.132 23.722 39.15 23.76 ;
    END
  END o[386]
  PIN o[387]
    DIRECTION OUTPUT ;
    USE SIGNAL ;
    PORT
      LAYER M5 ;
        RECT  39.216 23.676 39.24 23.76 ;
    END
  END o[387]
  PIN o[388]
    DIRECTION OUTPUT ;
    USE SIGNAL ;
    PORT
      LAYER M3 ;
        RECT  39.312 23.722 39.33 23.76 ;
    END
  END o[388]
  PIN o[389]
    DIRECTION OUTPUT ;
    USE SIGNAL ;
    PORT
      LAYER M5 ;
        RECT  39.408 23.676 39.432 23.76 ;
    END
  END o[389]
  PIN o[38]
    DIRECTION OUTPUT ;
    USE SIGNAL ;
    PORT
      LAYER M3 ;
        RECT  4.428 23.722 4.446 23.76 ;
    END
  END o[38]
  PIN o[390]
    DIRECTION OUTPUT ;
    USE SIGNAL ;
    PORT
      LAYER M3 ;
        RECT  39.528 23.722 39.546 23.76 ;
    END
  END o[390]
  PIN o[391]
    DIRECTION OUTPUT ;
    USE SIGNAL ;
    PORT
      LAYER M5 ;
        RECT  39.6 23.676 39.624 23.76 ;
    END
  END o[391]
  PIN o[392]
    DIRECTION OUTPUT ;
    USE SIGNAL ;
    PORT
      LAYER M3 ;
        RECT  39.708 23.722 39.726 23.76 ;
    END
  END o[392]
  PIN o[393]
    DIRECTION OUTPUT ;
    USE SIGNAL ;
    PORT
      LAYER M5 ;
        RECT  39.792 23.676 39.816 23.76 ;
    END
  END o[393]
  PIN o[394]
    DIRECTION OUTPUT ;
    USE SIGNAL ;
    PORT
      LAYER M3 ;
        RECT  39.924 23.722 39.942 23.76 ;
    END
  END o[394]
  PIN o[395]
    DIRECTION OUTPUT ;
    USE SIGNAL ;
    PORT
      LAYER M5 ;
        RECT  40.032 23.676 40.056 23.76 ;
    END
  END o[395]
  PIN o[396]
    DIRECTION OUTPUT ;
    USE SIGNAL ;
    PORT
      LAYER M3 ;
        RECT  40.104 23.722 40.122 23.76 ;
    END
  END o[396]
  PIN o[397]
    DIRECTION OUTPUT ;
    USE SIGNAL ;
    PORT
      LAYER M5 ;
        RECT  40.224 23.676 40.248 23.76 ;
    END
  END o[397]
  PIN o[398]
    DIRECTION OUTPUT ;
    USE SIGNAL ;
    PORT
      LAYER M3 ;
        RECT  40.32 23.722 40.338 23.76 ;
    END
  END o[398]
  PIN o[399]
    DIRECTION OUTPUT ;
    USE SIGNAL ;
    PORT
      LAYER M5 ;
        RECT  40.416 23.676 40.44 23.76 ;
    END
  END o[399]
  PIN o[39]
    DIRECTION OUTPUT ;
    USE SIGNAL ;
    PORT
      LAYER M5 ;
        RECT  4.512 23.676 4.536 23.76 ;
    END
  END o[39]
  PIN o[3]
    DIRECTION OUTPUT ;
    USE SIGNAL ;
    PORT
      LAYER M5 ;
        RECT  0.96 23.676 0.984 23.76 ;
    END
  END o[3]
  PIN o[400]
    DIRECTION OUTPUT ;
    USE SIGNAL ;
    PORT
      LAYER M3 ;
        RECT  40.5 23.722 40.518 23.76 ;
    END
  END o[400]
  PIN o[401]
    DIRECTION OUTPUT ;
    USE SIGNAL ;
    PORT
      LAYER M5 ;
        RECT  40.608 23.676 40.632 23.76 ;
    END
  END o[401]
  PIN o[402]
    DIRECTION OUTPUT ;
    USE SIGNAL ;
    PORT
      LAYER M3 ;
        RECT  40.716 23.722 40.734 23.76 ;
    END
  END o[402]
  PIN o[403]
    DIRECTION OUTPUT ;
    USE SIGNAL ;
    PORT
      LAYER M5 ;
        RECT  40.8 23.676 40.824 23.76 ;
    END
  END o[403]
  PIN o[404]
    DIRECTION OUTPUT ;
    USE SIGNAL ;
    PORT
      LAYER M3 ;
        RECT  40.896 23.722 40.914 23.76 ;
    END
  END o[404]
  PIN o[405]
    DIRECTION OUTPUT ;
    USE SIGNAL ;
    PORT
      LAYER M5 ;
        RECT  40.992 23.676 41.016 23.76 ;
    END
  END o[405]
  PIN o[406]
    DIRECTION OUTPUT ;
    USE SIGNAL ;
    PORT
      LAYER M3 ;
        RECT  41.112 23.722 41.13 23.76 ;
    END
  END o[406]
  PIN o[407]
    DIRECTION OUTPUT ;
    USE SIGNAL ;
    PORT
      LAYER M5 ;
        RECT  41.184 23.676 41.208 23.76 ;
    END
  END o[407]
  PIN o[408]
    DIRECTION OUTPUT ;
    USE SIGNAL ;
    PORT
      LAYER M3 ;
        RECT  41.328 23.722 41.346 23.76 ;
    END
  END o[408]
  PIN o[409]
    DIRECTION OUTPUT ;
    USE SIGNAL ;
    PORT
      LAYER M5 ;
        RECT  41.424 23.676 41.448 23.76 ;
    END
  END o[409]
  PIN o[40]
    DIRECTION OUTPUT ;
    USE SIGNAL ;
    PORT
      LAYER M3 ;
        RECT  4.644 23.722 4.662 23.76 ;
    END
  END o[40]
  PIN o[410]
    DIRECTION OUTPUT ;
    USE SIGNAL ;
    PORT
      LAYER M3 ;
        RECT  41.508 23.722 41.526 23.76 ;
    END
  END o[410]
  PIN o[411]
    DIRECTION OUTPUT ;
    USE SIGNAL ;
    PORT
      LAYER M5 ;
        RECT  41.616 23.676 41.64 23.76 ;
    END
  END o[411]
  PIN o[412]
    DIRECTION OUTPUT ;
    USE SIGNAL ;
    PORT
      LAYER M3 ;
        RECT  41.724 23.722 41.742 23.76 ;
    END
  END o[412]
  PIN o[413]
    DIRECTION OUTPUT ;
    USE SIGNAL ;
    PORT
      LAYER M5 ;
        RECT  41.808 23.676 41.832 23.76 ;
    END
  END o[413]
  PIN o[414]
    DIRECTION OUTPUT ;
    USE SIGNAL ;
    PORT
      LAYER M3 ;
        RECT  41.904 23.722 41.922 23.76 ;
    END
  END o[414]
  PIN o[415]
    DIRECTION OUTPUT ;
    USE SIGNAL ;
    PORT
      LAYER M5 ;
        RECT  42 23.676 42.024 23.76 ;
    END
  END o[415]
  PIN o[416]
    DIRECTION OUTPUT ;
    USE SIGNAL ;
    PORT
      LAYER M3 ;
        RECT  42.12 23.722 42.138 23.76 ;
    END
  END o[416]
  PIN o[417]
    DIRECTION OUTPUT ;
    USE SIGNAL ;
    PORT
      LAYER M5 ;
        RECT  42.192 23.676 42.216 23.76 ;
    END
  END o[417]
  PIN o[418]
    DIRECTION OUTPUT ;
    USE SIGNAL ;
    PORT
      LAYER M3 ;
        RECT  42.3 23.722 42.318 23.76 ;
    END
  END o[418]
  PIN o[419]
    DIRECTION OUTPUT ;
    USE SIGNAL ;
    PORT
      LAYER M5 ;
        RECT  42.384 23.676 42.408 23.76 ;
    END
  END o[419]
  PIN o[41]
    DIRECTION OUTPUT ;
    USE SIGNAL ;
    PORT
      LAYER M5 ;
        RECT  4.704 23.676 4.728 23.76 ;
    END
  END o[41]
  PIN o[420]
    DIRECTION OUTPUT ;
    USE SIGNAL ;
    PORT
      LAYER M3 ;
        RECT  42.516 23.722 42.534 23.76 ;
    END
  END o[420]
  PIN o[421]
    DIRECTION OUTPUT ;
    USE SIGNAL ;
    PORT
      LAYER M5 ;
        RECT  42.624 23.676 42.648 23.76 ;
    END
  END o[421]
  PIN o[422]
    DIRECTION OUTPUT ;
    USE SIGNAL ;
    PORT
      LAYER M3 ;
        RECT  42.696 23.722 42.714 23.76 ;
    END
  END o[422]
  PIN o[423]
    DIRECTION OUTPUT ;
    USE SIGNAL ;
    PORT
      LAYER M5 ;
        RECT  42.816 23.676 42.84 23.76 ;
    END
  END o[423]
  PIN o[424]
    DIRECTION OUTPUT ;
    USE SIGNAL ;
    PORT
      LAYER M3 ;
        RECT  42.912 23.722 42.93 23.76 ;
    END
  END o[424]
  PIN o[425]
    DIRECTION OUTPUT ;
    USE SIGNAL ;
    PORT
      LAYER M5 ;
        RECT  43.008 23.676 43.032 23.76 ;
    END
  END o[425]
  PIN o[426]
    DIRECTION OUTPUT ;
    USE SIGNAL ;
    PORT
      LAYER M3 ;
        RECT  43.092 23.722 43.11 23.76 ;
    END
  END o[426]
  PIN o[427]
    DIRECTION OUTPUT ;
    USE SIGNAL ;
    PORT
      LAYER M5 ;
        RECT  43.2 23.676 43.224 23.76 ;
    END
  END o[427]
  PIN o[428]
    DIRECTION OUTPUT ;
    USE SIGNAL ;
    PORT
      LAYER M3 ;
        RECT  43.308 23.722 43.326 23.76 ;
    END
  END o[428]
  PIN o[429]
    DIRECTION OUTPUT ;
    USE SIGNAL ;
    PORT
      LAYER M5 ;
        RECT  43.392 23.676 43.416 23.76 ;
    END
  END o[429]
  PIN o[42]
    DIRECTION OUTPUT ;
    USE SIGNAL ;
    PORT
      LAYER M3 ;
        RECT  4.824 23.722 4.842 23.76 ;
    END
  END o[42]
  PIN o[430]
    DIRECTION OUTPUT ;
    USE SIGNAL ;
    PORT
      LAYER M3 ;
        RECT  43.488 23.722 43.506 23.76 ;
    END
  END o[430]
  PIN o[431]
    DIRECTION OUTPUT ;
    USE SIGNAL ;
    PORT
      LAYER M5 ;
        RECT  43.584 23.676 43.608 23.76 ;
    END
  END o[431]
  PIN o[432]
    DIRECTION OUTPUT ;
    USE SIGNAL ;
    PORT
      LAYER M3 ;
        RECT  43.704 23.722 43.722 23.76 ;
    END
  END o[432]
  PIN o[433]
    DIRECTION OUTPUT ;
    USE SIGNAL ;
    PORT
      LAYER M5 ;
        RECT  43.776 23.676 43.8 23.76 ;
    END
  END o[433]
  PIN o[434]
    DIRECTION OUTPUT ;
    USE SIGNAL ;
    PORT
      LAYER M3 ;
        RECT  43.92 23.722 43.938 23.76 ;
    END
  END o[434]
  PIN o[435]
    DIRECTION OUTPUT ;
    USE SIGNAL ;
    PORT
      LAYER M5 ;
        RECT  44.016 23.676 44.04 23.76 ;
    END
  END o[435]
  PIN o[436]
    DIRECTION OUTPUT ;
    USE SIGNAL ;
    PORT
      LAYER M3 ;
        RECT  44.1 23.722 44.118 23.76 ;
    END
  END o[436]
  PIN o[437]
    DIRECTION OUTPUT ;
    USE SIGNAL ;
    PORT
      LAYER M5 ;
        RECT  44.208 23.676 44.232 23.76 ;
    END
  END o[437]
  PIN o[438]
    DIRECTION OUTPUT ;
    USE SIGNAL ;
    PORT
      LAYER M3 ;
        RECT  44.316 23.722 44.334 23.76 ;
    END
  END o[438]
  PIN o[439]
    DIRECTION OUTPUT ;
    USE SIGNAL ;
    PORT
      LAYER M5 ;
        RECT  44.4 23.676 44.424 23.76 ;
    END
  END o[439]
  PIN o[43]
    DIRECTION OUTPUT ;
    USE SIGNAL ;
    PORT
      LAYER M5 ;
        RECT  4.944 23.676 4.968 23.76 ;
    END
  END o[43]
  PIN o[440]
    DIRECTION OUTPUT ;
    USE SIGNAL ;
    PORT
      LAYER M3 ;
        RECT  44.496 23.722 44.514 23.76 ;
    END
  END o[440]
  PIN o[441]
    DIRECTION OUTPUT ;
    USE SIGNAL ;
    PORT
      LAYER M5 ;
        RECT  44.592 23.676 44.616 23.76 ;
    END
  END o[441]
  PIN o[442]
    DIRECTION OUTPUT ;
    USE SIGNAL ;
    PORT
      LAYER M3 ;
        RECT  44.712 23.722 44.73 23.76 ;
    END
  END o[442]
  PIN o[443]
    DIRECTION OUTPUT ;
    USE SIGNAL ;
    PORT
      LAYER M5 ;
        RECT  44.784 23.676 44.808 23.76 ;
    END
  END o[443]
  PIN o[444]
    DIRECTION OUTPUT ;
    USE SIGNAL ;
    PORT
      LAYER M3 ;
        RECT  44.892 23.722 44.91 23.76 ;
    END
  END o[444]
  PIN o[445]
    DIRECTION OUTPUT ;
    USE SIGNAL ;
    PORT
      LAYER M5 ;
        RECT  44.976 23.676 45 23.76 ;
    END
  END o[445]
  PIN o[446]
    DIRECTION OUTPUT ;
    USE SIGNAL ;
    PORT
      LAYER M3 ;
        RECT  45.108 23.722 45.126 23.76 ;
    END
  END o[446]
  PIN o[447]
    DIRECTION OUTPUT ;
    USE SIGNAL ;
    PORT
      LAYER M5 ;
        RECT  45.216 23.676 45.24 23.76 ;
    END
  END o[447]
  PIN o[448]
    DIRECTION OUTPUT ;
    USE SIGNAL ;
    PORT
      LAYER M3 ;
        RECT  45.288 23.722 45.306 23.76 ;
    END
  END o[448]
  PIN o[449]
    DIRECTION OUTPUT ;
    USE SIGNAL ;
    PORT
      LAYER M5 ;
        RECT  45.408 23.676 45.432 23.76 ;
    END
  END o[449]
  PIN o[44]
    DIRECTION OUTPUT ;
    USE SIGNAL ;
    PORT
      LAYER M3 ;
        RECT  5.04 23.722 5.058 23.76 ;
    END
  END o[44]
  PIN o[450]
    DIRECTION OUTPUT ;
    USE SIGNAL ;
    PORT
      LAYER M3 ;
        RECT  45.504 23.722 45.522 23.76 ;
    END
  END o[450]
  PIN o[451]
    DIRECTION OUTPUT ;
    USE SIGNAL ;
    PORT
      LAYER M5 ;
        RECT  45.6 23.676 45.624 23.76 ;
    END
  END o[451]
  PIN o[452]
    DIRECTION OUTPUT ;
    USE SIGNAL ;
    PORT
      LAYER M3 ;
        RECT  45.684 23.722 45.702 23.76 ;
    END
  END o[452]
  PIN o[453]
    DIRECTION OUTPUT ;
    USE SIGNAL ;
    PORT
      LAYER M5 ;
        RECT  45.792 23.676 45.816 23.76 ;
    END
  END o[453]
  PIN o[454]
    DIRECTION OUTPUT ;
    USE SIGNAL ;
    PORT
      LAYER M3 ;
        RECT  45.9 23.722 45.918 23.76 ;
    END
  END o[454]
  PIN o[455]
    DIRECTION OUTPUT ;
    USE SIGNAL ;
    PORT
      LAYER M5 ;
        RECT  45.984 23.676 46.008 23.76 ;
    END
  END o[455]
  PIN o[456]
    DIRECTION OUTPUT ;
    USE SIGNAL ;
    PORT
      LAYER M3 ;
        RECT  46.08 23.722 46.098 23.76 ;
    END
  END o[456]
  PIN o[457]
    DIRECTION OUTPUT ;
    USE SIGNAL ;
    PORT
      LAYER M5 ;
        RECT  46.176 23.676 46.2 23.76 ;
    END
  END o[457]
  PIN o[458]
    DIRECTION OUTPUT ;
    USE SIGNAL ;
    PORT
      LAYER M3 ;
        RECT  46.296 23.722 46.314 23.76 ;
    END
  END o[458]
  PIN o[459]
    DIRECTION OUTPUT ;
    USE SIGNAL ;
    PORT
      LAYER M5 ;
        RECT  46.368 23.676 46.392 23.76 ;
    END
  END o[459]
  PIN o[45]
    DIRECTION OUTPUT ;
    USE SIGNAL ;
    PORT
      LAYER M5 ;
        RECT  5.136 23.676 5.16 23.76 ;
    END
  END o[45]
  PIN o[460]
    DIRECTION OUTPUT ;
    USE SIGNAL ;
    PORT
      LAYER M3 ;
        RECT  46.476 23.722 46.494 23.76 ;
    END
  END o[460]
  PIN o[461]
    DIRECTION OUTPUT ;
    USE SIGNAL ;
    PORT
      LAYER M5 ;
        RECT  46.608 23.676 46.632 23.76 ;
    END
  END o[461]
  PIN o[462]
    DIRECTION OUTPUT ;
    USE SIGNAL ;
    PORT
      LAYER M3 ;
        RECT  46.692 23.722 46.71 23.76 ;
    END
  END o[462]
  PIN o[463]
    DIRECTION OUTPUT ;
    USE SIGNAL ;
    PORT
      LAYER M5 ;
        RECT  46.8 23.676 46.824 23.76 ;
    END
  END o[463]
  PIN o[464]
    DIRECTION OUTPUT ;
    USE SIGNAL ;
    PORT
      LAYER M3 ;
        RECT  46.908 23.722 46.926 23.76 ;
    END
  END o[464]
  PIN o[465]
    DIRECTION OUTPUT ;
    USE SIGNAL ;
    PORT
      LAYER M5 ;
        RECT  46.992 23.676 47.016 23.76 ;
    END
  END o[465]
  PIN o[466]
    DIRECTION OUTPUT ;
    USE SIGNAL ;
    PORT
      LAYER M3 ;
        RECT  47.088 23.722 47.106 23.76 ;
    END
  END o[466]
  PIN o[467]
    DIRECTION OUTPUT ;
    USE SIGNAL ;
    PORT
      LAYER M5 ;
        RECT  47.184 23.676 47.208 23.76 ;
    END
  END o[467]
  PIN o[468]
    DIRECTION OUTPUT ;
    USE SIGNAL ;
    PORT
      LAYER M3 ;
        RECT  47.304 23.722 47.322 23.76 ;
    END
  END o[468]
  PIN o[469]
    DIRECTION OUTPUT ;
    USE SIGNAL ;
    PORT
      LAYER M5 ;
        RECT  47.376 23.676 47.4 23.76 ;
    END
  END o[469]
  PIN o[46]
    DIRECTION OUTPUT ;
    USE SIGNAL ;
    PORT
      LAYER M3 ;
        RECT  5.22 23.722 5.238 23.76 ;
    END
  END o[46]
  PIN o[470]
    DIRECTION OUTPUT ;
    USE SIGNAL ;
    PORT
      LAYER M3 ;
        RECT  47.484 23.722 47.502 23.76 ;
    END
  END o[470]
  PIN o[471]
    DIRECTION OUTPUT ;
    USE SIGNAL ;
    PORT
      LAYER M5 ;
        RECT  47.568 23.676 47.592 23.76 ;
    END
  END o[471]
  PIN o[472]
    DIRECTION OUTPUT ;
    USE SIGNAL ;
    PORT
      LAYER M3 ;
        RECT  47.7 23.722 47.718 23.76 ;
    END
  END o[472]
  PIN o[473]
    DIRECTION OUTPUT ;
    USE SIGNAL ;
    PORT
      LAYER M5 ;
        RECT  47.808 23.676 47.832 23.76 ;
    END
  END o[473]
  PIN o[474]
    DIRECTION OUTPUT ;
    USE SIGNAL ;
    PORT
      LAYER M3 ;
        RECT  47.88 23.722 47.898 23.76 ;
    END
  END o[474]
  PIN o[475]
    DIRECTION OUTPUT ;
    USE SIGNAL ;
    PORT
      LAYER M5 ;
        RECT  48 23.676 48.024 23.76 ;
    END
  END o[475]
  PIN o[476]
    DIRECTION OUTPUT ;
    USE SIGNAL ;
    PORT
      LAYER M3 ;
        RECT  48.096 23.722 48.114 23.76 ;
    END
  END o[476]
  PIN o[477]
    DIRECTION OUTPUT ;
    USE SIGNAL ;
    PORT
      LAYER M5 ;
        RECT  48.192 23.676 48.216 23.76 ;
    END
  END o[477]
  PIN o[478]
    DIRECTION OUTPUT ;
    USE SIGNAL ;
    PORT
      LAYER M3 ;
        RECT  48.276 23.722 48.294 23.76 ;
    END
  END o[478]
  PIN o[479]
    DIRECTION OUTPUT ;
    USE SIGNAL ;
    PORT
      LAYER M5 ;
        RECT  48.384 23.676 48.408 23.76 ;
    END
  END o[479]
  PIN o[47]
    DIRECTION OUTPUT ;
    USE SIGNAL ;
    PORT
      LAYER M5 ;
        RECT  5.328 23.676 5.352 23.76 ;
    END
  END o[47]
  PIN o[480]
    DIRECTION OUTPUT ;
    USE SIGNAL ;
    PORT
      LAYER M3 ;
        RECT  48.492 23.722 48.51 23.76 ;
    END
  END o[480]
  PIN o[481]
    DIRECTION OUTPUT ;
    USE SIGNAL ;
    PORT
      LAYER M5 ;
        RECT  48.576 23.676 48.6 23.76 ;
    END
  END o[481]
  PIN o[482]
    DIRECTION OUTPUT ;
    USE SIGNAL ;
    PORT
      LAYER M3 ;
        RECT  48.672 23.722 48.69 23.76 ;
    END
  END o[482]
  PIN o[483]
    DIRECTION OUTPUT ;
    USE SIGNAL ;
    PORT
      LAYER M5 ;
        RECT  48.768 23.676 48.792 23.76 ;
    END
  END o[483]
  PIN o[484]
    DIRECTION OUTPUT ;
    USE SIGNAL ;
    PORT
      LAYER M3 ;
        RECT  48.888 23.722 48.906 23.76 ;
    END
  END o[484]
  PIN o[485]
    DIRECTION OUTPUT ;
    USE SIGNAL ;
    PORT
      LAYER M5 ;
        RECT  48.96 23.676 48.984 23.76 ;
    END
  END o[485]
  PIN o[486]
    DIRECTION OUTPUT ;
    USE SIGNAL ;
    PORT
      LAYER M3 ;
        RECT  49.068 23.722 49.086 23.76 ;
    END
  END o[486]
  PIN o[487]
    DIRECTION OUTPUT ;
    USE SIGNAL ;
    PORT
      LAYER M5 ;
        RECT  49.2 23.676 49.224 23.76 ;
    END
  END o[487]
  PIN o[488]
    DIRECTION OUTPUT ;
    USE SIGNAL ;
    PORT
      LAYER M3 ;
        RECT  49.284 23.722 49.302 23.76 ;
    END
  END o[488]
  PIN o[489]
    DIRECTION OUTPUT ;
    USE SIGNAL ;
    PORT
      LAYER M5 ;
        RECT  49.392 23.676 49.416 23.76 ;
    END
  END o[489]
  PIN o[48]
    DIRECTION OUTPUT ;
    USE SIGNAL ;
    PORT
      LAYER M3 ;
        RECT  5.436 23.722 5.454 23.76 ;
    END
  END o[48]
  PIN o[490]
    DIRECTION OUTPUT ;
    USE SIGNAL ;
    PORT
      LAYER M3 ;
        RECT  49.5 23.722 49.518 23.76 ;
    END
  END o[490]
  PIN o[491]
    DIRECTION OUTPUT ;
    USE SIGNAL ;
    PORT
      LAYER M5 ;
        RECT  49.584 23.676 49.608 23.76 ;
    END
  END o[491]
  PIN o[492]
    DIRECTION OUTPUT ;
    USE SIGNAL ;
    PORT
      LAYER M3 ;
        RECT  49.68 23.722 49.698 23.76 ;
    END
  END o[492]
  PIN o[493]
    DIRECTION OUTPUT ;
    USE SIGNAL ;
    PORT
      LAYER M5 ;
        RECT  49.776 23.676 49.8 23.76 ;
    END
  END o[493]
  PIN o[494]
    DIRECTION OUTPUT ;
    USE SIGNAL ;
    PORT
      LAYER M3 ;
        RECT  49.896 23.722 49.914 23.76 ;
    END
  END o[494]
  PIN o[495]
    DIRECTION OUTPUT ;
    USE SIGNAL ;
    PORT
      LAYER M5 ;
        RECT  49.968 23.676 49.992 23.76 ;
    END
  END o[495]
  PIN o[496]
    DIRECTION OUTPUT ;
    USE SIGNAL ;
    PORT
      LAYER M3 ;
        RECT  50.076 23.722 50.094 23.76 ;
    END
  END o[496]
  PIN o[497]
    DIRECTION OUTPUT ;
    USE SIGNAL ;
    PORT
      LAYER M5 ;
        RECT  50.16 23.676 50.184 23.76 ;
    END
  END o[497]
  PIN o[498]
    DIRECTION OUTPUT ;
    USE SIGNAL ;
    PORT
      LAYER M3 ;
        RECT  50.292 23.722 50.31 23.76 ;
    END
  END o[498]
  PIN o[499]
    DIRECTION OUTPUT ;
    USE SIGNAL ;
    PORT
      LAYER M5 ;
        RECT  50.4 23.676 50.424 23.76 ;
    END
  END o[499]
  PIN o[49]
    DIRECTION OUTPUT ;
    USE SIGNAL ;
    PORT
      LAYER M5 ;
        RECT  5.52 23.676 5.544 23.76 ;
    END
  END o[49]
  PIN o[4]
    DIRECTION OUTPUT ;
    USE SIGNAL ;
    PORT
      LAYER M3 ;
        RECT  1.044 23.722 1.062 23.76 ;
    END
  END o[4]
  PIN o[500]
    DIRECTION OUTPUT ;
    USE SIGNAL ;
    PORT
      LAYER M3 ;
        RECT  50.472 23.722 50.49 23.76 ;
    END
  END o[500]
  PIN o[501]
    DIRECTION OUTPUT ;
    USE SIGNAL ;
    PORT
      LAYER M5 ;
        RECT  50.592 23.676 50.616 23.76 ;
    END
  END o[501]
  PIN o[502]
    DIRECTION OUTPUT ;
    USE SIGNAL ;
    PORT
      LAYER M3 ;
        RECT  50.688 23.722 50.706 23.76 ;
    END
  END o[502]
  PIN o[503]
    DIRECTION OUTPUT ;
    USE SIGNAL ;
    PORT
      LAYER M5 ;
        RECT  50.784 23.676 50.808 23.76 ;
    END
  END o[503]
  PIN o[504]
    DIRECTION OUTPUT ;
    USE SIGNAL ;
    PORT
      LAYER M3 ;
        RECT  50.868 23.722 50.886 23.76 ;
    END
  END o[504]
  PIN o[505]
    DIRECTION OUTPUT ;
    USE SIGNAL ;
    PORT
      LAYER M5 ;
        RECT  50.976 23.676 51 23.76 ;
    END
  END o[505]
  PIN o[506]
    DIRECTION OUTPUT ;
    USE SIGNAL ;
    PORT
      LAYER M3 ;
        RECT  51.084 23.722 51.102 23.76 ;
    END
  END o[506]
  PIN o[507]
    DIRECTION OUTPUT ;
    USE SIGNAL ;
    PORT
      LAYER M5 ;
        RECT  51.168 23.676 51.192 23.76 ;
    END
  END o[507]
  PIN o[508]
    DIRECTION OUTPUT ;
    USE SIGNAL ;
    PORT
      LAYER M3 ;
        RECT  51.264 23.722 51.282 23.76 ;
    END
  END o[508]
  PIN o[509]
    DIRECTION OUTPUT ;
    USE SIGNAL ;
    PORT
      LAYER M5 ;
        RECT  51.36 23.676 51.384 23.76 ;
    END
  END o[509]
  PIN o[50]
    DIRECTION OUTPUT ;
    USE SIGNAL ;
    PORT
      LAYER M3 ;
        RECT  5.616 23.722 5.634 23.76 ;
    END
  END o[50]
  PIN o[510]
    DIRECTION OUTPUT ;
    USE SIGNAL ;
    PORT
      LAYER M3 ;
        RECT  51.48 23.722 51.498 23.76 ;
    END
  END o[510]
  PIN o[511]
    DIRECTION OUTPUT ;
    USE SIGNAL ;
    PORT
      LAYER M5 ;
        RECT  51.552 23.676 51.576 23.76 ;
    END
  END o[511]
  PIN o[512]
    DIRECTION OUTPUT ;
    USE SIGNAL ;
    PORT
      LAYER M3 ;
        RECT  51.66 23.722 51.678 23.76 ;
    END
  END o[512]
  PIN o[513]
    DIRECTION OUTPUT ;
    USE SIGNAL ;
    PORT
      LAYER M5 ;
        RECT  51.792 23.676 51.816 23.76 ;
    END
  END o[513]
  PIN o[514]
    DIRECTION OUTPUT ;
    USE SIGNAL ;
    PORT
      LAYER M3 ;
        RECT  51.876 23.722 51.894 23.76 ;
    END
  END o[514]
  PIN o[515]
    DIRECTION OUTPUT ;
    USE SIGNAL ;
    PORT
      LAYER M5 ;
        RECT  51.984 23.676 52.008 23.76 ;
    END
  END o[515]
  PIN o[516]
    DIRECTION OUTPUT ;
    USE SIGNAL ;
    PORT
      LAYER M3 ;
        RECT  52.092 23.722 52.11 23.76 ;
    END
  END o[516]
  PIN o[517]
    DIRECTION OUTPUT ;
    USE SIGNAL ;
    PORT
      LAYER M5 ;
        RECT  52.176 23.676 52.2 23.76 ;
    END
  END o[517]
  PIN o[518]
    DIRECTION OUTPUT ;
    USE SIGNAL ;
    PORT
      LAYER M3 ;
        RECT  52.272 23.722 52.29 23.76 ;
    END
  END o[518]
  PIN o[519]
    DIRECTION OUTPUT ;
    USE SIGNAL ;
    PORT
      LAYER M5 ;
        RECT  52.368 23.676 52.392 23.76 ;
    END
  END o[519]
  PIN o[51]
    DIRECTION OUTPUT ;
    USE SIGNAL ;
    PORT
      LAYER M5 ;
        RECT  5.712 23.676 5.736 23.76 ;
    END
  END o[51]
  PIN o[520]
    DIRECTION OUTPUT ;
    USE SIGNAL ;
    PORT
      LAYER M3 ;
        RECT  52.488 23.722 52.506 23.76 ;
    END
  END o[520]
  PIN o[521]
    DIRECTION OUTPUT ;
    USE SIGNAL ;
    PORT
      LAYER M5 ;
        RECT  52.56 23.676 52.584 23.76 ;
    END
  END o[521]
  PIN o[522]
    DIRECTION OUTPUT ;
    USE SIGNAL ;
    PORT
      LAYER M3 ;
        RECT  52.668 23.722 52.686 23.76 ;
    END
  END o[522]
  PIN o[523]
    DIRECTION OUTPUT ;
    USE SIGNAL ;
    PORT
      LAYER M5 ;
        RECT  52.752 23.676 52.776 23.76 ;
    END
  END o[523]
  PIN o[524]
    DIRECTION OUTPUT ;
    USE SIGNAL ;
    PORT
      LAYER M3 ;
        RECT  52.884 23.722 52.902 23.76 ;
    END
  END o[524]
  PIN o[525]
    DIRECTION OUTPUT ;
    USE SIGNAL ;
    PORT
      LAYER M5 ;
        RECT  52.992 23.676 53.016 23.76 ;
    END
  END o[525]
  PIN o[526]
    DIRECTION OUTPUT ;
    USE SIGNAL ;
    PORT
      LAYER M3 ;
        RECT  53.064 23.722 53.082 23.76 ;
    END
  END o[526]
  PIN o[527]
    DIRECTION OUTPUT ;
    USE SIGNAL ;
    PORT
      LAYER M5 ;
        RECT  53.184 23.676 53.208 23.76 ;
    END
  END o[527]
  PIN o[528]
    DIRECTION OUTPUT ;
    USE SIGNAL ;
    PORT
      LAYER M3 ;
        RECT  53.28 23.722 53.298 23.76 ;
    END
  END o[528]
  PIN o[529]
    DIRECTION OUTPUT ;
    USE SIGNAL ;
    PORT
      LAYER M5 ;
        RECT  53.376 23.676 53.4 23.76 ;
    END
  END o[529]
  PIN o[52]
    DIRECTION OUTPUT ;
    USE SIGNAL ;
    PORT
      LAYER M3 ;
        RECT  5.832 23.722 5.85 23.76 ;
    END
  END o[52]
  PIN o[530]
    DIRECTION OUTPUT ;
    USE SIGNAL ;
    PORT
      LAYER M3 ;
        RECT  53.46 23.722 53.478 23.76 ;
    END
  END o[530]
  PIN o[531]
    DIRECTION OUTPUT ;
    USE SIGNAL ;
    PORT
      LAYER M5 ;
        RECT  53.568 23.676 53.592 23.76 ;
    END
  END o[531]
  PIN o[532]
    DIRECTION OUTPUT ;
    USE SIGNAL ;
    PORT
      LAYER M3 ;
        RECT  53.676 23.722 53.694 23.76 ;
    END
  END o[532]
  PIN o[533]
    DIRECTION OUTPUT ;
    USE SIGNAL ;
    PORT
      LAYER M5 ;
        RECT  53.76 23.676 53.784 23.76 ;
    END
  END o[533]
  PIN o[534]
    DIRECTION OUTPUT ;
    USE SIGNAL ;
    PORT
      LAYER M3 ;
        RECT  53.856 23.722 53.874 23.76 ;
    END
  END o[534]
  PIN o[535]
    DIRECTION OUTPUT ;
    USE SIGNAL ;
    PORT
      LAYER M5 ;
        RECT  53.952 23.676 53.976 23.76 ;
    END
  END o[535]
  PIN o[536]
    DIRECTION OUTPUT ;
    USE SIGNAL ;
    PORT
      LAYER M3 ;
        RECT  54.072 23.722 54.09 23.76 ;
    END
  END o[536]
  PIN o[537]
    DIRECTION OUTPUT ;
    USE SIGNAL ;
    PORT
      LAYER M5 ;
        RECT  54.144 23.676 54.168 23.76 ;
    END
  END o[537]
  PIN o[538]
    DIRECTION OUTPUT ;
    USE SIGNAL ;
    PORT
      LAYER M3 ;
        RECT  54.252 23.722 54.27 23.76 ;
    END
  END o[538]
  PIN o[539]
    DIRECTION OUTPUT ;
    USE SIGNAL ;
    PORT
      LAYER M5 ;
        RECT  54.384 23.676 54.408 23.76 ;
    END
  END o[539]
  PIN o[53]
    DIRECTION OUTPUT ;
    USE SIGNAL ;
    PORT
      LAYER M5 ;
        RECT  5.904 23.676 5.928 23.76 ;
    END
  END o[53]
  PIN o[540]
    DIRECTION OUTPUT ;
    USE SIGNAL ;
    PORT
      LAYER M3 ;
        RECT  54.468 23.722 54.486 23.76 ;
    END
  END o[540]
  PIN o[541]
    DIRECTION OUTPUT ;
    USE SIGNAL ;
    PORT
      LAYER M5 ;
        RECT  54.576 23.676 54.6 23.76 ;
    END
  END o[541]
  PIN o[542]
    DIRECTION OUTPUT ;
    USE SIGNAL ;
    PORT
      LAYER M3 ;
        RECT  54.684 23.722 54.702 23.76 ;
    END
  END o[542]
  PIN o[543]
    DIRECTION OUTPUT ;
    USE SIGNAL ;
    PORT
      LAYER M5 ;
        RECT  54.768 23.676 54.792 23.76 ;
    END
  END o[543]
  PIN o[544]
    DIRECTION OUTPUT ;
    USE SIGNAL ;
    PORT
      LAYER M3 ;
        RECT  54.864 23.722 54.882 23.76 ;
    END
  END o[544]
  PIN o[545]
    DIRECTION OUTPUT ;
    USE SIGNAL ;
    PORT
      LAYER M5 ;
        RECT  54.96 23.676 54.984 23.76 ;
    END
  END o[545]
  PIN o[546]
    DIRECTION OUTPUT ;
    USE SIGNAL ;
    PORT
      LAYER M3 ;
        RECT  55.08 23.722 55.098 23.76 ;
    END
  END o[546]
  PIN o[547]
    DIRECTION OUTPUT ;
    USE SIGNAL ;
    PORT
      LAYER M5 ;
        RECT  55.152 23.676 55.176 23.76 ;
    END
  END o[547]
  PIN o[548]
    DIRECTION OUTPUT ;
    USE SIGNAL ;
    PORT
      LAYER M3 ;
        RECT  55.26 23.722 55.278 23.76 ;
    END
  END o[548]
  PIN o[549]
    DIRECTION OUTPUT ;
    USE SIGNAL ;
    PORT
      LAYER M5 ;
        RECT  55.344 23.676 55.368 23.76 ;
    END
  END o[549]
  PIN o[54]
    DIRECTION OUTPUT ;
    USE SIGNAL ;
    PORT
      LAYER M3 ;
        RECT  6.012 23.722 6.03 23.76 ;
    END
  END o[54]
  PIN o[550]
    DIRECTION OUTPUT ;
    USE SIGNAL ;
    PORT
      LAYER M3 ;
        RECT  55.476 23.722 55.494 23.76 ;
    END
  END o[550]
  PIN o[551]
    DIRECTION OUTPUT ;
    USE SIGNAL ;
    PORT
      LAYER M5 ;
        RECT  55.584 23.676 55.608 23.76 ;
    END
  END o[551]
  PIN o[552]
    DIRECTION OUTPUT ;
    USE SIGNAL ;
    PORT
      LAYER M3 ;
        RECT  55.656 23.722 55.674 23.76 ;
    END
  END o[552]
  PIN o[553]
    DIRECTION OUTPUT ;
    USE SIGNAL ;
    PORT
      LAYER M5 ;
        RECT  55.776 23.676 55.8 23.76 ;
    END
  END o[553]
  PIN o[554]
    DIRECTION OUTPUT ;
    USE SIGNAL ;
    PORT
      LAYER M3 ;
        RECT  55.872 23.722 55.89 23.76 ;
    END
  END o[554]
  PIN o[555]
    DIRECTION OUTPUT ;
    USE SIGNAL ;
    PORT
      LAYER M5 ;
        RECT  55.968 23.676 55.992 23.76 ;
    END
  END o[555]
  PIN o[556]
    DIRECTION OUTPUT ;
    USE SIGNAL ;
    PORT
      LAYER M3 ;
        RECT  56.052 23.722 56.07 23.76 ;
    END
  END o[556]
  PIN o[557]
    DIRECTION OUTPUT ;
    USE SIGNAL ;
    PORT
      LAYER M5 ;
        RECT  56.16 23.676 56.184 23.76 ;
    END
  END o[557]
  PIN o[558]
    DIRECTION OUTPUT ;
    USE SIGNAL ;
    PORT
      LAYER M3 ;
        RECT  56.268 23.722 56.286 23.76 ;
    END
  END o[558]
  PIN o[559]
    DIRECTION OUTPUT ;
    USE SIGNAL ;
    PORT
      LAYER M5 ;
        RECT  56.352 23.676 56.376 23.76 ;
    END
  END o[559]
  PIN o[55]
    DIRECTION OUTPUT ;
    USE SIGNAL ;
    PORT
      LAYER M5 ;
        RECT  6.144 23.676 6.168 23.76 ;
    END
  END o[55]
  PIN o[560]
    DIRECTION OUTPUT ;
    USE SIGNAL ;
    PORT
      LAYER M3 ;
        RECT  56.448 23.722 56.466 23.76 ;
    END
  END o[560]
  PIN o[561]
    DIRECTION OUTPUT ;
    USE SIGNAL ;
    PORT
      LAYER M5 ;
        RECT  56.544 23.676 56.568 23.76 ;
    END
  END o[561]
  PIN o[562]
    DIRECTION OUTPUT ;
    USE SIGNAL ;
    PORT
      LAYER M3 ;
        RECT  56.664 23.722 56.682 23.76 ;
    END
  END o[562]
  PIN o[563]
    DIRECTION OUTPUT ;
    USE SIGNAL ;
    PORT
      LAYER M5 ;
        RECT  56.736 23.676 56.76 23.76 ;
    END
  END o[563]
  PIN o[564]
    DIRECTION OUTPUT ;
    USE SIGNAL ;
    PORT
      LAYER M3 ;
        RECT  56.844 23.722 56.862 23.76 ;
    END
  END o[564]
  PIN o[565]
    DIRECTION OUTPUT ;
    USE SIGNAL ;
    PORT
      LAYER M5 ;
        RECT  56.976 23.676 57 23.76 ;
    END
  END o[565]
  PIN o[566]
    DIRECTION OUTPUT ;
    USE SIGNAL ;
    PORT
      LAYER M3 ;
        RECT  57.06 23.722 57.078 23.76 ;
    END
  END o[566]
  PIN o[567]
    DIRECTION OUTPUT ;
    USE SIGNAL ;
    PORT
      LAYER M5 ;
        RECT  57.168 23.676 57.192 23.76 ;
    END
  END o[567]
  PIN o[568]
    DIRECTION OUTPUT ;
    USE SIGNAL ;
    PORT
      LAYER M3 ;
        RECT  57.276 23.722 57.294 23.76 ;
    END
  END o[568]
  PIN o[569]
    DIRECTION OUTPUT ;
    USE SIGNAL ;
    PORT
      LAYER M5 ;
        RECT  57.36 23.676 57.384 23.76 ;
    END
  END o[569]
  PIN o[56]
    DIRECTION OUTPUT ;
    USE SIGNAL ;
    PORT
      LAYER M3 ;
        RECT  6.228 23.722 6.246 23.76 ;
    END
  END o[56]
  PIN o[570]
    DIRECTION OUTPUT ;
    USE SIGNAL ;
    PORT
      LAYER M3 ;
        RECT  57.456 23.722 57.474 23.76 ;
    END
  END o[570]
  PIN o[571]
    DIRECTION OUTPUT ;
    USE SIGNAL ;
    PORT
      LAYER M5 ;
        RECT  57.552 23.676 57.576 23.76 ;
    END
  END o[571]
  PIN o[572]
    DIRECTION OUTPUT ;
    USE SIGNAL ;
    PORT
      LAYER M3 ;
        RECT  57.672 23.722 57.69 23.76 ;
    END
  END o[572]
  PIN o[573]
    DIRECTION OUTPUT ;
    USE SIGNAL ;
    PORT
      LAYER M5 ;
        RECT  57.744 23.676 57.768 23.76 ;
    END
  END o[573]
  PIN o[574]
    DIRECTION OUTPUT ;
    USE SIGNAL ;
    PORT
      LAYER M3 ;
        RECT  57.852 23.722 57.87 23.76 ;
    END
  END o[574]
  PIN o[575]
    DIRECTION OUTPUT ;
    USE SIGNAL ;
    PORT
      LAYER M5 ;
        RECT  57.936 23.676 57.96 23.76 ;
    END
  END o[575]
  PIN o[576]
    DIRECTION OUTPUT ;
    USE SIGNAL ;
    PORT
      LAYER M3 ;
        RECT  58.068 23.722 58.086 23.76 ;
    END
  END o[576]
  PIN o[577]
    DIRECTION OUTPUT ;
    USE SIGNAL ;
    PORT
      LAYER M5 ;
        RECT  58.176 23.676 58.2 23.76 ;
    END
  END o[577]
  PIN o[578]
    DIRECTION OUTPUT ;
    USE SIGNAL ;
    PORT
      LAYER M3 ;
        RECT  58.248 23.722 58.266 23.76 ;
    END
  END o[578]
  PIN o[579]
    DIRECTION OUTPUT ;
    USE SIGNAL ;
    PORT
      LAYER M5 ;
        RECT  58.368 23.676 58.392 23.76 ;
    END
  END o[579]
  PIN o[57]
    DIRECTION OUTPUT ;
    USE SIGNAL ;
    PORT
      LAYER M5 ;
        RECT  6.336 23.676 6.36 23.76 ;
    END
  END o[57]
  PIN o[580]
    DIRECTION OUTPUT ;
    USE SIGNAL ;
    PORT
      LAYER M3 ;
        RECT  58.464 23.722 58.482 23.76 ;
    END
  END o[580]
  PIN o[581]
    DIRECTION OUTPUT ;
    USE SIGNAL ;
    PORT
      LAYER M5 ;
        RECT  58.56 23.676 58.584 23.76 ;
    END
  END o[581]
  PIN o[582]
    DIRECTION OUTPUT ;
    USE SIGNAL ;
    PORT
      LAYER M3 ;
        RECT  58.644 23.722 58.662 23.76 ;
    END
  END o[582]
  PIN o[583]
    DIRECTION OUTPUT ;
    USE SIGNAL ;
    PORT
      LAYER M5 ;
        RECT  58.752 23.676 58.776 23.76 ;
    END
  END o[583]
  PIN o[584]
    DIRECTION OUTPUT ;
    USE SIGNAL ;
    PORT
      LAYER M3 ;
        RECT  58.86 23.722 58.878 23.76 ;
    END
  END o[584]
  PIN o[585]
    DIRECTION OUTPUT ;
    USE SIGNAL ;
    PORT
      LAYER M5 ;
        RECT  58.944 23.676 58.968 23.76 ;
    END
  END o[585]
  PIN o[586]
    DIRECTION OUTPUT ;
    USE SIGNAL ;
    PORT
      LAYER M3 ;
        RECT  59.04 23.722 59.058 23.76 ;
    END
  END o[586]
  PIN o[587]
    DIRECTION OUTPUT ;
    USE SIGNAL ;
    PORT
      LAYER M5 ;
        RECT  59.136 23.676 59.16 23.76 ;
    END
  END o[587]
  PIN o[588]
    DIRECTION OUTPUT ;
    USE SIGNAL ;
    PORT
      LAYER M3 ;
        RECT  59.256 23.722 59.274 23.76 ;
    END
  END o[588]
  PIN o[589]
    DIRECTION OUTPUT ;
    USE SIGNAL ;
    PORT
      LAYER M5 ;
        RECT  59.328 23.676 59.352 23.76 ;
    END
  END o[589]
  PIN o[58]
    DIRECTION OUTPUT ;
    USE SIGNAL ;
    PORT
      LAYER M3 ;
        RECT  6.408 23.722 6.426 23.76 ;
    END
  END o[58]
  PIN o[590]
    DIRECTION OUTPUT ;
    USE SIGNAL ;
    PORT
      LAYER M3 ;
        RECT  59.436 23.722 59.454 23.76 ;
    END
  END o[590]
  PIN o[591]
    DIRECTION OUTPUT ;
    USE SIGNAL ;
    PORT
      LAYER M5 ;
        RECT  59.568 23.676 59.592 23.76 ;
    END
  END o[591]
  PIN o[592]
    DIRECTION OUTPUT ;
    USE SIGNAL ;
    PORT
      LAYER M3 ;
        RECT  59.652 23.722 59.67 23.76 ;
    END
  END o[592]
  PIN o[593]
    DIRECTION OUTPUT ;
    USE SIGNAL ;
    PORT
      LAYER M5 ;
        RECT  59.76 23.676 59.784 23.76 ;
    END
  END o[593]
  PIN o[594]
    DIRECTION OUTPUT ;
    USE SIGNAL ;
    PORT
      LAYER M3 ;
        RECT  59.868 23.722 59.886 23.76 ;
    END
  END o[594]
  PIN o[595]
    DIRECTION OUTPUT ;
    USE SIGNAL ;
    PORT
      LAYER M5 ;
        RECT  59.952 23.676 59.976 23.76 ;
    END
  END o[595]
  PIN o[596]
    DIRECTION OUTPUT ;
    USE SIGNAL ;
    PORT
      LAYER M3 ;
        RECT  60.048 23.722 60.066 23.76 ;
    END
  END o[596]
  PIN o[597]
    DIRECTION OUTPUT ;
    USE SIGNAL ;
    PORT
      LAYER M5 ;
        RECT  60.144 23.676 60.168 23.76 ;
    END
  END o[597]
  PIN o[598]
    DIRECTION OUTPUT ;
    USE SIGNAL ;
    PORT
      LAYER M3 ;
        RECT  60.264 23.722 60.282 23.76 ;
    END
  END o[598]
  PIN o[599]
    DIRECTION OUTPUT ;
    USE SIGNAL ;
    PORT
      LAYER M5 ;
        RECT  60.336 23.676 60.36 23.76 ;
    END
  END o[599]
  PIN o[59]
    DIRECTION OUTPUT ;
    USE SIGNAL ;
    PORT
      LAYER M5 ;
        RECT  6.528 23.676 6.552 23.76 ;
    END
  END o[59]
  PIN o[5]
    DIRECTION OUTPUT ;
    USE SIGNAL ;
    PORT
      LAYER M5 ;
        RECT  1.152 23.676 1.176 23.76 ;
    END
  END o[5]
  PIN o[600]
    DIRECTION OUTPUT ;
    USE SIGNAL ;
    PORT
      LAYER M3 ;
        RECT  60.444 23.722 60.462 23.76 ;
    END
  END o[600]
  PIN o[601]
    DIRECTION OUTPUT ;
    USE SIGNAL ;
    PORT
      LAYER M5 ;
        RECT  60.528 23.676 60.552 23.76 ;
    END
  END o[601]
  PIN o[602]
    DIRECTION OUTPUT ;
    USE SIGNAL ;
    PORT
      LAYER M3 ;
        RECT  60.66 23.722 60.678 23.76 ;
    END
  END o[602]
  PIN o[603]
    DIRECTION OUTPUT ;
    USE SIGNAL ;
    PORT
      LAYER M5 ;
        RECT  60.768 23.676 60.792 23.76 ;
    END
  END o[603]
  PIN o[604]
    DIRECTION OUTPUT ;
    USE SIGNAL ;
    PORT
      LAYER M3 ;
        RECT  60.84 23.722 60.858 23.76 ;
    END
  END o[604]
  PIN o[605]
    DIRECTION OUTPUT ;
    USE SIGNAL ;
    PORT
      LAYER M5 ;
        RECT  60.96 23.676 60.984 23.76 ;
    END
  END o[605]
  PIN o[606]
    DIRECTION OUTPUT ;
    USE SIGNAL ;
    PORT
      LAYER M3 ;
        RECT  61.056 23.722 61.074 23.76 ;
    END
  END o[606]
  PIN o[607]
    DIRECTION OUTPUT ;
    USE SIGNAL ;
    PORT
      LAYER M5 ;
        RECT  61.152 23.676 61.176 23.76 ;
    END
  END o[607]
  PIN o[608]
    DIRECTION OUTPUT ;
    USE SIGNAL ;
    PORT
      LAYER M3 ;
        RECT  61.236 23.722 61.254 23.76 ;
    END
  END o[608]
  PIN o[609]
    DIRECTION OUTPUT ;
    USE SIGNAL ;
    PORT
      LAYER M5 ;
        RECT  61.344 23.676 61.368 23.76 ;
    END
  END o[609]
  PIN o[60]
    DIRECTION OUTPUT ;
    USE SIGNAL ;
    PORT
      LAYER M3 ;
        RECT  6.624 23.722 6.642 23.76 ;
    END
  END o[60]
  PIN o[610]
    DIRECTION OUTPUT ;
    USE SIGNAL ;
    PORT
      LAYER M3 ;
        RECT  61.452 23.722 61.47 23.76 ;
    END
  END o[610]
  PIN o[611]
    DIRECTION OUTPUT ;
    USE SIGNAL ;
    PORT
      LAYER M5 ;
        RECT  61.536 23.676 61.56 23.76 ;
    END
  END o[611]
  PIN o[612]
    DIRECTION OUTPUT ;
    USE SIGNAL ;
    PORT
      LAYER M3 ;
        RECT  61.632 23.722 61.65 23.76 ;
    END
  END o[612]
  PIN o[613]
    DIRECTION OUTPUT ;
    USE SIGNAL ;
    PORT
      LAYER M5 ;
        RECT  61.728 23.676 61.752 23.76 ;
    END
  END o[613]
  PIN o[614]
    DIRECTION OUTPUT ;
    USE SIGNAL ;
    PORT
      LAYER M3 ;
        RECT  61.848 23.722 61.866 23.76 ;
    END
  END o[614]
  PIN o[615]
    DIRECTION OUTPUT ;
    USE SIGNAL ;
    PORT
      LAYER M5 ;
        RECT  61.92 23.676 61.944 23.76 ;
    END
  END o[615]
  PIN o[616]
    DIRECTION OUTPUT ;
    USE SIGNAL ;
    PORT
      LAYER M3 ;
        RECT  62.028 23.722 62.046 23.76 ;
    END
  END o[616]
  PIN o[617]
    DIRECTION OUTPUT ;
    USE SIGNAL ;
    PORT
      LAYER M5 ;
        RECT  62.16 23.676 62.184 23.76 ;
    END
  END o[617]
  PIN o[618]
    DIRECTION OUTPUT ;
    USE SIGNAL ;
    PORT
      LAYER M3 ;
        RECT  62.244 23.722 62.262 23.76 ;
    END
  END o[618]
  PIN o[619]
    DIRECTION OUTPUT ;
    USE SIGNAL ;
    PORT
      LAYER M5 ;
        RECT  62.352 23.676 62.376 23.76 ;
    END
  END o[619]
  PIN o[61]
    DIRECTION OUTPUT ;
    USE SIGNAL ;
    PORT
      LAYER M5 ;
        RECT  6.72 23.676 6.744 23.76 ;
    END
  END o[61]
  PIN o[620]
    DIRECTION OUTPUT ;
    USE SIGNAL ;
    PORT
      LAYER M3 ;
        RECT  62.46 23.722 62.478 23.76 ;
    END
  END o[620]
  PIN o[621]
    DIRECTION OUTPUT ;
    USE SIGNAL ;
    PORT
      LAYER M5 ;
        RECT  62.544 23.676 62.568 23.76 ;
    END
  END o[621]
  PIN o[622]
    DIRECTION OUTPUT ;
    USE SIGNAL ;
    PORT
      LAYER M3 ;
        RECT  62.64 23.722 62.658 23.76 ;
    END
  END o[622]
  PIN o[623]
    DIRECTION OUTPUT ;
    USE SIGNAL ;
    PORT
      LAYER M5 ;
        RECT  62.736 23.676 62.76 23.76 ;
    END
  END o[623]
  PIN o[62]
    DIRECTION OUTPUT ;
    USE SIGNAL ;
    PORT
      LAYER M3 ;
        RECT  6.804 23.722 6.822 23.76 ;
    END
  END o[62]
  PIN o[63]
    DIRECTION OUTPUT ;
    USE SIGNAL ;
    PORT
      LAYER M5 ;
        RECT  6.912 23.676 6.936 23.76 ;
    END
  END o[63]
  PIN o[64]
    DIRECTION OUTPUT ;
    USE SIGNAL ;
    PORT
      LAYER M3 ;
        RECT  7.02 23.722 7.038 23.76 ;
    END
  END o[64]
  PIN o[65]
    DIRECTION OUTPUT ;
    USE SIGNAL ;
    PORT
      LAYER M5 ;
        RECT  7.104 23.676 7.128 23.76 ;
    END
  END o[65]
  PIN o[66]
    DIRECTION OUTPUT ;
    USE SIGNAL ;
    PORT
      LAYER M3 ;
        RECT  7.236 23.722 7.254 23.76 ;
    END
  END o[66]
  PIN o[67]
    DIRECTION OUTPUT ;
    USE SIGNAL ;
    PORT
      LAYER M5 ;
        RECT  7.296 23.676 7.32 23.76 ;
    END
  END o[67]
  PIN o[68]
    DIRECTION OUTPUT ;
    USE SIGNAL ;
    PORT
      LAYER M3 ;
        RECT  7.416 23.722 7.434 23.76 ;
    END
  END o[68]
  PIN o[69]
    DIRECTION OUTPUT ;
    USE SIGNAL ;
    PORT
      LAYER M5 ;
        RECT  7.536 23.676 7.56 23.76 ;
    END
  END o[69]
  PIN o[6]
    DIRECTION OUTPUT ;
    USE SIGNAL ;
    PORT
      LAYER M3 ;
        RECT  1.224 23.722 1.242 23.76 ;
    END
  END o[6]
  PIN o[70]
    DIRECTION OUTPUT ;
    USE SIGNAL ;
    PORT
      LAYER M3 ;
        RECT  7.632 23.722 7.65 23.76 ;
    END
  END o[70]
  PIN o[71]
    DIRECTION OUTPUT ;
    USE SIGNAL ;
    PORT
      LAYER M5 ;
        RECT  7.728 23.676 7.752 23.76 ;
    END
  END o[71]
  PIN o[72]
    DIRECTION OUTPUT ;
    USE SIGNAL ;
    PORT
      LAYER M3 ;
        RECT  7.812 23.722 7.83 23.76 ;
    END
  END o[72]
  PIN o[73]
    DIRECTION OUTPUT ;
    USE SIGNAL ;
    PORT
      LAYER M5 ;
        RECT  7.92 23.676 7.944 23.76 ;
    END
  END o[73]
  PIN o[74]
    DIRECTION OUTPUT ;
    USE SIGNAL ;
    PORT
      LAYER M3 ;
        RECT  8.028 23.722 8.046 23.76 ;
    END
  END o[74]
  PIN o[75]
    DIRECTION OUTPUT ;
    USE SIGNAL ;
    PORT
      LAYER M5 ;
        RECT  8.112 23.676 8.136 23.76 ;
    END
  END o[75]
  PIN o[76]
    DIRECTION OUTPUT ;
    USE SIGNAL ;
    PORT
      LAYER M3 ;
        RECT  8.208 23.722 8.226 23.76 ;
    END
  END o[76]
  PIN o[77]
    DIRECTION OUTPUT ;
    USE SIGNAL ;
    PORT
      LAYER M5 ;
        RECT  8.304 23.676 8.328 23.76 ;
    END
  END o[77]
  PIN o[78]
    DIRECTION OUTPUT ;
    USE SIGNAL ;
    PORT
      LAYER M3 ;
        RECT  8.424 23.722 8.442 23.76 ;
    END
  END o[78]
  PIN o[79]
    DIRECTION OUTPUT ;
    USE SIGNAL ;
    PORT
      LAYER M5 ;
        RECT  8.496 23.676 8.52 23.76 ;
    END
  END o[79]
  PIN o[7]
    DIRECTION OUTPUT ;
    USE SIGNAL ;
    PORT
      LAYER M5 ;
        RECT  1.344 23.676 1.368 23.76 ;
    END
  END o[7]
  PIN o[80]
    DIRECTION OUTPUT ;
    USE SIGNAL ;
    PORT
      LAYER M3 ;
        RECT  8.604 23.722 8.622 23.76 ;
    END
  END o[80]
  PIN o[81]
    DIRECTION OUTPUT ;
    USE SIGNAL ;
    PORT
      LAYER M5 ;
        RECT  8.736 23.676 8.76 23.76 ;
    END
  END o[81]
  PIN o[82]
    DIRECTION OUTPUT ;
    USE SIGNAL ;
    PORT
      LAYER M3 ;
        RECT  8.82 23.722 8.838 23.76 ;
    END
  END o[82]
  PIN o[83]
    DIRECTION OUTPUT ;
    USE SIGNAL ;
    PORT
      LAYER M5 ;
        RECT  8.928 23.676 8.952 23.76 ;
    END
  END o[83]
  PIN o[84]
    DIRECTION OUTPUT ;
    USE SIGNAL ;
    PORT
      LAYER M3 ;
        RECT  9 23.722 9.018 23.76 ;
    END
  END o[84]
  PIN o[85]
    DIRECTION OUTPUT ;
    USE SIGNAL ;
    PORT
      LAYER M5 ;
        RECT  9.12 23.676 9.144 23.76 ;
    END
  END o[85]
  PIN o[86]
    DIRECTION OUTPUT ;
    USE SIGNAL ;
    PORT
      LAYER M3 ;
        RECT  9.216 23.722 9.234 23.76 ;
    END
  END o[86]
  PIN o[87]
    DIRECTION OUTPUT ;
    USE SIGNAL ;
    PORT
      LAYER M5 ;
        RECT  9.312 23.676 9.336 23.76 ;
    END
  END o[87]
  PIN o[88]
    DIRECTION OUTPUT ;
    USE SIGNAL ;
    PORT
      LAYER M3 ;
        RECT  9.396 23.722 9.414 23.76 ;
    END
  END o[88]
  PIN o[89]
    DIRECTION OUTPUT ;
    USE SIGNAL ;
    PORT
      LAYER M5 ;
        RECT  9.504 23.676 9.528 23.76 ;
    END
  END o[89]
  PIN o[8]
    DIRECTION OUTPUT ;
    USE SIGNAL ;
    PORT
      LAYER M3 ;
        RECT  1.44 23.722 1.458 23.76 ;
    END
  END o[8]
  PIN o[90]
    DIRECTION OUTPUT ;
    USE SIGNAL ;
    PORT
      LAYER M3 ;
        RECT  9.612 23.722 9.63 23.76 ;
    END
  END o[90]
  PIN o[91]
    DIRECTION OUTPUT ;
    USE SIGNAL ;
    PORT
      LAYER M5 ;
        RECT  9.696 23.676 9.72 23.76 ;
    END
  END o[91]
  PIN o[92]
    DIRECTION OUTPUT ;
    USE SIGNAL ;
    PORT
      LAYER M3 ;
        RECT  9.828 23.722 9.846 23.76 ;
    END
  END o[92]
  PIN o[93]
    DIRECTION OUTPUT ;
    USE SIGNAL ;
    PORT
      LAYER M5 ;
        RECT  9.888 23.676 9.912 23.76 ;
    END
  END o[93]
  PIN o[94]
    DIRECTION OUTPUT ;
    USE SIGNAL ;
    PORT
      LAYER M3 ;
        RECT  10.008 23.722 10.026 23.76 ;
    END
  END o[94]
  PIN o[95]
    DIRECTION OUTPUT ;
    USE SIGNAL ;
    PORT
      LAYER M5 ;
        RECT  10.128 23.676 10.152 23.76 ;
    END
  END o[95]
  PIN o[96]
    DIRECTION OUTPUT ;
    USE SIGNAL ;
    PORT
      LAYER M3 ;
        RECT  10.224 23.722 10.242 23.76 ;
    END
  END o[96]
  PIN o[97]
    DIRECTION OUTPUT ;
    USE SIGNAL ;
    PORT
      LAYER M5 ;
        RECT  10.32 23.676 10.344 23.76 ;
    END
  END o[97]
  PIN o[98]
    DIRECTION OUTPUT ;
    USE SIGNAL ;
    PORT
      LAYER M3 ;
        RECT  10.404 23.722 10.422 23.76 ;
    END
  END o[98]
  PIN o[99]
    DIRECTION OUTPUT ;
    USE SIGNAL ;
    PORT
      LAYER M5 ;
        RECT  10.512 23.676 10.536 23.76 ;
    END
  END o[99]
  PIN o[9]
    DIRECTION OUTPUT ;
    USE SIGNAL ;
    PORT
      LAYER M5 ;
        RECT  1.536 23.676 1.56 23.76 ;
    END
  END o[9]
  PIN rfi
    DIRECTION INPUT ;
    USE SIGNAL ;
    PORT
      LAYER M3 ;
        RECT  32.4 0 32.418 0.038 ;
    END
  END rfi
  PIN rfo
    DIRECTION OUTPUT ;
    USE SIGNAL ;
    PORT
      LAYER M3 ;
        RECT  32.4 23.722 32.418 23.76 ;
    END
  END rfo
  PIN rs
    DIRECTION INPUT ;
    USE SIGNAL ;
    PORT
      LAYER M4 ;
        RECT  0 17.328 0.084 17.352 ;
    END
  END rs
  PIN rso
    DIRECTION OUTPUT ;
    USE SIGNAL ;
    PORT
      LAYER M3 ;
        RECT  63.792 23.722 63.81 23.76 ;
    END
  END rso
  PIN VDD
    DIRECTION INOUT ;
    USE POWER ;
    PORT
      LAYER M5 ;
        RECT  61.992 2.151 62.112 21.609 ;
        RECT  59.292 2.151 59.412 21.609 ;
        RECT  56.592 2.151 56.712 21.609 ;
        RECT  53.892 2.151 54.012 21.609 ;
        RECT  51.192 2.151 51.312 21.609 ;
        RECT  48.492 2.151 48.612 21.609 ;
        RECT  45.792 2.151 45.912 21.609 ;
        RECT  43.092 2.151 43.212 21.609 ;
        RECT  40.392 2.151 40.512 21.609 ;
        RECT  37.692 2.151 37.812 21.609 ;
        RECT  34.992 2.151 35.112 21.609 ;
        RECT  32.292 2.151 32.412 21.609 ;
        RECT  29.592 2.151 29.712 21.609 ;
        RECT  26.892 2.151 27.012 21.609 ;
        RECT  24.192 2.151 24.312 21.609 ;
        RECT  21.492 2.151 21.612 21.609 ;
        RECT  18.792 2.151 18.912 21.609 ;
        RECT  16.092 2.151 16.212 21.609 ;
        RECT  13.392 2.151 13.512 21.609 ;
        RECT  10.692 2.151 10.812 21.609 ;
        RECT  7.992 2.151 8.112 21.609 ;
        RECT  5.292 2.151 5.412 21.609 ;
        RECT  2.592 2.151 2.712 21.609 ;
    END
  END VDD
  PIN VSS
    DIRECTION INOUT ;
    USE GROUND ;
    PORT
      LAYER M5 ;
        RECT  61.8 2.137 61.92 21.623 ;
        RECT  59.1 2.137 59.22 21.623 ;
        RECT  56.4 2.137 56.52 21.623 ;
        RECT  53.7 2.137 53.82 21.623 ;
        RECT  51 2.137 51.12 21.623 ;
        RECT  48.3 2.137 48.42 21.623 ;
        RECT  45.6 2.137 45.72 21.623 ;
        RECT  42.9 2.137 43.02 21.623 ;
        RECT  40.2 2.137 40.32 21.623 ;
        RECT  37.5 2.137 37.62 21.623 ;
        RECT  34.8 2.137 34.92 21.623 ;
        RECT  32.1 2.137 32.22 21.623 ;
        RECT  29.4 2.137 29.52 21.623 ;
        RECT  26.7 2.137 26.82 21.623 ;
        RECT  24 2.137 24.12 21.623 ;
        RECT  21.3 2.137 21.42 21.623 ;
        RECT  18.6 2.137 18.72 21.623 ;
        RECT  15.9 2.137 16.02 21.623 ;
        RECT  13.2 2.137 13.32 21.623 ;
        RECT  10.5 2.137 10.62 21.623 ;
        RECT  7.8 2.137 7.92 21.623 ;
        RECT  5.1 2.137 5.22 21.623 ;
        RECT  2.4 2.137 2.52 21.623 ;
    END
  END VSS
  OBS
    LAYER RVTN ;
     RECT  2.16 2.16 62.64 2.295 ;
     RECT  2.16 2.565 62.64 2.835 ;
     RECT  2.16 3.105 62.64 3.375 ;
     RECT  2.16 3.645 62.64 3.915 ;
     RECT  2.16 4.185 62.64 4.455 ;
     RECT  2.16 4.725 62.64 4.995 ;
     RECT  2.16 5.265 62.64 5.535 ;
     RECT  2.16 5.805 62.64 6.075 ;
     RECT  2.16 6.345 62.64 6.615 ;
     RECT  2.16 6.885 62.64 7.155 ;
     RECT  2.16 7.425 62.64 7.695 ;
     RECT  2.16 7.965 62.64 8.235 ;
     RECT  2.16 8.505 62.64 8.775 ;
     RECT  2.16 9.045 62.64 9.315 ;
     RECT  2.16 9.585 62.64 9.855 ;
     RECT  2.16 10.125 62.64 10.395 ;
     RECT  2.16 10.665 62.64 10.935 ;
     RECT  2.16 11.205 62.64 11.475 ;
     RECT  2.16 11.745 62.64 12.015 ;
     RECT  2.16 12.285 62.64 12.555 ;
     RECT  2.16 12.825 62.64 13.095 ;
     RECT  2.16 13.365 62.64 13.635 ;
     RECT  2.16 13.905 62.64 14.175 ;
     RECT  2.16 14.445 62.64 14.715 ;
     RECT  2.16 14.985 62.64 15.255 ;
     RECT  2.16 15.525 62.64 15.795 ;
     RECT  2.16 16.065 62.64 16.335 ;
     RECT  2.16 16.605 62.64 16.875 ;
     RECT  2.16 17.145 62.64 17.415 ;
     RECT  2.16 17.685 62.64 17.955 ;
     RECT  2.16 18.225 62.64 18.495 ;
     RECT  2.16 18.765 62.64 19.035 ;
     RECT  2.16 19.305 62.64 19.575 ;
     RECT  2.16 19.845 62.64 20.115 ;
     RECT  2.16 20.385 62.64 20.655 ;
     RECT  2.16 20.925 62.64 21.195 ;
     RECT  2.16 21.465 62.64 21.6 ;
    LAYER RVTP ;
     RECT  2.16 2.295 62.64 2.565 ;
     RECT  2.16 2.835 62.64 3.105 ;
     RECT  2.16 3.375 62.64 3.645 ;
     RECT  2.16 3.915 62.64 4.185 ;
     RECT  2.16 4.455 62.64 4.725 ;
     RECT  2.16 4.995 62.64 5.265 ;
     RECT  2.16 5.535 62.64 5.805 ;
     RECT  2.16 6.075 62.64 6.345 ;
     RECT  2.16 6.615 62.64 6.885 ;
     RECT  2.16 7.155 62.64 7.425 ;
     RECT  2.16 7.695 62.64 7.965 ;
     RECT  2.16 8.235 62.64 8.505 ;
     RECT  2.16 8.775 62.64 9.045 ;
     RECT  2.16 9.315 62.64 9.585 ;
     RECT  2.16 9.855 62.64 10.125 ;
     RECT  2.16 10.395 62.64 10.665 ;
     RECT  2.16 10.935 62.64 11.205 ;
     RECT  2.16 11.475 62.64 11.745 ;
     RECT  2.16 12.015 62.64 12.285 ;
     RECT  2.16 12.555 62.64 12.825 ;
     RECT  2.16 13.095 62.64 13.365 ;
     RECT  2.16 13.635 62.64 13.905 ;
     RECT  2.16 14.175 62.64 14.445 ;
     RECT  2.16 14.715 62.64 14.985 ;
     RECT  2.16 15.255 62.64 15.525 ;
     RECT  2.16 15.795 62.64 16.065 ;
     RECT  2.16 16.335 62.64 16.605 ;
     RECT  2.16 16.875 62.64 17.145 ;
     RECT  2.16 17.415 62.64 17.685 ;
     RECT  2.16 17.955 62.64 18.225 ;
     RECT  2.16 18.495 62.64 18.765 ;
     RECT  2.16 19.035 62.64 19.305 ;
     RECT  2.16 19.575 62.64 19.845 ;
     RECT  2.16 20.115 62.64 20.385 ;
     RECT  2.16 20.655 62.64 20.925 ;
     RECT  2.16 21.195 62.64 21.465 ;
    LAYER M1 ;
     RECT  2.16 2.151 62.64 21.609 ;
    LAYER M2 ;
     RECT  0.643 4.23 0.823 4.248 ;
     RECT  0.823 4.23 1.039 4.788 ;
     RECT  1.039 17.316 1.147 17.334 ;
     RECT  1.039 4.23 1.435 5.22 ;
     RECT  1.147 17.316 1.435 17.406 ;
     RECT  0.751 20.196 1.579 20.214 ;
     RECT  0.643 21.096 1.579 21.114 ;
     RECT  1.579 11.016 1.615 11.034 ;
     RECT  1.579 20.196 1.615 21.114 ;
     RECT  1.435 4.23 1.651 5.328 ;
     RECT  1.435 17.316 1.687 17.442 ;
     RECT  1.219 16.506 1.723 16.524 ;
     RECT  1.687 17.316 1.723 17.676 ;
     RECT  1.723 16.506 1.831 17.676 ;
     RECT  1.615 20.196 1.831 21.258 ;
     RECT  1.651 3.582 1.903 5.328 ;
     RECT  0.823 19.116 2.047 19.134 ;
     RECT  2.011 2.106 2.083 2.124 ;
     RECT  1.903 3.384 2.083 5.328 ;
     RECT  1.903 8.982 2.083 9 ;
     RECT  2.083 8.982 2.155 9.54 ;
     RECT  2.047 19.116 2.155 19.404 ;
     RECT  1.831 20.196 2.155 21.654 ;
     RECT  2.083 2.106 2.16 5.328 ;
     RECT  2.155 8.442 2.16 9.54 ;
     RECT  1.615 11.016 2.16 11.574 ;
     RECT  2.011 14.22 2.16 14.238 ;
     RECT  1.831 16.344 2.16 17.676 ;
     RECT  2.155 19.116 2.16 21.654 ;
     RECT  2.16 2.106 2.443 21.654 ;
     RECT  2.443 1.728 2.839 21.69 ;
     RECT  2.839 0.036 2.939 0.054 ;
     RECT  2.839 1.728 2.975 21.762 ;
     RECT  2.975 1.728 3.235 21.726 ;
     RECT  3.235 1.152 3.335 21.726 ;
     RECT  3.335 1.728 3.811 21.726 ;
     RECT  4.027 0.036 4.091 0.054 ;
     RECT  3.811 1.728 5.099 21.798 ;
     RECT  5.215 22.788 5.495 22.806 ;
     RECT  5.431 0.036 5.531 0.054 ;
     RECT  5.099 1.728 5.783 21.654 ;
     RECT  5.783 1.8 5.891 21.654 ;
     RECT  6.043 22.824 6.619 22.842 ;
     RECT  6.403 0.036 7.115 0.054 ;
     RECT  6.619 22.788 7.231 22.842 ;
     RECT  7.231 22.752 7.331 22.842 ;
     RECT  5.891 2.151 7.627 21.654 ;
     RECT  8.023 0.108 8.203 0.126 ;
     RECT  8.203 0.036 8.231 0.126 ;
     RECT  7.331 22.788 8.239 22.806 ;
     RECT  7.627 1.728 8.303 21.69 ;
     RECT  8.231 0.036 8.339 0.054 ;
     RECT  8.303 1.8 8.411 21.69 ;
     RECT  8.419 23.706 8.519 23.724 ;
     RECT  8.411 1.8 8.591 21.654 ;
     RECT  8.239 22.716 8.815 22.806 ;
     RECT  8.815 22.716 8.987 22.842 ;
     RECT  8.987 22.716 9.023 22.734 ;
     RECT  8.591 2.151 9.211 21.654 ;
     RECT  9.211 2.151 9.491 21.69 ;
     RECT  9.175 0.036 9.679 0.054 ;
     RECT  9.679 0.036 10.247 0.126 ;
     RECT  9.491 2.151 10.327 21.654 ;
     RECT  10.327 2.151 10.427 21.762 ;
     RECT  10.427 2.151 10.643 21.69 ;
     RECT  10.247 0.036 10.715 0.09 ;
     RECT  10.715 0.036 11.291 0.054 ;
     RECT  10.643 2.151 11.731 21.609 ;
     RECT  11.731 2.151 11.831 21.69 ;
     RECT  11.803 1.152 11.903 1.17 ;
     RECT  11.831 2.151 13.207 21.654 ;
     RECT  13.387 22.824 13.495 22.842 ;
     RECT  13.387 0.036 13.559 0.054 ;
     RECT  13.495 22.752 13.631 22.914 ;
     RECT  13.631 22.752 14.035 22.806 ;
     RECT  14.035 22.716 14.207 22.806 ;
     RECT  14.395 0.036 14.495 0.054 ;
     RECT  13.207 1.728 14.999 21.654 ;
     RECT  14.999 2.151 15.323 21.654 ;
     RECT  14.207 22.788 15.511 22.806 ;
     RECT  15.511 22.752 15.611 22.806 ;
     RECT  15.619 22.824 15.827 22.842 ;
     RECT  15.323 2.151 16.195 21.609 ;
     RECT  15.583 0.036 16.691 0.054 ;
     RECT  16.591 22.824 16.763 22.842 ;
     RECT  16.195 2.151 17.167 21.654 ;
     RECT  17.167 2.151 17.599 21.69 ;
     RECT  17.599 1.728 17.987 21.69 ;
     RECT  17.995 23.706 18.167 23.724 ;
     RECT  17.987 2.151 18.175 21.69 ;
     RECT  18.067 0.036 18.203 0.054 ;
     RECT  18.175 2.151 18.787 21.726 ;
     RECT  18.787 1.728 18.887 21.834 ;
     RECT  18.887 1.728 18.959 21.726 ;
     RECT  18.959 2.151 19.283 21.726 ;
     RECT  19.363 0.576 19.579 0.594 ;
     RECT  19.579 0.036 19.679 0.594 ;
     RECT  19.283 2.151 19.759 21.69 ;
     RECT  19.679 0.576 20.039 0.594 ;
     RECT  19.759 1.728 20.291 21.69 ;
     RECT  20.291 2.151 21.163 21.69 ;
     RECT  21.163 2.151 21.379 21.726 ;
     RECT  20.983 0.036 21.659 0.054 ;
     RECT  21.379 1.728 21.767 21.726 ;
     RECT  21.767 2.151 22.351 21.726 ;
     RECT  22.351 2.151 22.775 21.834 ;
     RECT  22.775 2.151 22.783 21.762 ;
     RECT  22.963 0.036 23.063 0.054 ;
     RECT  22.783 1.728 23.603 21.762 ;
     RECT  23.575 23.706 23.819 23.724 ;
     RECT  23.603 1.728 24.359 21.69 ;
     RECT  24.359 1.728 24.611 21.654 ;
     RECT  24.611 2.151 25.043 21.654 ;
     RECT  24.151 0.036 25.655 0.054 ;
     RECT  25.043 2.151 26.383 21.609 ;
     RECT  26.383 2.151 26.743 21.726 ;
     RECT  26.743 1.728 26.771 21.726 ;
     RECT  26.959 0.036 27.167 0.054 ;
     RECT  26.771 1.728 27.167 21.69 ;
     RECT  27.167 2.151 27.535 21.69 ;
     RECT  27.535 2.151 27.923 21.762 ;
     RECT  27.931 0.036 28.247 0.054 ;
     RECT  27.923 2.151 28.535 21.654 ;
     RECT  29.335 22.824 29.371 22.842 ;
     RECT  29.371 22.824 29.579 22.914 ;
     RECT  29.731 22.788 29.947 22.806 ;
     RECT  28.535 2.151 30.127 21.609 ;
     RECT  30.127 1.728 30.199 21.609 ;
     RECT  29.947 22.752 30.523 22.806 ;
     RECT  30.523 22.752 30.631 22.842 ;
     RECT  30.631 22.752 30.767 22.914 ;
     RECT  30.199 1.728 30.983 21.654 ;
     RECT  30.767 22.752 31.163 22.806 ;
     RECT  31.163 22.788 31.307 22.806 ;
     RECT  30.983 2.151 31.999 21.654 ;
     RECT  31.927 22.824 32.099 22.842 ;
     RECT  30.955 0.036 32.279 0.054 ;
     RECT  31.999 2.151 32.323 21.69 ;
     RECT  32.323 1.728 32.603 21.834 ;
     RECT  32.603 1.728 33.619 21.654 ;
     RECT  33.619 1.728 33.755 21.69 ;
     RECT  33.943 22.824 34.015 22.842 ;
     RECT  34.015 22.788 34.619 22.842 ;
     RECT  34.619 22.788 34.627 22.806 ;
     RECT  34.627 22.716 34.691 22.806 ;
     RECT  34.691 22.716 34.763 22.734 ;
     RECT  34.339 0.036 34.943 0.054 ;
     RECT  33.755 1.728 35.923 21.654 ;
     RECT  36.499 22.896 36.535 22.914 ;
     RECT  35.923 1.728 36.707 21.726 ;
     RECT  36.535 22.824 36.743 22.914 ;
     RECT  36.743 22.824 36.923 22.842 ;
     RECT  36.707 2.151 37.327 21.726 ;
     RECT  37.111 22.671 37.327 22.689 ;
     RECT  37.327 2.151 37.723 22.689 ;
     RECT  37.723 2.151 37.903 22.842 ;
     RECT  37.903 1.728 38.111 22.914 ;
     RECT  38.111 1.728 38.399 22.842 ;
     RECT  37.435 0.036 38.759 0.054 ;
     RECT  38.399 1.728 38.759 21.69 ;
     RECT  38.399 22.671 38.759 22.842 ;
     RECT  38.759 2.151 38.795 21.69 ;
     RECT  38.795 2.151 38.903 21.654 ;
     RECT  38.759 22.824 39.227 22.842 ;
     RECT  38.903 2.151 40.099 21.609 ;
     RECT  40.099 1.728 40.135 21.609 ;
     RECT  40.135 1.728 40.343 21.69 ;
     RECT  40.135 0.036 40.595 0.054 ;
     RECT  39.919 22.788 40.603 22.806 ;
     RECT  40.603 22.752 40.883 22.842 ;
     RECT  40.343 1.728 41.107 21.654 ;
     RECT  41.107 1.728 41.387 21.69 ;
     RECT  40.883 22.824 42.143 22.842 ;
     RECT  41.387 1.728 42.395 21.654 ;
     RECT  42.395 2.151 42.583 21.654 ;
     RECT  42.295 23.706 42.647 23.724 ;
     RECT  42.907 0.036 43.079 0.054 ;
     RECT  43.087 0.108 43.295 0.126 ;
     RECT  42.583 2.151 43.303 21.69 ;
     RECT  43.303 2.151 43.403 21.726 ;
     RECT  43.403 2.151 43.699 21.654 ;
     RECT  43.915 22.788 44.095 22.806 ;
     RECT  44.095 22.788 44.123 22.878 ;
     RECT  43.303 0.576 44.159 0.594 ;
     RECT  44.123 22.86 44.375 22.878 ;
     RECT  43.699 1.728 44.491 21.654 ;
     RECT  44.491 1.728 44.591 21.69 ;
     RECT  44.779 23.706 44.915 23.724 ;
     RECT  44.591 1.728 45.239 21.654 ;
     RECT  45.239 2.151 45.679 21.654 ;
     RECT  45.679 2.151 45.995 21.69 ;
     RECT  45.995 2.151 46.075 21.654 ;
     RECT  46.075 1.728 46.643 21.654 ;
     RECT  46.643 2.151 47.299 21.654 ;
     RECT  47.299 2.151 47.543 21.762 ;
     RECT  47.543 2.151 48.271 21.726 ;
     RECT  45.679 0.036 48.659 0.054 ;
     RECT  48.271 1.728 48.767 21.726 ;
     RECT  48.487 23.706 48.875 23.724 ;
     RECT  48.767 2.151 48.983 21.726 ;
     RECT  48.983 2.151 49.019 21.69 ;
     RECT  49.279 22.716 49.351 22.734 ;
     RECT  49.279 0.108 49.495 0.126 ;
     RECT  49.495 0.036 49.523 0.126 ;
     RECT  49.351 22.716 49.523 22.806 ;
     RECT  49.523 22.752 49.891 22.806 ;
     RECT  49.523 0.036 49.991 0.054 ;
     RECT  49.891 22.752 50.179 22.842 ;
     RECT  50.179 22.752 50.279 22.914 ;
     RECT  50.279 22.824 50.495 22.914 ;
     RECT  49.019 2.151 50.935 21.654 ;
     RECT  50.971 0.036 51.107 0.054 ;
     RECT  50.935 2.151 51.107 21.69 ;
     RECT  51.107 2.151 51.259 21.654 ;
     RECT  51.259 1.728 51.395 21.654 ;
     RECT  50.495 22.824 51.503 22.842 ;
     RECT  52.087 22.788 52.159 22.806 ;
     RECT  52.159 22.716 52.295 22.806 ;
     RECT  52.295 22.788 52.763 22.806 ;
     RECT  51.395 2.151 52.879 21.654 ;
     RECT  52.879 22.824 52.979 22.842 ;
     RECT  52.879 1.728 53.231 21.654 ;
     RECT  53.059 0.036 53.375 0.054 ;
     RECT  53.851 0.576 54.139 0.594 ;
     RECT  54.139 0.036 54.275 0.594 ;
     RECT  53.231 2.151 54.859 21.654 ;
     RECT  54.275 0.576 54.923 0.594 ;
     RECT  54.859 2.151 55.075 21.762 ;
     RECT  55.075 2.151 55.175 21.834 ;
     RECT  55.175 2.151 55.255 21.654 ;
     RECT  55.255 1.728 55.607 21.654 ;
     RECT  55.607 2.151 55.975 21.654 ;
     RECT  56.443 0.036 56.975 0.054 ;
     RECT  55.975 2.151 57.451 21.69 ;
     RECT  57.451 2.151 58.207 21.726 ;
     RECT  58.207 2.034 58.459 21.726 ;
     RECT  57.091 22.788 58.783 22.806 ;
     RECT  58.783 22.716 59.063 22.842 ;
     RECT  59.063 22.788 59.243 22.842 ;
     RECT  58.459 1.728 59.611 21.726 ;
     RECT  59.243 22.824 59.639 22.842 ;
     RECT  59.431 0.108 59.647 0.126 ;
     RECT  59.647 0.036 59.675 0.126 ;
     RECT  59.647 22.896 59.747 22.914 ;
     RECT  59.611 1.728 59.927 21.762 ;
     RECT  59.675 0.036 60.359 0.054 ;
     RECT  60.439 22.824 60.647 22.842 ;
     RECT  59.927 1.728 60.835 21.726 ;
     RECT  60.835 1.152 60.971 21.726 ;
     RECT  60.971 1.728 61.763 21.726 ;
     RECT  61.763 2.151 62.411 21.726 ;
     RECT  62.455 22.626 62.563 22.644 ;
     RECT  61.591 0.036 62.627 0.054 ;
     RECT  62.411 2.151 62.64 21.609 ;
     RECT  62.64 3.546 62.663 3.564 ;
     RECT  62.64 17.496 62.663 17.514 ;
     RECT  62.563 22.626 62.663 22.77 ;
     RECT  62.635 1.152 62.699 1.17 ;
     RECT  62.64 5.238 62.699 5.598 ;
     RECT  62.663 22.671 62.699 22.689 ;
     RECT  62.699 5.58 62.735 5.598 ;
     RECT  62.64 13.986 62.735 16.596 ;
     RECT  62.735 13.986 62.771 16.524 ;
     RECT  62.64 20.124 62.807 21.456 ;
     RECT  62.64 10.476 62.879 11.97 ;
     RECT  62.64 19.008 62.879 19.134 ;
     RECT  62.771 13.986 62.951 14.004 ;
     RECT  62.807 20.628 62.951 21.456 ;
     RECT  62.771 14.796 62.987 16.524 ;
     RECT  62.879 11.376 63.023 11.97 ;
     RECT  62.951 20.628 63.023 21.222 ;
     RECT  62.879 10.476 63.059 10.494 ;
     RECT  63.023 20.628 63.059 21.186 ;
     RECT  63.023 11.826 63.095 11.97 ;
     RECT  63.059 21.168 63.095 21.186 ;
     RECT  63.095 11.952 63.131 11.97 ;
     RECT  62.879 19.008 63.131 19.026 ;
     RECT  62.987 14.796 63.311 15.174 ;
     RECT  63.311 14.886 63.347 15.174 ;
     RECT  63.347 15.156 63.383 15.174 ;
     RECT  62.987 16.038 63.419 16.524 ;
     RECT  63.419 16.038 63.815 16.056 ;
    LAYER M3 ;
     RECT  0.648 0.012 62.658 1.147 ;
     RECT  0.648 1.147 62.694 3.403 ;
     RECT  0.648 3.403 62.73 4.145 ;
     RECT  0.648 4.145 34.038 4.253 ;
     RECT  0.828 4.253 34.038 4.793 ;
     RECT  1.044 4.793 34.038 5.225 ;
     RECT  1.44 5.225 34.038 5.333 ;
     RECT  34.815 4.145 62.73 5.603 ;
     RECT  1.908 5.333 34.038 6.619 ;
     RECT  34.815 5.603 62.55 6.619 ;
     RECT  1.908 6.619 62.55 6.845 ;
     RECT  34.815 6.845 62.55 7.115 ;
     RECT  34.815 7.115 62.19 7.655 ;
     RECT  1.908 6.845 34.038 9.005 ;
     RECT  2.088 9.005 34.038 9.115 ;
     RECT  34.815 7.655 62.097 9.115 ;
     RECT  2.088 9.115 62.097 9.319 ;
     RECT  2.088 9.319 62.154 9.391 ;
     RECT  2.088 9.391 62.586 9.545 ;
     RECT  2.196 9.545 62.586 10.253 ;
     RECT  52.488 10.253 62.586 10.471 ;
     RECT  2.196 10.253 34.038 10.859 ;
     RECT  2.196 10.859 33.966 11.011 ;
     RECT  34.815 10.253 51.678 11.419 ;
     RECT  52.488 10.471 63.054 11.419 ;
     RECT  34.815 11.419 63.054 11.821 ;
     RECT  34.815 11.821 63.09 11.947 ;
     RECT  1.584 11.011 33.966 12.325 ;
     RECT  34.815 11.947 63.126 12.325 ;
     RECT  1.584 12.325 63.126 14.791 ;
     RECT  1.584 14.791 63.306 14.881 ;
     RECT  1.584 14.881 63.342 15.151 ;
     RECT  1.584 15.151 63.378 16.033 ;
     RECT  1.584 16.033 63.81 16.501 ;
     RECT  1.224 16.501 63.81 17.311 ;
     RECT  0.108 17.323 0.126 17.453 ;
     RECT  1.044 17.311 63.81 19.111 ;
     RECT  0.828 19.111 63.81 20.191 ;
     RECT  0.756 20.191 63.81 21.091 ;
     RECT  0.648 21.091 63.81 22.781 ;
     RECT  0.648 22.781 62.982 22.829 ;
     RECT  0.648 22.829 62.658 23.741 ;
     RECT  63.792 22.781 63.81 23.741 ;
    LAYER M4 ;
     RECT  0.06 17.328 0.097 17.352 ;
     RECT  0.097 17.328 0.137 17.448 ;
     RECT  0.06 6.432 0.227 6.456 ;
     RECT  0.701 20.496 0.785 20.52 ;
     RECT  0.137 17.424 0.949 17.448 ;
     RECT  0.709 4.656 1.141 4.68 ;
     RECT  0.949 17.424 1.525 18.216 ;
     RECT  1.141 4.032 1.709 4.68 ;
     RECT  1.525 17.424 1.717 18.792 ;
     RECT  0.949 2.88 1.909 2.904 ;
     RECT  1.709 3.984 1.909 4.68 ;
     RECT  0.181 14.4 2.077 14.424 ;
     RECT  1.717 17.424 2.113 19.368 ;
     RECT  2.077 14.4 2.149 14.664 ;
     RECT  2.149 14.4 2.197 15.24 ;
     RECT  1.909 21.36 2.197 21.384 ;
     RECT  2.197 13.584 2.245 15.24 ;
     RECT  2.197 21.12 2.245 21.384 ;
     RECT  2.113 16.56 2.257 19.368 ;
     RECT  2.245 20.88 2.257 21.384 ;
     RECT  2.257 16.56 2.293 21.384 ;
     RECT  2.293 0.24 2.341 0.264 ;
     RECT  2.245 13.056 2.365 15.24 ;
     RECT  2.293 16.56 2.365 21.768 ;
     RECT  2.365 13.056 2.387 21.768 ;
     RECT  2.069 1.728 2.408 1.752 ;
     RECT  1.909 2.88 2.408 4.68 ;
     RECT  2.387 13.056 2.408 21.672 ;
     RECT  2.101 22.752 2.533 22.776 ;
     RECT  2.408 1.728 2.704 21.672 ;
     RECT  2.341 0.144 2.819 0.264 ;
     RECT  2.704 13.008 2.819 21.672 ;
     RECT  2.819 0.24 2.867 0.264 ;
     RECT  2.819 13.056 3.197 21.672 ;
     RECT  2.704 1.728 3.269 1.752 ;
     RECT  2.704 2.832 3.557 5.16 ;
     RECT  3.557 2.832 3.683 3.96 ;
     RECT  2.533 22.752 3.733 23.592 ;
     RECT  2.704 7.968 3.845 9.144 ;
     RECT  3.557 5.136 3.881 5.16 ;
     RECT  3.197 13.056 3.917 21.192 ;
     RECT  3.733 22.752 3.917 23.64 ;
     RECT  3.845 9.072 3.923 9.144 ;
     RECT  3.683 2.88 3.989 3.96 ;
     RECT  3.917 13.104 4.381 21.192 ;
     RECT  4.309 1.728 4.421 1.752 ;
     RECT  4.381 13.104 4.693 21.24 ;
     RECT  4.789 6.288 4.892 6.312 ;
     RECT  4.693 13.104 4.933 21.48 ;
     RECT  3.989 2.88 4.981 3.528 ;
     RECT  4.933 13.104 4.981 21.528 ;
     RECT  4.981 2.88 5.108 3.96 ;
     RECT  4.892 6.288 5.108 6.84 ;
     RECT  3.845 7.968 5.108 7.992 ;
     RECT  4.165 9.696 5.108 9.72 ;
     RECT  2.704 10.848 5.108 12.024 ;
     RECT  4.981 13.056 5.108 21.528 ;
     RECT  4.201 23.664 5.125 23.688 ;
     RECT  5.108 2.148 5.212 21.612 ;
     RECT  5.125 0.336 5.317 0.36 ;
     RECT  5.125 23.568 5.317 23.688 ;
     RECT  5.212 2.418 5.404 21.612 ;
     RECT  5.317 0.24 5.509 0.36 ;
     RECT  5.509 0.096 5.555 0.36 ;
     RECT  5.555 0.096 5.603 0.264 ;
     RECT  5.404 13.056 5.605 21.612 ;
     RECT  5.603 0.096 5.651 0.12 ;
     RECT  5.404 2.784 5.681 3.72 ;
     RECT  5.404 6.72 5.699 8.568 ;
     RECT  5.699 6.768 5.717 7.992 ;
     RECT  5.681 2.784 5.747 3.672 ;
     RECT  5.717 7.44 5.987 7.992 ;
     RECT  5.747 2.784 6.121 3.624 ;
     RECT  5.987 7.968 6.131 7.992 ;
     RECT  5.404 9.696 6.257 9.72 ;
     RECT  5.317 23.328 6.275 23.688 ;
     RECT  6.275 23.328 6.323 23.592 ;
     RECT  5.404 11.52 6.397 11.784 ;
     RECT  6.121 3.312 6.437 3.624 ;
     RECT  6.397 11.52 6.515 11.976 ;
     RECT  5.605 13.056 6.524 21.672 ;
     RECT  6.524 13.008 6.611 21.672 ;
     RECT  6.325 1.728 6.796 1.752 ;
     RECT  6.515 11.52 6.949 11.784 ;
     RECT  7.081 6.24 7.261 6.264 ;
     RECT  7.261 5.664 7.292 6.264 ;
     RECT  6.437 3.312 7.381 3.528 ;
     RECT  6.325 22.752 7.388 22.776 ;
     RECT  7.388 22.752 7.475 23.688 ;
     RECT  6.829 9.12 7.573 9.144 ;
     RECT  7.475 22.752 7.625 23.64 ;
     RECT  6.611 13.056 7.657 21.672 ;
     RECT  7.625 22.848 7.661 23.64 ;
     RECT  7.621 0.096 7.669 0.12 ;
     RECT  7.573 8.736 7.669 9.144 ;
     RECT  6.949 11.232 7.669 11.784 ;
     RECT  7.381 2.736 7.808 3.528 ;
     RECT  7.292 5.664 7.808 6.84 ;
     RECT  7.669 8.544 7.808 9.144 ;
     RECT  7.669 11.184 7.808 11.784 ;
     RECT  7.657 13.056 7.808 21.768 ;
     RECT  7.808 2.148 7.912 21.768 ;
     RECT  7.669 0.096 7.955 0.216 ;
     RECT  7.912 2.418 7.955 21.768 ;
     RECT  7.955 2.418 7.985 21.72 ;
     RECT  7.985 2.418 8.104 21.342 ;
     RECT  7.955 0.096 8.243 0.12 ;
     RECT  8.104 8.544 8.245 8.664 ;
     RECT  8.245 8.544 8.387 8.568 ;
     RECT  7.661 23.616 8.453 23.64 ;
     RECT  8.104 2.688 8.915 4.584 ;
     RECT  8.104 6.816 9.089 6.84 ;
     RECT  9.089 6.816 9.109 6.888 ;
     RECT  8.104 11.184 9.109 21.336 ;
     RECT  9.125 9.696 9.209 9.72 ;
     RECT  9.109 11.184 9.251 21.528 ;
     RECT  9.341 8.016 9.413 8.04 ;
     RECT  9.251 11.184 9.425 18.84 ;
     RECT  9.251 19.968 9.493 21.528 ;
     RECT  9.413 7.968 9.497 8.04 ;
     RECT  9.637 1.104 9.731 1.128 ;
     RECT  9.109 6.768 9.817 6.888 ;
     RECT  8.915 2.688 9.925 4.008 ;
     RECT  9.385 23.568 10.069 23.592 ;
     RECT  9.493 19.968 10.249 21.672 ;
     RECT  10.069 22.8 10.253 23.592 ;
     RECT  9.925 2.208 10.261 4.008 ;
     RECT  10.261 2.208 10.309 4.152 ;
     RECT  10.309 1.728 10.508 4.152 ;
     RECT  9.817 6.24 10.508 6.888 ;
     RECT  10.357 8.544 10.508 8.568 ;
     RECT  9.425 11.232 10.508 18.84 ;
     RECT  10.249 19.968 10.508 21.768 ;
     RECT  10.261 0.144 10.547 0.168 ;
     RECT  10.508 1.728 10.547 21.768 ;
     RECT  10.547 1.728 10.739 21.72 ;
     RECT  10.739 1.728 10.804 21.672 ;
     RECT  10.804 11.232 10.829 11.256 ;
     RECT  10.253 23.568 10.885 23.592 ;
     RECT  10.804 12.48 11.117 21.672 ;
     RECT  10.804 5.088 11.459 5.112 ;
     RECT  10.804 2.832 11.513 3.432 ;
     RECT  10.885 23.568 11.564 23.64 ;
     RECT  11.564 23.568 11.651 23.688 ;
     RECT  11.651 23.568 11.891 23.592 ;
     RECT  12.044 11.856 12.131 11.88 ;
     RECT  11.117 13.008 12.301 21.672 ;
     RECT  11.513 2.88 12.476 3.432 ;
     RECT  10.804 1.728 12.509 1.752 ;
     RECT  12.476 2.88 12.509 3.528 ;
     RECT  12.509 1.728 13.208 3.528 ;
     RECT  12.812 4.512 13.208 4.536 ;
     RECT  12.697 6.864 13.208 6.888 ;
     RECT  12.301 12.528 13.208 21.672 ;
     RECT  13.201 23.568 13.285 23.592 ;
     RECT  13.285 23.568 13.477 23.64 ;
     RECT  13.208 1.728 13.504 21.672 ;
     RECT  13.504 4.656 13.619 5.112 ;
     RECT  13.477 23.52 13.619 23.64 ;
     RECT  13.619 5.088 13.667 5.112 ;
     RECT  13.619 23.52 13.667 23.592 ;
     RECT  13.504 12.48 13.781 17.688 ;
     RECT  13.504 1.728 13.925 3.672 ;
     RECT  13.667 23.568 14.099 23.592 ;
     RECT  13.504 18.72 14.113 21.672 ;
     RECT  13.781 12.48 14.357 17.64 ;
     RECT  14.629 6.864 14.753 6.888 ;
     RECT  14.113 18.72 14.785 18.84 ;
     RECT  14.785 18.672 14.821 18.84 ;
     RECT  13.925 1.728 14.861 3.48 ;
     RECT  14.821 18.144 15.253 18.84 ;
     RECT  14.113 19.872 15.253 21.672 ;
     RECT  14.861 1.728 15.293 2.28 ;
     RECT  15.001 23.664 15.443 23.688 ;
     RECT  15.253 18.144 15.541 21.672 ;
     RECT  14.357 12.48 15.589 16.872 ;
     RECT  15.541 18 15.589 21.672 ;
     RECT  15.397 22.656 15.589 22.68 ;
     RECT  15.589 22.656 15.731 23.592 ;
     RECT  14.861 3.408 15.781 3.48 ;
     RECT  15.217 5.088 15.865 5.112 ;
     RECT  15.293 2.148 15.908 2.28 ;
     RECT  15.781 3.408 15.908 3.864 ;
     RECT  15.865 5.088 15.908 5.592 ;
     RECT  15.589 12.48 15.908 21.672 ;
     RECT  15.781 0.096 15.923 0.12 ;
     RECT  15.908 2.148 16.204 21.672 ;
     RECT  16.069 0.144 16.261 0.168 ;
     RECT  16.204 20.976 16.261 21.672 ;
     RECT  16.261 0.144 16.355 0.264 ;
     RECT  16.355 0.24 16.403 0.264 ;
     RECT  15.731 22.752 16.403 23.592 ;
     RECT  16.204 2.148 16.433 3.432 ;
     RECT  16.261 20.976 16.445 21.72 ;
     RECT  16.204 5.568 16.451 5.688 ;
     RECT  16.451 5.664 16.499 5.688 ;
     RECT  16.403 23.28 16.499 23.592 ;
     RECT  16.204 8.544 16.835 8.568 ;
     RECT  16.433 1.728 17.036 3.432 ;
     RECT  16.204 7.44 17.171 7.464 ;
     RECT  17.036 1.152 17.219 3.432 ;
     RECT  17.077 23.616 17.219 23.64 ;
     RECT  16.204 12.768 17.413 19.992 ;
     RECT  16.445 20.976 17.413 21.672 ;
     RECT  17.413 12.768 17.564 21.672 ;
     RECT  17.564 12.768 17.651 21.768 ;
     RECT  17.219 1.728 18.085 3.432 ;
     RECT  18.421 9.12 18.469 9.144 ;
     RECT  18.085 1.728 18.533 3.576 ;
     RECT  18.533 1.776 18.608 3.576 ;
     RECT  17.881 6.768 18.608 6.792 ;
     RECT  18.469 9.12 18.608 9.432 ;
     RECT  17.651 12.768 18.608 21.672 ;
     RECT  18.608 1.776 18.661 21.672 ;
     RECT  18.661 1.776 18.821 21.768 ;
     RECT  18.469 22.752 18.853 22.776 ;
     RECT  18.821 1.776 18.904 21.672 ;
     RECT  18.853 0.144 19.043 0.168 ;
     RECT  18.853 22.752 19.043 23.448 ;
     RECT  19.043 23.424 19.045 23.448 ;
     RECT  19.045 23.424 19.091 23.544 ;
     RECT  19.091 23.52 19.189 23.544 ;
     RECT  18.904 6.72 19.331 7.464 ;
     RECT  19.189 23.52 19.331 23.64 ;
     RECT  19.331 6.72 19.619 6.84 ;
     RECT  18.904 1.776 19.637 3.432 ;
     RECT  19.619 6.816 19.763 6.84 ;
     RECT  18.904 12.528 19.897 21.672 ;
     RECT  19.897 12.48 19.981 21.672 ;
     RECT  19.331 23.52 20.204 23.592 ;
     RECT  19.637 1.728 20.221 3.432 ;
     RECT  20.204 22.8 20.291 23.592 ;
     RECT  20.221 8.544 20.305 8.568 ;
     RECT  20.221 1.728 20.933 3.528 ;
     RECT  19.981 12.528 21.253 21.672 ;
     RECT  20.933 1.728 21.308 3.768 ;
     RECT  20.389 5.088 21.308 5.112 ;
     RECT  20.329 9.072 21.308 9.096 ;
     RECT  21.253 12.528 21.308 21.768 ;
     RECT  21.157 23.616 21.491 23.64 ;
     RECT  21.308 1.728 21.604 21.768 ;
     RECT  21.157 0.096 21.779 0.12 ;
     RECT  21.637 23.568 22.163 23.592 ;
     RECT  21.604 12.768 22.385 21.768 ;
     RECT  21.604 1.728 22.601 3.624 ;
     RECT  22.385 12.768 22.781 21.672 ;
     RECT  21.604 6.816 22.979 6.84 ;
     RECT  22.781 12.768 23.749 18.264 ;
     RECT  23.749 12.528 23.845 18.264 ;
     RECT  22.601 1.728 24.008 3.576 ;
     RECT  23.845 12.528 24.008 18.456 ;
     RECT  22.781 19.488 24.008 21.672 ;
     RECT  24.037 0.096 24.229 0.12 ;
     RECT  24.037 23.616 24.229 23.64 ;
     RECT  24.008 1.728 24.304 21.672 ;
     RECT  24.304 13.104 24.325 21.672 ;
     RECT  24.229 0.096 24.419 0.312 ;
     RECT  24.325 13.104 24.509 21.72 ;
     RECT  24.419 0.192 24.515 0.312 ;
     RECT  24.304 1.728 24.515 4.008 ;
     RECT  24.304 6.816 24.803 6.84 ;
     RECT  24.515 1.728 24.977 3.528 ;
     RECT  24.977 1.728 25.091 3.48 ;
     RECT  24.229 23.376 25.153 23.64 ;
     RECT  25.153 23.376 25.237 23.688 ;
     RECT  24.509 13.104 25.489 21.528 ;
     RECT  25.489 13.104 25.661 18.36 ;
     RECT  25.489 19.344 25.669 21.528 ;
     RECT  25.661 13.104 25.715 18.264 ;
     RECT  25.669 6.72 25.765 6.744 ;
     RECT  25.285 9.072 25.837 9.096 ;
     RECT  25.091 1.728 26.057 3.432 ;
     RECT  26.057 2.148 26.225 3.432 ;
     RECT  25.669 19.344 26.389 21.672 ;
     RECT  26.533 0.096 26.675 0.12 ;
     RECT  26.389 19.344 26.675 21.768 ;
     RECT  26.225 2.148 26.708 4.008 ;
     RECT  25.765 6.72 26.708 6.84 ;
     RECT  25.837 8.544 26.708 9.096 ;
     RECT  25.715 13.248 26.708 18.264 ;
     RECT  26.675 19.344 26.708 21.672 ;
     RECT  26.708 2.148 27.004 21.672 ;
     RECT  26.821 0.144 27.061 0.168 ;
     RECT  25.237 22.752 27.065 23.688 ;
     RECT  27.061 0.144 27.155 0.264 ;
     RECT  27.065 23.52 27.155 23.688 ;
     RECT  27.155 0.24 27.203 0.264 ;
     RECT  27.004 6.816 27.251 6.84 ;
     RECT  27.004 2.148 27.281 3.528 ;
     RECT  27.281 2.148 27.353 3.48 ;
     RECT  27.004 13.056 27.389 21.672 ;
     RECT  27.155 23.568 27.395 23.688 ;
     RECT  27.353 2.148 27.445 3.432 ;
     RECT  27.004 8.544 27.757 9.672 ;
     RECT  27.757 9.072 27.793 9.672 ;
     RECT  27.395 23.568 27.827 23.592 ;
     RECT  27.389 19.824 27.893 21.672 ;
     RECT  27.389 13.056 28.357 18.792 ;
     RECT  28.357 12.528 28.573 18.792 ;
     RECT  27.445 1.728 28.645 3.432 ;
     RECT  27.793 9.072 28.789 9.096 ;
     RECT  28.573 12.528 29.029 18.84 ;
     RECT  27.893 19.92 29.029 21.672 ;
     RECT  29.029 12.528 29.041 21.672 ;
     RECT  29.041 12 29.117 21.672 ;
     RECT  28.789 8.544 29.329 9.096 ;
     RECT  28.645 1.728 29.408 3.96 ;
     RECT  28.357 5.088 29.408 5.112 ;
     RECT  29.173 6.816 29.408 6.84 ;
     RECT  29.329 8.496 29.408 9.096 ;
     RECT  29.117 12 29.408 21.612 ;
     RECT  29.269 0.144 29.459 0.168 ;
     RECT  29.269 23.568 29.459 23.592 ;
     RECT  29.408 1.728 29.512 21.612 ;
     RECT  29.512 1.728 29.704 21.528 ;
     RECT  29.704 1.728 29.843 3.96 ;
     RECT  29.704 6.72 29.939 7.272 ;
     RECT  29.704 10.848 30.025 21.528 ;
     RECT  29.939 6.816 30.41 7.272 ;
     RECT  30.41 6.864 30.493 7.272 ;
     RECT  30.493 7.248 30.593 7.272 ;
     RECT  29.653 22.752 30.613 22.776 ;
     RECT  30.613 22.752 30.709 23.592 ;
     RECT  29.704 8.496 30.773 9.096 ;
     RECT  30.773 8.496 30.841 8.52 ;
     RECT  30.841 7.968 30.925 8.52 ;
     RECT  30.025 11.376 31.045 21.528 ;
     RECT  30.709 22.752 31.061 23.688 ;
     RECT  31.045 11.376 31.097 21.672 ;
     RECT  29.843 1.728 31.621 3.432 ;
     RECT  31.621 6.768 31.765 6.792 ;
     RECT  30.925 8.448 31.765 8.52 ;
     RECT  31.717 9.648 31.765 9.672 ;
     RECT  31.621 1.728 31.909 3.816 ;
     RECT  31.765 8.448 31.909 9.672 ;
     RECT  31.909 7.92 31.921 9.672 ;
     RECT  31.909 1.728 31.949 3.864 ;
     RECT  31.061 23.664 31.955 23.688 ;
     RECT  31.909 0.096 31.957 0.12 ;
     RECT  31.097 11.424 31.985 21.672 ;
     RECT  31.957 0.096 32.051 0.216 ;
     RECT  31.949 1.728 32.108 4.536 ;
     RECT  31.765 6.768 32.108 6.888 ;
     RECT  31.921 7.92 32.108 10.2 ;
     RECT  31.985 11.424 32.108 21.72 ;
     RECT  32.108 1.728 32.245 21.72 ;
     RECT  32.051 0.192 32.291 0.216 ;
     RECT  32.245 1.728 32.404 21.768 ;
     RECT  32.404 11.856 32.725 21.768 ;
     RECT  32.404 6.816 32.869 7.944 ;
     RECT  32.869 6.816 32.963 6.84 ;
     RECT  32.869 7.92 32.969 7.944 ;
     RECT  32.725 11.856 32.969 22.248 ;
     RECT  32.969 11.856 33.011 21.672 ;
     RECT  33.011 11.952 33.041 21.672 ;
     RECT  32.404 9.12 33.445 10.344 ;
     RECT  33.445 9.072 33.541 10.344 ;
     RECT  33.541 9.072 33.625 10.824 ;
     RECT  33.041 13.008 33.689 21.672 ;
     RECT  33.625 9.072 33.757 10.248 ;
     RECT  34.325 6.624 34.369 6.648 ;
     RECT  34.369 6.624 34.469 6.792 ;
     RECT  33.689 13.008 34.693 18.408 ;
     RECT  33.689 19.392 34.693 21.672 ;
     RECT  32.404 1.728 34.808 3.432 ;
     RECT  34.469 6.624 34.808 6.84 ;
     RECT  33.757 8.544 34.808 10.248 ;
     RECT  33.041 11.952 34.808 11.976 ;
     RECT  34.693 13.008 34.808 21.672 ;
     RECT  34.808 1.728 34.837 21.672 ;
     RECT  34.909 23.568 35.029 23.592 ;
     RECT  34.837 1.728 35.104 21.768 ;
     RECT  35.104 13.296 35.173 21.768 ;
     RECT  35.029 23.52 35.219 23.592 ;
     RECT  35.104 9.264 35.315 10.536 ;
     RECT  35.104 1.728 35.363 3.672 ;
     RECT  35.173 13.296 35.363 21.864 ;
     RECT  35.363 13.488 35.521 21.864 ;
     RECT  35.521 13.488 35.747 22.2 ;
     RECT  35.747 13.488 35.777 21.528 ;
     RECT  35.104 5.088 35.843 5.112 ;
     RECT  35.777 13.488 35.939 21.432 ;
     RECT  35.315 9.696 35.993 10.536 ;
     RECT  35.993 9.696 36.137 10.248 ;
     RECT  35.363 1.728 36.425 3.432 ;
     RECT  36.313 9.12 36.505 9.672 ;
     RECT  35.939 13.488 36.529 19.896 ;
     RECT  36.505 9.12 36.565 9.624 ;
     RECT  36.425 2.208 36.613 3.432 ;
     RECT  36.613 2.208 36.805 3.48 ;
     RECT  35.219 23.568 36.805 23.592 ;
     RECT  36.565 8.88 36.889 9.624 ;
     RECT  36.805 2.208 36.956 3.528 ;
     RECT  35.939 20.88 36.997 21.432 ;
     RECT  36.997 20.88 37.429 21.528 ;
     RECT  37.333 0.096 37.475 0.12 ;
     RECT  36.956 2.208 37.508 3.624 ;
     RECT  36.805 6.816 37.508 6.84 ;
     RECT  36.889 8.544 37.508 9.624 ;
     RECT  37.381 10.608 37.508 10.632 ;
     RECT  35.104 12.288 37.508 12.312 ;
     RECT  36.529 13.296 37.508 19.896 ;
     RECT  37.429 20.88 37.508 21.768 ;
     RECT  37.508 2.148 37.516 21.768 ;
     RECT  37.516 2.148 37.612 21.612 ;
     RECT  37.612 2.148 37.621 21.528 ;
     RECT  37.621 1.728 37.804 21.528 ;
     RECT  37.804 9.504 37.955 10.632 ;
     RECT  37.955 10.272 38.053 10.632 ;
     RECT  37.804 1.728 38.225 3.528 ;
     RECT  38.053 10.608 38.225 10.632 ;
     RECT  37.804 12.192 38.233 21.528 ;
     RECT  36.805 22.752 38.492 23.592 ;
     RECT  38.233 13.488 38.549 21.528 ;
     RECT  38.492 22.752 38.579 23.688 ;
     RECT  38.579 22.752 38.765 22.776 ;
     RECT  38.549 13.488 38.773 19.992 ;
     RECT  38.225 1.728 38.873 3.48 ;
     RECT  39.013 9.072 39.109 9.096 ;
     RECT  38.233 12.192 39.229 12.216 ;
     RECT  39.109 9.072 39.481 9.672 ;
     RECT  39.229 11.952 39.697 12.216 ;
     RECT  38.773 13.488 39.697 19.944 ;
     RECT  39.697 11.952 39.781 19.944 ;
     RECT  39.781 11.952 39.877 19.992 ;
     RECT  38.549 20.976 39.877 21.528 ;
     RECT  38.873 1.728 40.021 3.432 ;
     RECT  37.804 4.512 40.021 4.536 ;
     RECT  39.481 8.544 40.069 9.672 ;
     RECT  40.021 1.728 40.208 4.536 ;
     RECT  40.069 7.92 40.208 9.672 ;
     RECT  39.877 11.952 40.208 21.528 ;
     RECT  40.069 0.144 40.259 0.168 ;
     RECT  40.069 23.568 40.259 23.592 ;
     RECT  40.208 1.728 40.373 21.612 ;
     RECT  40.373 1.728 40.457 21.768 ;
     RECT  40.457 1.728 40.504 21.672 ;
     RECT  40.504 11.856 40.684 21.672 ;
     RECT  40.684 11.856 40.835 12.504 ;
     RECT  40.504 7.44 40.853 7.944 ;
     RECT  40.853 7.44 40.931 7.464 ;
     RECT  40.504 9.696 41.027 10.872 ;
     RECT  40.504 1.728 41.033 3.864 ;
     RECT  40.835 12.24 41.033 12.504 ;
     RECT  41.033 1.728 41.321 3.624 ;
     RECT  41.027 9.696 41.645 10.824 ;
     RECT  41.645 9.696 41.753 10.248 ;
     RECT  41.753 9.696 41.795 10.056 ;
     RECT  41.813 9.12 41.897 9.672 ;
     RECT  41.173 22.752 42.148 22.776 ;
     RECT  41.321 1.728 42.353 3.48 ;
     RECT  41.033 12.24 42.749 12.456 ;
     RECT  40.684 13.536 42.749 21.672 ;
     RECT  42.148 22.704 42.757 22.776 ;
     RECT  42.749 12.24 42.764 21.672 ;
     RECT  42.757 22.704 42.764 22.824 ;
     RECT  42.764 12.24 42.851 22.824 ;
     RECT  42.353 1.728 42.908 4.008 ;
     RECT  42.613 6.816 42.908 6.84 ;
     RECT  41.897 9.648 42.908 9.672 ;
     RECT  42.851 12.24 42.908 21.72 ;
     RECT  42.851 22.704 42.997 22.824 ;
     RECT  42.908 1.728 43.204 21.72 ;
     RECT  42.997 0.096 43.331 0.12 ;
     RECT  43.204 1.728 43.373 3.624 ;
     RECT  43.204 12.24 43.475 21.72 ;
     RECT  42.997 22.704 43.523 23.64 ;
     RECT  43.204 9.648 43.561 10.968 ;
     RECT  43.561 10.8 43.619 10.968 ;
     RECT  43.619 10.8 43.777 10.824 ;
     RECT  43.475 12.24 43.877 21.576 ;
     RECT  43.523 22.704 43.949 22.728 ;
     RECT  43.877 12.24 44.204 17.16 ;
     RECT  44.204 11.952 44.291 17.16 ;
     RECT  43.561 9.648 44.305 9.672 ;
     RECT  44.291 12.24 44.453 17.16 ;
     RECT  43.877 18.288 44.581 21.576 ;
     RECT  44.305 9.12 44.677 9.672 ;
     RECT  44.581 18.288 44.701 21.672 ;
     RECT  43.373 1.728 44.773 3.432 ;
     RECT  44.453 12.336 44.876 17.16 ;
     RECT  44.701 18.288 44.876 22.248 ;
     RECT  44.773 1.728 44.945 3.48 ;
     RECT  44.965 7.968 45.169 7.992 ;
     RECT  44.677 9.12 45.349 10.248 ;
     RECT  45.169 7.44 45.485 7.992 ;
     RECT  45.349 9.072 45.485 10.248 ;
     RECT  44.876 12.336 45.569 22.248 ;
     RECT  45.097 23.376 45.589 23.4 ;
     RECT  44.945 1.728 45.608 4.008 ;
     RECT  45.485 7.44 45.608 10.248 ;
     RECT  45.569 12.336 45.608 21.72 ;
     RECT  45.608 1.728 45.857 21.72 ;
     RECT  45.589 23.28 45.889 23.4 ;
     RECT  45.857 1.728 45.904 21.672 ;
     RECT  45.589 0.288 45.973 0.312 ;
     RECT  45.973 0.096 46.019 0.312 ;
     RECT  45.889 23.28 46.019 23.688 ;
     RECT  46.019 23.376 46.067 23.688 ;
     RECT  46.019 0.096 46.115 0.12 ;
     RECT  45.904 1.728 46.361 3.624 ;
     RECT  46.361 1.728 46.433 3.528 ;
     RECT  45.904 12 46.541 21.672 ;
     RECT  45.904 9.696 46.613 10.248 ;
     RECT  45.904 7.44 46.721 7.944 ;
     RECT  46.613 10.224 46.721 10.248 ;
     RECT  46.541 20.448 46.721 21.672 ;
     RECT  46.541 12 46.739 19.416 ;
     RECT  46.739 12.192 46.793 19.416 ;
     RECT  46.721 7.92 46.829 7.944 ;
     RECT  46.067 23.424 47.219 23.688 ;
     RECT  46.433 1.728 47.557 3.48 ;
     RECT  47.557 1.728 47.617 3.528 ;
     RECT  47.219 23.52 47.699 23.688 ;
     RECT  46.793 12.288 47.933 19.416 ;
     RECT  46.721 20.544 47.933 21.672 ;
     RECT  47.933 12.288 47.989 21.672 ;
     RECT  47.617 1.728 48.308 4.152 ;
     RECT  47.989 12.288 48.308 22.248 ;
     RECT  48.133 0.144 48.419 0.168 ;
     RECT  48.308 1.728 48.604 22.248 ;
     RECT  48.604 1.728 48.755 5.112 ;
     RECT  48.755 5.088 48.851 5.112 ;
     RECT  47.699 23.52 48.851 23.592 ;
     RECT  48.604 12.288 49.321 22.248 ;
     RECT  49.321 19.392 49.565 22.248 ;
     RECT  49.565 19.776 49.571 22.248 ;
     RECT  49.321 12.288 49.597 18.216 ;
     RECT  49.571 19.968 49.673 22.248 ;
     RECT  49.597 12.24 49.709 18.216 ;
     RECT  49.709 12.24 50.005 17.688 ;
     RECT  50.005 11.952 50.197 17.688 ;
     RECT  49.673 19.968 50.429 21.672 ;
     RECT  48.755 1.728 50.581 3.432 ;
     RECT  50.197 11.76 50.713 17.688 ;
     RECT  50.389 18.768 50.713 18.792 ;
     RECT  50.581 1.728 50.725 3.624 ;
     RECT  50.725 1.728 50.773 3.672 ;
     RECT  50.713 11.76 50.785 18.792 ;
     RECT  50.629 9.6 50.821 9.624 ;
     RECT  48.851 23.568 50.821 23.592 ;
     RECT  50.785 11.76 50.857 18.984 ;
     RECT  50.429 19.968 50.857 21.612 ;
     RECT  50.821 0.192 50.869 0.216 ;
     RECT  50.821 23.52 50.869 23.592 ;
     RECT  50.773 1.728 51.008 3.864 ;
     RECT  50.821 9.264 51.008 9.624 ;
     RECT  50.857 11.76 51.008 21.612 ;
     RECT  50.869 0.096 51.011 0.216 ;
     RECT  51.008 1.728 51.112 21.612 ;
     RECT  51.011 0.192 51.203 0.216 ;
     RECT  50.869 23.52 51.203 23.64 ;
     RECT  51.112 1.728 51.304 21.528 ;
     RECT  51.304 11.424 51.401 21.528 ;
     RECT  51.203 23.568 51.539 23.64 ;
     RECT  51.304 1.728 51.625 3.816 ;
     RECT  51.401 11.424 51.905 21.48 ;
     RECT  51.836 23.664 51.923 23.688 ;
     RECT  51.905 11.424 52.163 21.432 ;
     RECT  51.304 9.072 52.229 10.248 ;
     RECT  52.229 9.072 52.657 9.96 ;
     RECT  52.657 8.544 52.741 9.96 ;
     RECT  52.163 11.76 53.269 21.432 ;
     RECT  52.741 8.88 53.413 9.96 ;
     RECT  53.413 8.88 53.461 10.104 ;
     RECT  51.625 1.728 53.549 3.432 ;
     RECT  53.269 11.76 53.549 21.528 ;
     RECT  53.549 1.728 53.557 3.48 ;
     RECT  53.549 11.76 53.633 22.2 ;
     RECT  53.557 1.728 53.668 3.576 ;
     RECT  53.668 1.728 53.708 3.624 ;
     RECT  53.461 8.88 53.708 10.248 ;
     RECT  53.633 11.76 53.708 21.72 ;
     RECT  53.053 23.568 53.749 23.592 ;
     RECT  53.708 1.728 53.993 21.72 ;
     RECT  53.993 1.728 54.004 21.672 ;
     RECT  53.749 0.144 54.131 0.168 ;
     RECT  54.004 8.544 54.131 21.672 ;
     RECT  54.131 8.976 54.209 21.672 ;
     RECT  53.749 23.52 54.373 23.592 ;
     RECT  54.373 23.472 54.457 23.592 ;
     RECT  54.457 23.376 54.467 23.592 ;
     RECT  54.209 9.12 54.497 21.672 ;
     RECT  54.467 23.376 54.515 23.496 ;
     RECT  54.497 9.12 54.563 12.408 ;
     RECT  54.515 23.376 54.563 23.4 ;
     RECT  55.093 22.8 55.289 22.824 ;
     RECT  54.004 1.728 55.397 3.528 ;
     RECT  54.563 9.648 55.537 12.408 ;
     RECT  55.397 2.208 55.573 3.528 ;
     RECT  55.537 9.168 55.621 12.408 ;
     RECT  55.621 9.072 55.717 12.408 ;
     RECT  54.497 13.536 55.717 21.672 ;
     RECT  55.717 9.072 55.765 21.672 ;
     RECT  55.765 8.88 55.789 21.672 ;
     RECT  55.789 8.544 56.261 21.672 ;
     RECT  56.245 0.096 56.387 0.12 ;
     RECT  55.573 2.208 56.408 4.104 ;
     RECT  56.197 6.864 56.408 6.888 ;
     RECT  56.261 8.544 56.408 21.612 ;
     RECT  56.408 2.148 56.512 21.612 ;
     RECT  56.512 2.208 56.513 21.528 ;
     RECT  56.513 2.208 56.704 21.48 ;
     RECT  56.533 0.144 56.725 0.168 ;
     RECT  56.245 23.616 56.725 23.64 ;
     RECT  56.725 0.144 56.819 0.264 ;
     RECT  56.819 0.24 56.867 0.264 ;
     RECT  56.704 9.12 56.945 21.48 ;
     RECT  56.725 23.568 57.049 23.64 ;
     RECT  56.945 9.12 57.197 21.432 ;
     RECT  57.197 9.12 57.491 10.776 ;
     RECT  56.704 2.208 57.517 3.576 ;
     RECT  57.049 23.52 57.557 23.64 ;
     RECT  57.517 1.728 57.601 3.576 ;
     RECT  57.557 23.52 57.685 23.544 ;
     RECT  57.685 22.752 57.731 23.544 ;
     RECT  57.601 2.064 57.733 3.576 ;
     RECT  57.491 9.12 57.829 10.68 ;
     RECT  57.733 2.064 57.845 4.008 ;
     RECT  57.731 22.752 57.875 22.776 ;
     RECT  57.829 9.072 57.949 10.68 ;
     RECT  57.197 11.76 58.165 21.432 ;
     RECT  57.949 8.544 58.453 10.68 ;
     RECT  58.165 11.76 58.453 21.528 ;
     RECT  58.453 8.544 58.741 21.528 ;
     RECT  57.845 2.064 58.789 3.72 ;
     RECT  58.741 8.544 58.837 22.296 ;
     RECT  58.789 2.016 58.885 3.72 ;
     RECT  58.885 2.016 58.913 4.488 ;
     RECT  58.913 1.728 59.108 4.488 ;
     RECT  58.357 6.816 59.108 6.84 ;
     RECT  58.837 8.16 59.108 22.296 ;
     RECT  58.981 0.144 59.171 0.168 ;
     RECT  59.108 1.728 59.404 22.296 ;
     RECT  59.404 1.728 59.537 4.584 ;
     RECT  59.404 7.968 59.681 22.296 ;
     RECT  59.681 10.704 59.921 22.296 ;
     RECT  59.921 10.704 60.005 22.776 ;
     RECT  59.681 7.968 60.085 9.672 ;
     RECT  60.085 9.6 60.185 9.672 ;
     RECT  59.537 2.016 60.419 4.584 ;
     RECT  60.085 7.968 60.433 8.52 ;
     RECT  60.419 2.016 60.517 4.488 ;
     RECT  60.517 1.728 60.757 4.488 ;
     RECT  60.185 9.648 60.901 9.672 ;
     RECT  60.005 10.704 60.901 22.296 ;
     RECT  60.829 23.568 60.947 23.592 ;
     RECT  60.901 9.648 60.997 22.296 ;
     RECT  60.997 9.648 61.085 22.824 ;
     RECT  60.757 1.68 61.187 4.488 ;
     RECT  61.187 2.148 61.621 4.488 ;
     RECT  61.621 0.096 61.669 0.12 ;
     RECT  61.669 0.096 61.763 0.216 ;
     RECT  61.621 2.148 61.808 4.584 ;
     RECT  60.433 7.44 61.808 8.52 ;
     RECT  61.085 9.648 61.808 22.776 ;
     RECT  61.808 2.148 61.912 22.776 ;
     RECT  61.763 0.192 61.955 0.216 ;
     RECT  61.912 2.208 62.104 22.776 ;
     RECT  62.104 18.672 62.129 19.368 ;
     RECT  62.104 20.592 62.233 22.776 ;
     RECT  62.104 14.4 62.339 15.432 ;
     RECT  62.104 2.208 62.345 4.536 ;
     RECT  62.345 2.208 62.38 2.232 ;
     RECT  62.345 3.408 62.387 4.536 ;
     RECT  62.104 9.936 62.417 10.728 ;
     RECT  62.149 0.576 62.453 0.6 ;
     RECT  62.104 11.712 62.525 13.128 ;
     RECT  62.233 20.592 62.561 22.824 ;
     RECT  62.387 4.512 62.579 4.536 ;
     RECT  62.104 17.616 62.705 17.64 ;
     RECT  62.525 11.952 62.741 13.128 ;
     RECT  62.387 3.408 62.771 3.432 ;
     RECT  62.339 14.784 62.771 15.432 ;
     RECT  62.771 15.408 62.819 15.432 ;
     RECT  62.129 18.672 62.819 18.984 ;
     RECT  62.561 20.592 62.819 21.48 ;
     RECT  62.741 12.576 62.849 13.128 ;
     RECT  62.417 9.936 62.867 10.632 ;
     RECT  62.849 13.104 62.915 13.128 ;
     RECT  62.819 18.768 62.915 18.888 ;
     RECT  62.819 21.12 62.915 21.48 ;
     RECT  62.867 9.936 62.963 9.96 ;
     RECT  62.915 21.12 62.963 21.144 ;
     RECT  62.561 22.512 62.993 22.824 ;
     RECT  62.993 22.512 63.389 22.776 ;
     RECT  63.389 22.752 63.425 22.776 ;
    LAYER M5 ;
     RECT  0.72 0.016 62.76 3.443 ;
     RECT  12.528 3.443 62.568 3.539 ;
     RECT  0.72 3.443 11.448 4.211 ;
     RECT  0.72 4.211 1.368 4.259 ;
     RECT  12.768 3.539 62.568 4.547 ;
     RECT  0.72 4.259 0.744 4.691 ;
     RECT  2.4 4.211 11.448 5.123 ;
     RECT  12.768 4.547 62.112 5.123 ;
     RECT  12.768 5.123 13.512 6.899 ;
     RECT  14.544 5.123 62.112 7.475 ;
     RECT  2.4 5.123 10.812 8.003 ;
     RECT  2.4 8.003 9.384 8.051 ;
     RECT  10.368 8.003 10.812 8.579 ;
     RECT  2.4 8.051 9.192 8.675 ;
     RECT  2.4 8.675 8.112 9.155 ;
     RECT  14.544 7.475 60.792 9.637 ;
     RECT  61.8 7.475 62.112 9.637 ;
     RECT  4.176 9.155 6.168 9.731 ;
     RECT  9.168 8.675 9.192 9.731 ;
     RECT  14.544 9.637 62.112 9.925 ;
     RECT  7.8 9.155 8.112 11.173 ;
     RECT  7.68 11.173 8.112 11.221 ;
     RECT  10.5 8.579 10.812 11.221 ;
     RECT  2.4 9.155 2.712 11.365 ;
     RECT  3.744 11.221 3.768 11.365 ;
     RECT  9.936 11.221 10.812 11.365 ;
     RECT  6.96 11.221 8.112 11.509 ;
     RECT  6.96 11.509 8.424 11.749 ;
     RECT  2.4 11.365 3.768 11.941 ;
     RECT  5.1 9.731 5.412 11.941 ;
     RECT  6.576 11.749 8.424 11.941 ;
     RECT  9.648 11.365 10.812 12.515 ;
     RECT  14.544 9.925 62.952 12.515 ;
     RECT  12.096 11.845 12.12 12.517 ;
     RECT  13.2 6.899 13.512 12.517 ;
     RECT  9.936 12.515 10.812 12.997 ;
     RECT  12.096 12.517 13.512 12.997 ;
     RECT  2.4 11.941 5.412 13.045 ;
     RECT  9.936 12.997 13.512 13.477 ;
     RECT  14.592 12.515 62.952 13.477 ;
     RECT  2.256 13.045 5.412 13.573 ;
     RECT  6.48 11.941 8.424 13.669 ;
     RECT  6.48 13.669 8.952 14.005 ;
     RECT  2.208 13.573 5.412 14.245 ;
     RECT  6.384 14.005 8.952 14.245 ;
     RECT  0.192 6.421 0.216 14.435 ;
     RECT  2.208 14.245 8.952 14.821 ;
     RECT  9.936 13.477 62.952 14.821 ;
     RECT  2.208 14.821 62.952 14.867 ;
     RECT  2.208 14.867 14.808 16.165 ;
     RECT  15.792 14.867 62.952 16.165 ;
     RECT  1.152 17.509 1.176 17.605 ;
     RECT  2.208 16.165 62.952 17.605 ;
     RECT  1.152 17.605 62.952 18.181 ;
     RECT  0.96 18.181 62.952 20.485 ;
     RECT  0.72 20.485 62.952 21.155 ;
     RECT  0.72 21.155 62.904 21.491 ;
     RECT  0.72 21.491 62.76 23.696 ;
     RECT  4.8 23.696 4.824 23.699 ;
     RECT  6.24 23.696 6.264 23.699 ;
     RECT  7.44 23.696 7.464 23.699 ;
     RECT  11.616 23.696 11.64 23.699 ;
     RECT  15.408 23.696 15.432 23.699 ;
     RECT  27.36 23.696 27.384 23.699 ;
     RECT  30.72 23.696 30.744 23.699 ;
     RECT  31.92 23.696 31.944 23.699 ;
     RECT  38.544 23.696 38.568 23.699 ;
     RECT  47.664 23.696 47.688 23.699 ;
     RECT  51.888 23.696 51.912 23.699 ;
  END
END hbfd_rly_624_SN_rrfc
END LIBRARY
